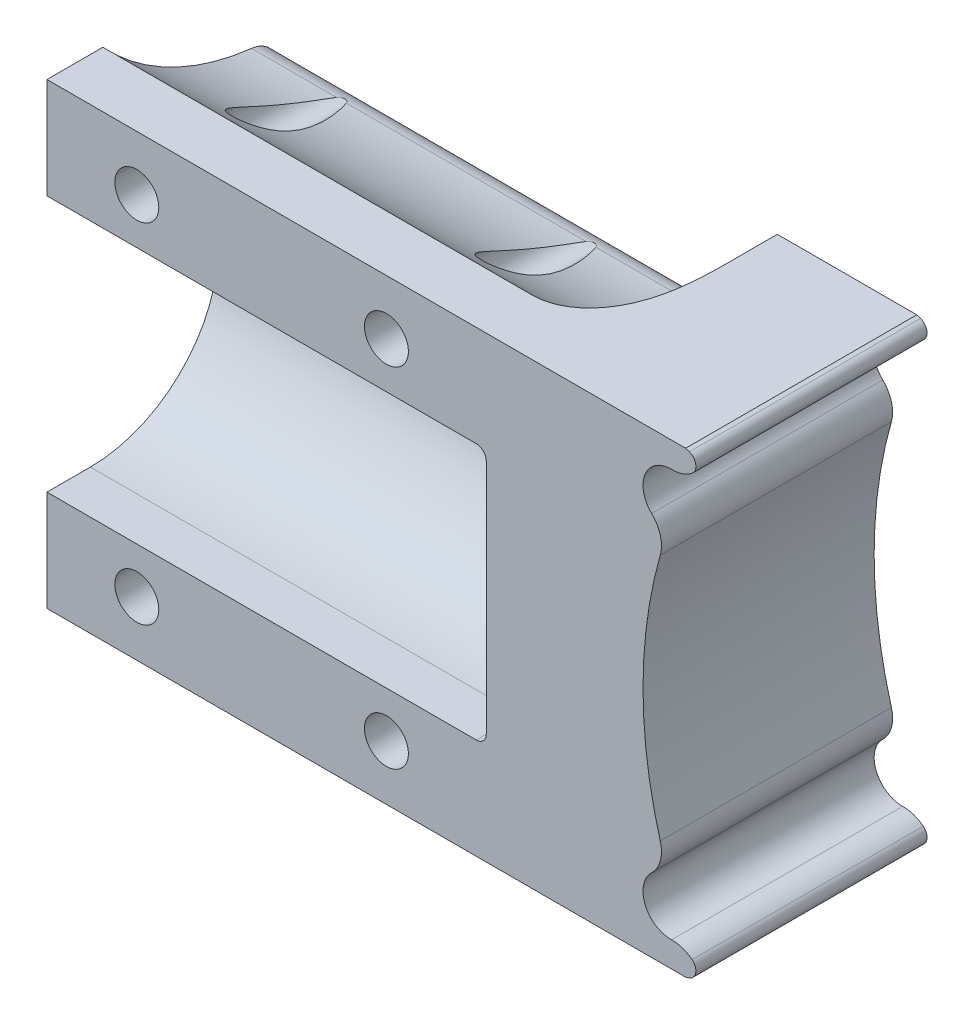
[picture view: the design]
ISO-10303-21;
HEADER;
FILE_DESCRIPTION(('STEP AP214'),'2;1');
FILE_NAME('part.step','',(''),(''),'','','');
FILE_SCHEMA(('AUTOMOTIVE_DESIGN { 1 0 10303 214 1 1 1 1 }'));
ENDSEC;
DATA;
#1=APPLICATION_CONTEXT('core data for automotive mechanical design processes');
#2=APPLICATION_PROTOCOL_DEFINITION('international standard','automotive_design',2000,#1);
#3=PRODUCT_CONTEXT('',#1,'mechanical');
#4=PRODUCT('Part','Part','',(#3));
#5=PRODUCT_RELATED_PRODUCT_CATEGORY('part','',(#4));
#6=PRODUCT_DEFINITION_FORMATION('','',#4);
#7=PRODUCT_DEFINITION_CONTEXT('part definition',#1,'design');
#8=PRODUCT_DEFINITION('design','',#6,#7);
#9=PRODUCT_DEFINITION_SHAPE('','',#8);
#10=(LENGTH_UNIT() NAMED_UNIT(*) SI_UNIT(.MILLI.,.METRE.));
#11=(NAMED_UNIT(*) PLANE_ANGLE_UNIT() SI_UNIT($,.RADIAN.));
#12=(NAMED_UNIT(*) SI_UNIT($,.STERADIAN.) SOLID_ANGLE_UNIT());
#13=UNCERTAINTY_MEASURE_WITH_UNIT(LENGTH_MEASURE(1.E-05),#10,'distance_accuracy_value','');
#14=(GEOMETRIC_REPRESENTATION_CONTEXT(3) GLOBAL_UNCERTAINTY_ASSIGNED_CONTEXT((#13)) GLOBAL_UNIT_ASSIGNED_CONTEXT((#10,
#11,#12)) REPRESENTATION_CONTEXT('',''));
#15=CARTESIAN_POINT('',(0.,0.,0.));
#16=DIRECTION('',(0.,0.,1.));
#17=DIRECTION('',(1.,0.,0.));
#18=AXIS2_PLACEMENT_3D('',#15,#16,#17);
#19=CARTESIAN_POINT('',(50.,-22.9398492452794,0.));
#20=DIRECTION('',(0.,1.,0.));
#21=DIRECTION('',(0.,0.,1.));
#22=AXIS2_PLACEMENT_3D('',#19,#20,#21);
#23=PLANE('',#22);
#24=DIRECTION('',(1.,0.,0.));
#25=VECTOR('',#24,1.);
#26=CARTESIAN_POINT('',(0.,-22.9398492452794,-0.4));
#27=LINE('',#26,#25);
#28=CARTESIAN_POINT('',(0.,-22.9398492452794,-0.4));
#29=VERTEX_POINT('',#28);
#30=CARTESIAN_POINT('',(63.9692143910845,-22.9398492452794,-0.399999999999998));
#31=VERTEX_POINT('',#30);
#32=EDGE_CURVE('E268',#29,#31,#27,.T.);
#33=ORIENTED_EDGE('',*,*,#32,.F.);
#34=DIRECTION('',(0.,0.,-1.));
#35=VECTOR('',#34,1.);
#36=CARTESIAN_POINT('',(0.,-22.9398492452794,0.));
#37=LINE('',#36,#35);
#38=CARTESIAN_POINT('',(0.,-22.9398492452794,-6.));
#39=VERTEX_POINT('',#38);
#40=EDGE_CURVE('E285',#29,#39,#37,.T.);
#41=ORIENTED_EDGE('',*,*,#40,.T.);
#42=DIRECTION('',(-1.,0.,0.));
#43=VECTOR('',#42,1.);
#44=CARTESIAN_POINT('',(50.,-22.9398492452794,-6.));
#45=LINE('',#44,#43);
#46=CARTESIAN_POINT('',(43.,-22.9398492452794,-6.));
#47=VERTEX_POINT('',#46);
#48=EDGE_CURVE('E321',#47,#39,#45,.T.);
#49=ORIENTED_EDGE('',*,*,#48,.F.);
#50=CARTESIAN_POINT('',(43.,-22.9398492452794,-6.));
#51=CARTESIAN_POINT('',(43.1567440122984,-22.9398492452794,-5.99995899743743));
#52=CARTESIAN_POINT('',(43.3134721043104,-22.9398492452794,-6.00715912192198));
#53=CARTESIAN_POINT('',(43.6255568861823,-22.9398492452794,-6.03573656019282));
#54=CARTESIAN_POINT('',(43.7809142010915,-22.9398492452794,-6.05710703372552));
#55=CARTESIAN_POINT('',(44.0881112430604,-22.9398492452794,-6.11354422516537));
#56=CARTESIAN_POINT('',(44.2399668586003,-22.9398492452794,-6.14852475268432));
#57=CARTESIAN_POINT('',(44.5400379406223,-22.9398492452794,-6.23163812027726));
#58=CARTESIAN_POINT('',(44.6882531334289,-22.9398492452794,-6.27977194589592));
#59=CARTESIAN_POINT('',(44.9797530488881,-22.9398492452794,-6.38838771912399));
#60=CARTESIAN_POINT('',(45.1230466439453,-22.9398492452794,-6.44884591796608));
#61=CARTESIAN_POINT('',(45.4042220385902,-22.9398492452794,-6.58137314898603));
#62=CARTESIAN_POINT('',(45.5421014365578,-22.9398492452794,-6.65344726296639));
#63=CARTESIAN_POINT('',(45.8118729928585,-22.9398492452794,-6.80838239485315));
#64=CARTESIAN_POINT('',(45.9437575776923,-22.9398492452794,-6.89125657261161));
#65=CARTESIAN_POINT('',(46.2008606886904,-22.9398492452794,-7.06678420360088));
#66=CARTESIAN_POINT('',(46.3260778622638,-22.9398492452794,-7.15943962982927));
#67=CARTESIAN_POINT('',(46.6059669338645,-22.9398492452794,-7.38269201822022));
#68=CARTESIAN_POINT('',(46.7582169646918,-22.9398492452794,-7.5163368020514));
#69=CARTESIAN_POINT('',(47.050351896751,-22.9398492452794,-7.79647915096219));
#70=CARTESIAN_POINT('',(47.1902337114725,-22.9398492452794,-7.94297990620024));
#71=CARTESIAN_POINT('',(47.5910417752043,-22.9398492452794,-8.39881021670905));
#72=CARTESIAN_POINT('',(47.8333450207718,-22.9398492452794,-8.72464357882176));
#73=CARTESIAN_POINT('',(48.3591599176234,-22.9398492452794,-9.54645515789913));
#74=CARTESIAN_POINT('',(48.6189291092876,-22.9398492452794,-10.0574775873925));
#75=CARTESIAN_POINT('',(48.9470840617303,-22.9398492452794,-10.8502483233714));
#76=CARTESIAN_POINT('',(49.0465025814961,-22.9398492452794,-11.1200553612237));
#77=CARTESIAN_POINT('',(49.2264271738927,-22.9398492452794,-11.6658589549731));
#78=CARTESIAN_POINT('',(49.306939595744,-22.9398492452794,-11.9418533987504));
#79=CARTESIAN_POINT('',(49.5191215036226,-22.9398492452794,-12.7605130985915));
#80=CARTESIAN_POINT('',(49.6274334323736,-22.9398492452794,-13.309213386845));
#81=CARTESIAN_POINT('',(49.795746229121,-22.9398492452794,-14.4147405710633));
#82=CARTESIAN_POINT('',(49.8556282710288,-22.9398492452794,-14.9715840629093));
#83=CARTESIAN_POINT('',(49.9190284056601,-22.9398492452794,-15.8002040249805));
#84=CARTESIAN_POINT('',(49.9356916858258,-22.9398492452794,-16.0710994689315));
#85=CARTESIAN_POINT('',(49.962449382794,-22.9398492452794,-16.6132407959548));
#86=CARTESIAN_POINT('',(49.9725432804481,-22.9398492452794,-16.884486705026));
#87=CARTESIAN_POINT('',(49.987579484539,-22.9398492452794,-17.4256106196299));
#88=CARTESIAN_POINT('',(49.9925498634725,-22.9398492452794,-17.6954879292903));
#89=CARTESIAN_POINT('',(49.9987501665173,-22.9398492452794,-18.2352124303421));
#90=CARTESIAN_POINT('',(49.9999811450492,-22.9398492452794,-18.505059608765));
#91=CARTESIAN_POINT('',(50.,-22.9398492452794,-18.7748901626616));
#92=B_SPLINE_CURVE_WITH_KNOTS('',3,(#50,#51,#52,#53,#54,#55,#56,#57,#58,#59,#60,#61,#62,#63,#64,
#65,#66,#67,#68,#69,#70,#71,#72,#73,#74,#75,#76,#77,#78,#79,#80,#81,#82,#83,#84,#85,#86,#87,#88,
#89,#90,#91),.UNSPECIFIED.,.F.,.F.,(4,2,2,2,2,2,2,2,2,2,2,2,2,2,2,2,2,2,2,2,4),(0.,
0.470041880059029,0.939857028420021,1.40674410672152,1.87366617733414,2.33969686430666,
2.80593198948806,3.27274062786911,3.73964360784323,4.34650229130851,4.9535119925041,
6.16671054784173,7.87660132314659,8.73874642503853,9.60060157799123,11.2752124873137,
12.9539198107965,13.7680828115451,14.5823101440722,15.3920521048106,16.2015657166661),.UNSPECIFIED.);
#93=CARTESIAN_POINT('',(50.,-22.9398492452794,-18.7748901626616));
#94=VERTEX_POINT('',#93);
#95=EDGE_CURVE('E414',#47,#94,#92,.T.);
#96=ORIENTED_EDGE('',*,*,#95,.T.);
#97=DIRECTION('',(0.,0.,1.));
#98=VECTOR('',#97,1.);
#99=CARTESIAN_POINT('',(50.,-22.9398492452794,-72.0435791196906));
#100=LINE('',#99,#98);
#101=CARTESIAN_POINT('',(50.,-22.9398492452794,-23.55));
#102=VERTEX_POINT('',#101);
#103=EDGE_CURVE('E720',#102,#94,#100,.T.);
#104=ORIENTED_EDGE('',*,*,#103,.F.);
#105=DIRECTION('',(-1.,0.,0.));
#106=VECTOR('',#105,1.);
#107=CARTESIAN_POINT('',(0.,-22.9398492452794,-23.55));
#108=LINE('',#107,#106);
#109=CARTESIAN_POINT('',(63.9692143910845,-22.9398492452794,-23.55));
#110=VERTEX_POINT('',#109);
#111=EDGE_CURVE('E735',#110,#102,#108,.T.);
#112=ORIENTED_EDGE('',*,*,#111,.F.);
#113=DIRECTION('',(0.,0.,1.));
#114=VECTOR('',#113,1.);
#115=CARTESIAN_POINT('',(63.9692143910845,-22.9398492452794,-69.8217694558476));
#116=LINE('',#115,#114);
#117=EDGE_CURVE('E287',#110,#31,#116,.T.);
#118=ORIENTED_EDGE('',*,*,#117,.T.);
#119=EDGE_LOOP('',(#33,#41,#49,#96,#104,#112,#118));
#120=FACE_BOUND('',#119,.T.);
#121=ADVANCED_FACE('F49',(#120),#23,.F.);
#122=CARTESIAN_POINT('',(50.,22.9398492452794,0.));
#123=DIRECTION('',(0.,-1.,0.));
#124=DIRECTION('',(0.,0.,-1.));
#125=AXIS2_PLACEMENT_3D('',#122,#123,#124);
#126=PLANE('',#125);
#127=DIRECTION('',(-1.,0.,0.));
#128=VECTOR('',#127,1.);
#129=CARTESIAN_POINT('',(0.,22.9398492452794,-0.4));
#130=LINE('',#129,#128);
#131=CARTESIAN_POINT('',(63.9692143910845,22.9398492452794,-0.399999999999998));
#132=VERTEX_POINT('',#131);
#133=CARTESIAN_POINT('',(0.,22.9398492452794,-0.4));
#134=VERTEX_POINT('',#133);
#135=EDGE_CURVE('E289',#132,#134,#130,.T.);
#136=ORIENTED_EDGE('',*,*,#135,.F.);
#137=DIRECTION('',(0.,0.,1.));
#138=VECTOR('',#137,1.);
#139=CARTESIAN_POINT('',(63.9692143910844,22.9398492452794,-69.8217694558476));
#140=LINE('',#139,#138);
#141=CARTESIAN_POINT('',(63.9692143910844,22.9398492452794,-23.55));
#142=VERTEX_POINT('',#141);
#143=EDGE_CURVE('E677',#142,#132,#140,.T.);
#144=ORIENTED_EDGE('',*,*,#143,.F.);
#145=DIRECTION('',(1.,0.,0.));
#146=VECTOR('',#145,1.);
#147=CARTESIAN_POINT('',(0.,22.9398492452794,-23.55));
#148=LINE('',#147,#146);
#149=CARTESIAN_POINT('',(50.,22.9398492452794,-23.55));
#150=VERTEX_POINT('',#149);
#151=EDGE_CURVE('E728',#150,#142,#148,.T.);
#152=ORIENTED_EDGE('',*,*,#151,.F.);
#153=DIRECTION('',(0.,0.,1.));
#154=VECTOR('',#153,1.);
#155=CARTESIAN_POINT('',(50.,22.9398492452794,-72.0435791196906));
#156=LINE('',#155,#154);
#157=CARTESIAN_POINT('',(50.,22.9398492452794,-18.7748901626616));
#158=VERTEX_POINT('',#157);
#159=EDGE_CURVE('E709',#150,#158,#156,.T.);
#160=ORIENTED_EDGE('',*,*,#159,.T.);
#161=CARTESIAN_POINT('',(50.,22.9398492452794,-18.7748901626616));
#162=CARTESIAN_POINT('',(49.9999747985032,22.9398492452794,-18.4850096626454));
#163=CARTESIAN_POINT('',(49.9985573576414,22.9398492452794,-18.1951043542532));
#164=CARTESIAN_POINT('',(49.9912954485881,22.9398492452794,-17.6152426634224));
#165=CARTESIAN_POINT('',(49.9854492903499,22.9398492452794,-17.325286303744));
#166=CARTESIAN_POINT('',(49.9676179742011,22.9398492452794,-16.7433581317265));
#167=CARTESIAN_POINT('',(49.9555868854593,22.9398492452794,-16.4513875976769));
#168=CARTESIAN_POINT('',(49.9235253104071,22.9398492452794,-15.8679096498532));
#169=CARTESIAN_POINT('',(49.9034957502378,22.9398492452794,-15.5764021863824));
#170=CARTESIAN_POINT('',(49.8529973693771,22.9398492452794,-14.9883362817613));
#171=CARTESIAN_POINT('',(49.8223265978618,22.9398492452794,-14.6917942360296));
#172=CARTESIAN_POINT('',(49.7485056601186,22.9398492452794,-14.1002784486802));
#173=CARTESIAN_POINT('',(49.7053537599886,22.9398492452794,-13.8053049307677));
#174=CARTESIAN_POINT('',(49.5541030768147,22.9398492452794,-12.925843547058));
#175=CARTESIAN_POINT('',(49.4240528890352,22.9398492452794,-12.3445971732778));
#176=CARTESIAN_POINT('',(49.1955901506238,22.9398492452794,-11.5712953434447));
#177=CARTESIAN_POINT('',(49.1305538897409,22.9398492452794,-11.3691742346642));
#178=CARTESIAN_POINT('',(48.9898273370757,22.9398492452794,-10.9685768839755));
#179=CARTESIAN_POINT('',(48.9141343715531,22.9398492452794,-10.7701015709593));
#180=CARTESIAN_POINT('',(48.7515440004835,22.9398492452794,-10.3784272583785));
#181=CARTESIAN_POINT('',(48.6646785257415,22.9398492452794,-10.1852150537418));
#182=CARTESIAN_POINT('',(48.4788432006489,22.9398492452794,-9.80468884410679));
#183=CARTESIAN_POINT('',(48.3798741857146,22.9398492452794,-9.61737443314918));
#184=CARTESIAN_POINT('',(48.168089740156,22.9398492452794,-9.24813870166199));
#185=CARTESIAN_POINT('',(48.0551422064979,22.9398492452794,-9.06629279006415));
#186=CARTESIAN_POINT('',(47.8157094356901,22.9398492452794,-8.71174871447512));
#187=CARTESIAN_POINT('',(47.6892267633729,22.9398492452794,-8.53904882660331));
#188=CARTESIAN_POINT('',(47.4223990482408,22.9398492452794,-8.20470801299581));
#189=CARTESIAN_POINT('',(47.2820560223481,22.9398492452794,-8.04306548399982));
#190=CARTESIAN_POINT('',(46.9874613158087,22.9398492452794,-7.73299360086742));
#191=CARTESIAN_POINT('',(46.833213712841,22.9398492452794,-7.58456039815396));
#192=CARTESIAN_POINT('',(46.5479809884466,22.9398492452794,-7.33541276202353));
#193=CARTESIAN_POINT('',(46.4197408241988,22.9398492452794,-7.23154752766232));
#194=CARTESIAN_POINT('',(46.1555248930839,22.9398492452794,-7.0341903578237));
#195=CARTESIAN_POINT('',(46.0195508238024,22.9398492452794,-6.94069615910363));
#196=CARTESIAN_POINT('',(45.7405636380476,22.9398492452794,-6.76532669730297));
#197=CARTESIAN_POINT('',(45.597561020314,22.9398492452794,-6.68343477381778));
#198=CARTESIAN_POINT('',(45.3051147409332,22.9398492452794,-6.53224455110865));
#199=CARTESIAN_POINT('',(45.155674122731,22.9398492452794,-6.46294038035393));
#200=CARTESIAN_POINT('',(44.8456264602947,22.9398492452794,-6.3356125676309));
#201=CARTESIAN_POINT('',(44.6848109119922,22.9398492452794,-6.27809445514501));
#202=CARTESIAN_POINT('',(44.3584355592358,22.9398492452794,-6.17862733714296));
#203=CARTESIAN_POINT('',(44.1928761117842,22.9398492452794,-6.1366771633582));
#204=CARTESIAN_POINT('',(43.8570375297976,22.9398492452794,-6.06884020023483));
#205=CARTESIAN_POINT('',(43.6867304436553,22.9398492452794,-6.0430912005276));
#206=CARTESIAN_POINT('',(43.3442913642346,22.9398492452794,-6.00863578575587));
#207=CARTESIAN_POINT('',(43.1721582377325,22.9398492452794,-5.99994066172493));
#208=CARTESIAN_POINT('',(43.,22.9398492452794,-5.99999999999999));
#209=B_SPLINE_CURVE_WITH_KNOTS('',3,(#161,#162,#163,#164,#165,#166,#167,#168,#169,#170,#171,
#172,#173,#174,#175,#176,#177,#178,#179,#180,#181,#182,#183,#184,#185,#186,#187,#188,#189,#190,
#191,#192,#193,#194,#195,#196,#197,#198,#199,#200,#201,#202,#203,#204,#205,#206,#207,#208),
.UNSPECIFIED.,.F.,.F.,(4,2,2,2,2,2,2,2,2,2,2,2,2,2,2,2,2,2,2,2,2,2,2,4),(0.,0.869676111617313,
1.73968426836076,2.61624871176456,3.49271168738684,4.38681102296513,5.28103462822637,
7.0628324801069,7.69958927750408,8.33650612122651,8.97164151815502,9.60673310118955,
10.2483652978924,10.8898761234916,11.5312937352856,12.1725238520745,12.6671403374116,
13.1616486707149,13.6554395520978,14.1489995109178,14.6606184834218,15.172199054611,
15.6880737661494,16.2042899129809),.UNSPECIFIED.);
#210=CARTESIAN_POINT('',(43.,22.9398492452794,-6.));
#211=VERTEX_POINT('',#210);
#212=EDGE_CURVE('E423',#158,#211,#209,.T.);
#213=ORIENTED_EDGE('',*,*,#212,.T.);
#214=DIRECTION('',(-1.,0.,0.));
#215=VECTOR('',#214,1.);
#216=CARTESIAN_POINT('',(50.,22.9398492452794,-6.));
#217=LINE('',#216,#215);
#218=CARTESIAN_POINT('',(0.,22.9398492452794,-6.));
#219=VERTEX_POINT('',#218);
#220=EDGE_CURVE('E319',#211,#219,#217,.T.);
#221=ORIENTED_EDGE('',*,*,#220,.T.);
#222=DIRECTION('',(0.,0.,1.));
#223=VECTOR('',#222,1.);
#224=CARTESIAN_POINT('',(0.,22.9398492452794,0.));
#225=LINE('',#224,#223);
#226=EDGE_CURVE('E311',#219,#134,#225,.T.);
#227=ORIENTED_EDGE('',*,*,#226,.T.);
#228=EDGE_LOOP('',(#136,#144,#152,#160,#213,#221,#227));
#229=FACE_BOUND('',#228,.T.);
#230=ADVANCED_FACE('F409',(#229),#126,.F.);
#231=CARTESIAN_POINT('',(0.,0.,-4.75));
#232=DIRECTION('',(1.,0.,0.));
#233=DIRECTION('',(0.,0.,-1.));
#234=AXIS2_PLACEMENT_3D('',#231,#232,#233);
#235=PLANE('',#234);
#236=DIRECTION('',(0.,-1.,0.));
#237=VECTOR('',#236,1.);
#238=CARTESIAN_POINT('',(0.,22.9398492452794,-0.4));
#239=LINE('',#238,#237);
#240=CARTESIAN_POINT('',(0.,12.85,-0.4));
#241=VERTEX_POINT('',#240);
#242=EDGE_CURVE('E280',#134,#241,#239,.T.);
#243=ORIENTED_EDGE('',*,*,#242,.F.);
#244=ORIENTED_EDGE('',*,*,#226,.F.);
#245=CARTESIAN_POINT('',(0.,39.1214875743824,-23.55));
#246=DIRECTION('',(-1.,0.,0.));
#247=DIRECTION('',(0.,0.,-1.));
#248=AXIS2_PLACEMENT_3D('',#245,#246,#247);
#249=CIRCLE('',#248,23.8714875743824);
#250=CARTESIAN_POINT('',(0.,15.3992341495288,-20.8849274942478));
#251=VERTEX_POINT('',#250);
#252=EDGE_CURVE('E308',#251,#219,#249,.T.);
#253=ORIENTED_EDGE('',*,*,#252,.F.);
#254=CARTESIAN_POINT('',(0.,12.4179888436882,-20.55));
#255=DIRECTION('',(1.,0.,0.));
#256=DIRECTION('',(0.,0.,-1.));
#257=AXIS2_PLACEMENT_3D('',#254,#255,#256);
#258=CIRCLE('',#257,3.);
#259=CARTESIAN_POINT('',(0.,12.4179888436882,-23.55));
#260=VERTEX_POINT('',#259);
#261=EDGE_CURVE('E333',#251,#260,#258,.F.);
#262=ORIENTED_EDGE('',*,*,#261,.T.);
#263=DIRECTION('',(0.,1.,0.));
#264=VECTOR('',#263,1.);
#265=CARTESIAN_POINT('',(0.,-15.25,-23.55));
#266=LINE('',#265,#264);
#267=CARTESIAN_POINT('',(0.,-12.4179888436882,-23.55));
#268=VERTEX_POINT('',#267);
#269=EDGE_CURVE('E299',#268,#260,#266,.T.);
#270=ORIENTED_EDGE('',*,*,#269,.F.);
#271=CARTESIAN_POINT('',(0.,-12.4179888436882,-20.55));
#272=DIRECTION('',(1.,0.,0.));
#273=DIRECTION('',(0.,0.,-1.));
#274=AXIS2_PLACEMENT_3D('',#271,#272,#273);
#275=CIRCLE('',#274,3.);
#276=CARTESIAN_POINT('',(0.,-15.3992341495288,-20.8849274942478));
#277=VERTEX_POINT('',#276);
#278=EDGE_CURVE('E335',#268,#277,#275,.F.);
#279=ORIENTED_EDGE('',*,*,#278,.T.);
#280=CARTESIAN_POINT('',(0.,-39.1214875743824,-23.55));
#281=DIRECTION('',(-1.,0.,0.));
#282=DIRECTION('',(0.,0.,1.));
#283=AXIS2_PLACEMENT_3D('',#280,#281,#282);
#284=CIRCLE('',#283,23.8714875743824);
#285=EDGE_CURVE('E291',#39,#277,#284,.T.);
#286=ORIENTED_EDGE('',*,*,#285,.F.);
#287=ORIENTED_EDGE('',*,*,#40,.F.);
#288=CARTESIAN_POINT('',(0.,-12.85,-0.4));
#289=VERTEX_POINT('',#288);
#290=EDGE_CURVE('E264',#289,#29,#239,.T.);
#291=ORIENTED_EDGE('',*,*,#290,.F.);
#292=DIRECTION('',(0.,0.,1.));
#293=VECTOR('',#292,1.);
#294=CARTESIAN_POINT('',(0.,-12.85,-4.75));
#295=LINE('',#294,#293);
#296=CARTESIAN_POINT('',(0.,-12.85,-4.75));
#297=VERTEX_POINT('',#296);
#298=EDGE_CURVE('E501',#297,#289,#295,.T.);
#299=ORIENTED_EDGE('',*,*,#298,.F.);
#300=CARTESIAN_POINT('',(0.,0.,-4.75));
#301=DIRECTION('',(-1.,0.,0.));
#302=DIRECTION('',(0.,0.,-1.));
#303=AXIS2_PLACEMENT_3D('',#300,#301,#302);
#304=CIRCLE('',#303,12.85);
#305=CARTESIAN_POINT('',(0.,12.85,-4.75));
#306=VERTEX_POINT('',#305);
#307=EDGE_CURVE('E296',#306,#297,#304,.T.);
#308=ORIENTED_EDGE('',*,*,#307,.F.);
#309=DIRECTION('',(0.,0.,-1.));
#310=VECTOR('',#309,1.);
#311=CARTESIAN_POINT('',(0.,12.85,-4.75));
#312=LINE('',#311,#310);
#313=EDGE_CURVE('E764',#241,#306,#312,.T.);
#314=ORIENTED_EDGE('',*,*,#313,.F.);
#315=EDGE_LOOP('',(#243,#244,#253,#262,#270,#279,#286,#287,#291,#299,#308,#314));
#316=FACE_BOUND('',#315,.T.);
#317=ADVANCED_FACE('F295',(#316),#235,.F.);
#318=CARTESIAN_POINT('',(44.,0.,-4.75));
#319=DIRECTION('',(1.,0.,0.));
#320=DIRECTION('',(0.,0.,-1.));
#321=AXIS2_PLACEMENT_3D('',#318,#319,#320);
#322=PLANE('',#321);
#323=DIRECTION('',(0.,-1.,0.));
#324=VECTOR('',#323,1.);
#325=CARTESIAN_POINT('',(44.,0.,-0.4));
#326=LINE('',#325,#324);
#327=CARTESIAN_POINT('',(44.,11.85,-0.4));
#328=VERTEX_POINT('',#327);
#329=CARTESIAN_POINT('',(44.,-11.85,-0.4));
#330=VERTEX_POINT('',#329);
#331=EDGE_CURVE('E63',#328,#330,#326,.T.);
#332=ORIENTED_EDGE('',*,*,#331,.F.);
#333=DIRECTION('',(0.,0.,-1.));
#334=VECTOR('',#333,1.);
#335=CARTESIAN_POINT('',(44.,11.85,-4.75));
#336=LINE('',#335,#334);
#337=CARTESIAN_POINT('',(44.,11.85,-4.75));
#338=VERTEX_POINT('',#337);
#339=EDGE_CURVE('E516',#328,#338,#336,.T.);
#340=ORIENTED_EDGE('',*,*,#339,.T.);
#341=CARTESIAN_POINT('',(44.,0.,-4.75));
#342=DIRECTION('',(1.,0.,0.));
#343=DIRECTION('',(0.,0.,-1.));
#344=AXIS2_PLACEMENT_3D('',#341,#342,#343);
#345=CIRCLE('',#344,11.85);
#346=CARTESIAN_POINT('',(44.,-11.85,-4.75));
#347=VERTEX_POINT('',#346);
#348=EDGE_CURVE('E495',#338,#347,#345,.F.);
#349=ORIENTED_EDGE('',*,*,#348,.T.);
#350=DIRECTION('',(0.,0.,1.));
#351=VECTOR('',#350,1.);
#352=CARTESIAN_POINT('',(44.,-11.85,0.));
#353=LINE('',#352,#351);
#354=EDGE_CURVE('E513',#347,#330,#353,.T.);
#355=ORIENTED_EDGE('',*,*,#354,.T.);
#356=EDGE_LOOP('',(#332,#340,#349,#355));
#357=FACE_BOUND('',#356,.T.);
#358=ADVANCED_FACE('F650',(#357),#322,.F.);
#359=CARTESIAN_POINT('',(62.6302829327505,23.6020565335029,-69.8217694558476));
#360=DIRECTION('',(0.,0.,1.));
#361=DIRECTION('',(1.,0.,0.));
#362=AXIS2_PLACEMENT_3D('',#359,#360,#361);
#363=CYLINDRICAL_SURFACE('',#362,3.20000000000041);
#364=DIRECTION('',(0.,0.,1.));
#365=VECTOR('',#364,1.);
#366=CARTESIAN_POINT('',(64.6198496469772,21.095739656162,-69.8217694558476));
#367=LINE('',#366,#365);
#368=CARTESIAN_POINT('',(64.6198496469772,21.095739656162,-23.55));
#369=VERTEX_POINT('',#368);
#370=CARTESIAN_POINT('',(64.6198496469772,21.095739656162,-0.399999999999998));
#371=VERTEX_POINT('',#370);
#372=EDGE_CURVE('E699',#369,#371,#367,.T.);
#373=ORIENTED_EDGE('',*,*,#372,.T.);
#374=CARTESIAN_POINT('',(62.6302829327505,23.6020565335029,-0.399999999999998));
#375=DIRECTION('',(0.,0.,1.));
#376=DIRECTION('',(1.,0.,0.));
#377=AXIS2_PLACEMENT_3D('',#374,#375,#376);
#378=CIRCLE('',#377,3.20000000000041);
#379=CARTESIAN_POINT('',(62.5616208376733,20.4027932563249,-0.399999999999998));
#380=VERTEX_POINT('',#379);
#381=EDGE_CURVE('E948',#371,#380,#378,.F.);
#382=ORIENTED_EDGE('',*,*,#381,.T.);
#383=DIRECTION('',(0.,0.,1.));
#384=VECTOR('',#383,1.);
#385=CARTESIAN_POINT('',(62.5616208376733,20.4027932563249,-69.8217694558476));
#386=LINE('',#385,#384);
#387=CARTESIAN_POINT('',(62.5616208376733,20.4027932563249,-23.55));
#388=VERTEX_POINT('',#387);
#389=EDGE_CURVE('E810',#388,#380,#386,.T.);
#390=ORIENTED_EDGE('',*,*,#389,.F.);
#391=CARTESIAN_POINT('',(62.6302829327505,23.6020565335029,-23.55));
#392=DIRECTION('',(0.,0.,1.));
#393=DIRECTION('',(1.,0.,0.));
#394=AXIS2_PLACEMENT_3D('',#391,#392,#393);
#395=CIRCLE('',#394,3.20000000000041);
#396=EDGE_CURVE('E826',#369,#388,#395,.F.);
#397=ORIENTED_EDGE('',*,*,#396,.F.);
#398=EDGE_LOOP('',(#373,#382,#390,#397));
#399=FACE_BOUND('',#398,.T.);
#400=ADVANCED_FACE('F620',(#399),#363,.T.);
#401=CARTESIAN_POINT('',(62.5015415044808,17.6034378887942,-69.8217694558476));
#402=DIRECTION('',(0.,0.,1.));
#403=DIRECTION('',(1.,0.,0.));
#404=AXIS2_PLACEMENT_3D('',#401,#402,#403);
#405=CYLINDRICAL_SURFACE('',#404,2.8);
#406=CARTESIAN_POINT('',(62.5015415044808,17.6034378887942,-0.399999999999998));
#407=DIRECTION('',(0.,0.,1.));
#408=DIRECTION('',(1.,0.,0.));
#409=AXIS2_PLACEMENT_3D('',#406,#407,#408);
#410=CIRCLE('',#409,2.8);
#411=CARTESIAN_POINT('',(60.5645808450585,15.5815122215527,-0.399999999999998));
#412=VERTEX_POINT('',#411);
#413=EDGE_CURVE('E955',#412,#380,#410,.F.);
#414=ORIENTED_EDGE('',*,*,#413,.F.);
#415=DIRECTION('',(0.,0.,1.));
#416=VECTOR('',#415,1.);
#417=CARTESIAN_POINT('',(60.5645808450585,15.5815122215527,-69.8217694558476));
#418=LINE('',#417,#416);
#419=CARTESIAN_POINT('',(60.5645808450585,15.5815122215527,-23.55));
#420=VERTEX_POINT('',#419);
#421=EDGE_CURVE('E833',#420,#412,#418,.T.);
#422=ORIENTED_EDGE('',*,*,#421,.F.);
#423=CARTESIAN_POINT('',(62.5015415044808,17.6034378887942,-23.55));
#424=DIRECTION('',(0.,0.,1.));
#425=DIRECTION('',(1.,0.,0.));
#426=AXIS2_PLACEMENT_3D('',#423,#424,#425);
#427=CIRCLE('',#426,2.8);
#428=EDGE_CURVE('E824',#420,#388,#427,.F.);
#429=ORIENTED_EDGE('',*,*,#428,.T.);
#430=ORIENTED_EDGE('',*,*,#389,.T.);
#431=EDGE_LOOP('',(#414,#422,#429,#430));
#432=FACE_BOUND('',#431,.T.);
#433=ADVANCED_FACE('F614',(#432),#405,.F.);
#434=CARTESIAN_POINT('',(58.3509115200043,13.2707400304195,-69.8217694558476));
#435=DIRECTION('',(0.,0.,1.));
#436=DIRECTION('',(1.,0.,0.));
#437=AXIS2_PLACEMENT_3D('',#434,#435,#436);
#438=CYLINDRICAL_SURFACE('',#437,3.2);
#439=ORIENTED_EDGE('',*,*,#421,.T.);
#440=CARTESIAN_POINT('',(58.3509115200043,13.2707400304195,-0.399999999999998));
#441=DIRECTION('',(0.,0.,1.));
#442=DIRECTION('',(1.,0.,0.));
#443=AXIS2_PLACEMENT_3D('',#440,#441,#442);
#444=CIRCLE('',#443,3.2);
#445=CARTESIAN_POINT('',(61.428911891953,12.3955750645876,-0.399999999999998));
#446=VERTEX_POINT('',#445);
#447=EDGE_CURVE('E954',#412,#446,#444,.F.);
#448=ORIENTED_EDGE('',*,*,#447,.T.);
#449=DIRECTION('',(0.,0.,1.));
#450=VECTOR('',#449,1.);
#451=CARTESIAN_POINT('',(61.428911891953,12.3955750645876,-69.8217694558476));
#452=LINE('',#451,#450);
#453=CARTESIAN_POINT('',(61.428911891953,12.3955750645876,-23.55));
#454=VERTEX_POINT('',#453);
#455=EDGE_CURVE('E836',#454,#446,#452,.T.);
#456=ORIENTED_EDGE('',*,*,#455,.F.);
#457=CARTESIAN_POINT('',(58.3509115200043,13.2707400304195,-23.55));
#458=DIRECTION('',(0.,0.,1.));
#459=DIRECTION('',(1.,0.,0.));
#460=AXIS2_PLACEMENT_3D('',#457,#458,#459);
#461=CIRCLE('',#460,3.2);
#462=EDGE_CURVE('E825',#420,#454,#461,.F.);
#463=ORIENTED_EDGE('',*,*,#462,.F.);
#464=EDGE_LOOP('',(#439,#448,#456,#463));
#465=FACE_BOUND('',#464,.T.);
#466=ADVANCED_FACE('F617',(#465),#438,.T.);
#467=CARTESIAN_POINT('',(105.,0.,-69.8217694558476));
#468=DIRECTION('',(0.,0.,1.));
#469=DIRECTION('',(1.,0.,0.));
#470=AXIS2_PLACEMENT_3D('',#467,#468,#469);
#471=CYLINDRICAL_SURFACE('',#470,45.300000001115);
#472=CARTESIAN_POINT('',(105.,0.,-0.399999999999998));
#473=DIRECTION('',(0.,0.,1.));
#474=DIRECTION('',(1.,0.,0.));
#475=AXIS2_PLACEMENT_3D('',#472,#473,#474);
#476=CIRCLE('',#475,45.300000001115);
#477=CARTESIAN_POINT('',(61.4289037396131,-12.3955464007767,-0.399999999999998));
#478=VERTEX_POINT('',#477);
#479=EDGE_CURVE('E956',#478,#446,#476,.F.);
#480=ORIENTED_EDGE('',*,*,#479,.F.);
#481=DIRECTION('',(0.,0.,1.));
#482=VECTOR('',#481,1.);
#483=CARTESIAN_POINT('',(61.4289037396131,-12.3955464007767,-69.8217694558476));
#484=LINE('',#483,#482);
#485=CARTESIAN_POINT('',(61.4289037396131,-12.3955464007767,-23.55));
#486=VERTEX_POINT('',#485);
#487=EDGE_CURVE('E844',#486,#478,#484,.T.);
#488=ORIENTED_EDGE('',*,*,#487,.F.);
#489=CARTESIAN_POINT('',(105.,0.,-23.55));
#490=DIRECTION('',(0.,0.,1.));
#491=DIRECTION('',(1.,0.,0.));
#492=AXIS2_PLACEMENT_3D('',#489,#490,#491);
#493=CIRCLE('',#492,45.300000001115);
#494=EDGE_CURVE('E819',#486,#454,#493,.F.);
#495=ORIENTED_EDGE('',*,*,#494,.T.);
#496=ORIENTED_EDGE('',*,*,#455,.T.);
#497=EDGE_LOOP('',(#480,#488,#495,#496));
#498=FACE_BOUND('',#497,.T.);
#499=ADVANCED_FACE('F621',(#498),#471,.F.);
#500=CARTESIAN_POINT('',(58.3509115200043,-13.2707400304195,-69.8217694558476));
#501=DIRECTION('',(0.,0.,1.));
#502=DIRECTION('',(1.,0.,0.));
#503=AXIS2_PLACEMENT_3D('',#500,#501,#502);
#504=CYLINDRICAL_SURFACE('',#503,3.19999999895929);
#505=ORIENTED_EDGE('',*,*,#487,.T.);
#506=CARTESIAN_POINT('',(58.3509115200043,-13.2707400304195,-0.399999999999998));
#507=DIRECTION('',(0.,0.,1.));
#508=DIRECTION('',(1.,0.,0.));
#509=AXIS2_PLACEMENT_3D('',#506,#507,#508);
#510=CIRCLE('',#509,3.19999999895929);
#511=CARTESIAN_POINT('',(60.5645808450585,-15.5815122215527,-0.399999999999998));
#512=VERTEX_POINT('',#511);
#513=EDGE_CURVE('E965',#478,#512,#510,.F.);
#514=ORIENTED_EDGE('',*,*,#513,.T.);
#515=DIRECTION('',(0.,0.,1.));
#516=VECTOR('',#515,1.);
#517=CARTESIAN_POINT('',(60.5645808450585,-15.5815122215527,-69.8217694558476));
#518=LINE('',#517,#516);
#519=CARTESIAN_POINT('',(60.5645808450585,-15.5815122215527,-23.55));
#520=VERTEX_POINT('',#519);
#521=EDGE_CURVE('E850',#520,#512,#518,.T.);
#522=ORIENTED_EDGE('',*,*,#521,.F.);
#523=CARTESIAN_POINT('',(58.3509115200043,-13.2707400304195,-23.55));
#524=DIRECTION('',(0.,0.,1.));
#525=DIRECTION('',(1.,0.,0.));
#526=AXIS2_PLACEMENT_3D('',#523,#524,#525);
#527=CIRCLE('',#526,3.19999999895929);
#528=EDGE_CURVE('E813',#486,#520,#527,.F.);
#529=ORIENTED_EDGE('',*,*,#528,.F.);
#530=EDGE_LOOP('',(#505,#514,#522,#529));
#531=FACE_BOUND('',#530,.T.);
#532=ADVANCED_FACE('F624',(#531),#504,.T.);
#533=CARTESIAN_POINT('',(62.5015415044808,-17.6034378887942,-69.8217694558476));
#534=DIRECTION('',(0.,0.,1.));
#535=DIRECTION('',(1.,0.,0.));
#536=AXIS2_PLACEMENT_3D('',#533,#534,#535);
#537=CYLINDRICAL_SURFACE('',#536,2.8);
#538=CARTESIAN_POINT('',(62.5015415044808,-17.6034378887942,-0.399999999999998));
#539=DIRECTION('',(0.,0.,1.));
#540=DIRECTION('',(1.,0.,0.));
#541=AXIS2_PLACEMENT_3D('',#538,#539,#540);
#542=CIRCLE('',#541,2.8);
#543=CARTESIAN_POINT('',(62.5616208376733,-20.4027932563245,-0.399999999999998));
#544=VERTEX_POINT('',#543);
#545=EDGE_CURVE('E967',#544,#512,#542,.F.);
#546=ORIENTED_EDGE('',*,*,#545,.F.);
#547=DIRECTION('',(0.,0.,1.));
#548=VECTOR('',#547,1.);
#549=CARTESIAN_POINT('',(62.5616208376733,-20.4027932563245,-69.8217694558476));
#550=LINE('',#549,#548);
#551=CARTESIAN_POINT('',(62.5616208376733,-20.4027932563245,-23.55));
#552=VERTEX_POINT('',#551);
#553=EDGE_CURVE('E852',#552,#544,#550,.T.);
#554=ORIENTED_EDGE('',*,*,#553,.F.);
#555=CARTESIAN_POINT('',(62.5015415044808,-17.6034378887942,-23.55));
#556=DIRECTION('',(0.,0.,1.));
#557=DIRECTION('',(1.,0.,0.));
#558=AXIS2_PLACEMENT_3D('',#555,#556,#557);
#559=CIRCLE('',#558,2.8);
#560=EDGE_CURVE('E812',#552,#520,#559,.F.);
#561=ORIENTED_EDGE('',*,*,#560,.T.);
#562=ORIENTED_EDGE('',*,*,#521,.T.);
#563=EDGE_LOOP('',(#546,#554,#561,#562));
#564=FACE_BOUND('',#563,.T.);
#565=ADVANCED_FACE('F626',(#564),#537,.F.);
#566=CARTESIAN_POINT('',(62.6302829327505,-23.6020565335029,-69.8217694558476));
#567=DIRECTION('',(0.,0.,1.));
#568=DIRECTION('',(1.,0.,0.));
#569=AXIS2_PLACEMENT_3D('',#566,#567,#568);
#570=CYLINDRICAL_SURFACE('',#569,3.20000000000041);
#571=ORIENTED_EDGE('',*,*,#553,.T.);
#572=CARTESIAN_POINT('',(62.6302829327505,-23.6020565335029,-0.399999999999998));
#573=DIRECTION('',(0.,0.,1.));
#574=DIRECTION('',(1.,0.,0.));
#575=AXIS2_PLACEMENT_3D('',#572,#573,#574);
#576=CIRCLE('',#575,3.20000000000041);
#577=CARTESIAN_POINT('',(64.6198496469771,-21.095739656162,-0.399999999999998));
#578=VERTEX_POINT('',#577);
#579=EDGE_CURVE('E969',#544,#578,#576,.F.);
#580=ORIENTED_EDGE('',*,*,#579,.T.);
#581=DIRECTION('',(0.,0.,1.));
#582=VECTOR('',#581,1.);
#583=CARTESIAN_POINT('',(64.6198496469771,-21.095739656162,-69.8217694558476));
#584=LINE('',#583,#582);
#585=CARTESIAN_POINT('',(64.6198496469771,-21.095739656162,-23.55));
#586=VERTEX_POINT('',#585);
#587=EDGE_CURVE('E538',#578,#586,#584,.F.);
#588=ORIENTED_EDGE('',*,*,#587,.T.);
#589=CARTESIAN_POINT('',(62.6302829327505,-23.6020565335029,-23.55));
#590=DIRECTION('',(0.,0.,1.));
#591=DIRECTION('',(1.,0.,0.));
#592=AXIS2_PLACEMENT_3D('',#589,#590,#591);
#593=CIRCLE('',#592,3.20000000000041);
#594=EDGE_CURVE('E807',#552,#586,#593,.F.);
#595=ORIENTED_EDGE('',*,*,#594,.F.);
#596=EDGE_LOOP('',(#571,#580,#588,#595));
#597=FACE_BOUND('',#596,.T.);
#598=ADVANCED_FACE('F631',(#597),#570,.T.);
#599=CARTESIAN_POINT('',(62.5409287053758,-17.9398492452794,-69.8217694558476));
#600=DIRECTION('',(0.,0.,1.));
#601=DIRECTION('',(1.,0.,0.));
#602=AXIS2_PLACEMENT_3D('',#599,#600,#601);
#603=CYLINDRICAL_SURFACE('',#602,5.20000000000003);
#604=DIRECTION('',(0.,0.,1.));
#605=VECTOR('',#604,1.);
#606=CARTESIAN_POINT('',(64.3450579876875,-22.8168480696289,-69.8217694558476));
#607=LINE('',#606,#605);
#608=CARTESIAN_POINT('',(64.3450579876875,-22.8168480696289,-23.55));
#609=VERTEX_POINT('',#608);
#610=CARTESIAN_POINT('',(64.3450579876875,-22.8168480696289,-0.399999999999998));
#611=VERTEX_POINT('',#610);
#612=EDGE_CURVE('E690',#609,#611,#607,.T.);
#613=ORIENTED_EDGE('',*,*,#612,.T.);
#614=CARTESIAN_POINT('',(62.5409287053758,-17.9398492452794,-0.399999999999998));
#615=DIRECTION('',(0.,0.,1.));
#616=DIRECTION('',(1.,0.,0.));
#617=AXIS2_PLACEMENT_3D('',#614,#615,#616);
#618=CIRCLE('',#617,5.20000000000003);
#619=EDGE_CURVE('E973',#611,#31,#618,.F.);
#620=ORIENTED_EDGE('',*,*,#619,.T.);
#621=ORIENTED_EDGE('',*,*,#117,.F.);
#622=CARTESIAN_POINT('',(62.5409287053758,-17.9398492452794,-23.55));
#623=DIRECTION('',(0.,0.,1.));
#624=DIRECTION('',(1.,0.,0.));
#625=AXIS2_PLACEMENT_3D('',#622,#623,#624);
#626=CIRCLE('',#625,5.20000000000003);
#627=EDGE_CURVE('E802',#609,#110,#626,.F.);
#628=ORIENTED_EDGE('',*,*,#627,.F.);
#629=EDGE_LOOP('',(#613,#620,#621,#628));
#630=FACE_BOUND('',#629,.T.);
#631=ADVANCED_FACE('F640',(#630),#603,.T.);
#632=CARTESIAN_POINT('',(62.5409287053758,17.9398492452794,-69.8217694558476));
#633=DIRECTION('',(0.,0.,1.));
#634=DIRECTION('',(1.,0.,0.));
#635=AXIS2_PLACEMENT_3D('',#632,#633,#634);
#636=CYLINDRICAL_SURFACE('',#635,5.20000000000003);
#637=ORIENTED_EDGE('',*,*,#143,.T.);
#638=CARTESIAN_POINT('',(62.5409287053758,17.9398492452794,-0.399999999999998));
#639=DIRECTION('',(0.,0.,1.));
#640=DIRECTION('',(1.,0.,0.));
#641=AXIS2_PLACEMENT_3D('',#638,#639,#640);
#642=CIRCLE('',#641,5.20000000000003);
#643=CARTESIAN_POINT('',(64.3450579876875,22.8168480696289,-0.399999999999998));
#644=VERTEX_POINT('',#643);
#645=EDGE_CURVE('E502',#132,#644,#642,.F.);
#646=ORIENTED_EDGE('',*,*,#645,.T.);
#647=DIRECTION('',(0.,0.,1.));
#648=VECTOR('',#647,1.);
#649=CARTESIAN_POINT('',(64.3450579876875,22.8168480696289,-69.8217694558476));
#650=LINE('',#649,#648);
#651=CARTESIAN_POINT('',(64.3450579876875,22.8168480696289,-23.55));
#652=VERTEX_POINT('',#651);
#653=EDGE_CURVE('E700',#644,#652,#650,.F.);
#654=ORIENTED_EDGE('',*,*,#653,.T.);
#655=CARTESIAN_POINT('',(62.5409287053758,17.9398492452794,-23.55));
#656=DIRECTION('',(0.,0.,1.));
#657=DIRECTION('',(1.,0.,0.));
#658=AXIS2_PLACEMENT_3D('',#655,#656,#657);
#659=CIRCLE('',#658,5.20000000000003);
#660=EDGE_CURVE('E707',#142,#652,#659,.F.);
#661=ORIENTED_EDGE('',*,*,#660,.F.);
#662=EDGE_LOOP('',(#637,#646,#654,#661));
#663=FACE_BOUND('',#662,.T.);
#664=ADVANCED_FACE('F458',(#663),#636,.T.);
#665=CARTESIAN_POINT('',(63.9981100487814,21.8789636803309,-69.8217694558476));
#666=DIRECTION('',(0.,0.,1.));
#667=DIRECTION('',(1.,0.,0.));
#668=AXIS2_PLACEMENT_3D('',#665,#666,#667);
#669=CYLINDRICAL_SURFACE('',#668,1.);
#670=ORIENTED_EDGE('',*,*,#653,.F.);
#671=CARTESIAN_POINT('',(63.9981100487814,21.8789636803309,-0.399999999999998));
#672=DIRECTION('',(0.,0.,1.));
#673=DIRECTION('',(1.,0.,0.));
#674=AXIS2_PLACEMENT_3D('',#671,#672,#673);
#675=CIRCLE('',#674,1.);
#676=EDGE_CURVE('E944',#644,#371,#675,.F.);
#677=ORIENTED_EDGE('',*,*,#676,.T.);
#678=ORIENTED_EDGE('',*,*,#372,.F.);
#679=CARTESIAN_POINT('',(63.9981100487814,21.8789636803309,-23.55));
#680=DIRECTION('',(0.,0.,1.));
#681=DIRECTION('',(1.,0.,0.));
#682=AXIS2_PLACEMENT_3D('',#679,#680,#681);
#683=CIRCLE('',#682,1.);
#684=EDGE_CURVE('E692',#652,#369,#683,.F.);
#685=ORIENTED_EDGE('',*,*,#684,.F.);
#686=EDGE_LOOP('',(#670,#677,#678,#685));
#687=FACE_BOUND('',#686,.T.);
#688=ADVANCED_FACE('F457',(#687),#669,.T.);
#689=CARTESIAN_POINT('',(63.9981100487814,-21.8789636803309,-69.8217694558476));
#690=DIRECTION('',(0.,0.,1.));
#691=DIRECTION('',(1.,0.,0.));
#692=AXIS2_PLACEMENT_3D('',#689,#690,#691);
#693=CYLINDRICAL_SURFACE('',#692,1.);
#694=ORIENTED_EDGE('',*,*,#587,.F.);
#695=CARTESIAN_POINT('',(63.9981100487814,-21.8789636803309,-0.399999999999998));
#696=DIRECTION('',(0.,0.,1.));
#697=DIRECTION('',(1.,0.,0.));
#698=AXIS2_PLACEMENT_3D('',#695,#696,#697);
#699=CIRCLE('',#698,1.);
#700=EDGE_CURVE('E972',#578,#611,#699,.F.);
#701=ORIENTED_EDGE('',*,*,#700,.T.);
#702=ORIENTED_EDGE('',*,*,#612,.F.);
#703=CARTESIAN_POINT('',(63.9981100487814,-21.8789636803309,-23.55));
#704=DIRECTION('',(0.,0.,1.));
#705=DIRECTION('',(1.,0.,0.));
#706=AXIS2_PLACEMENT_3D('',#703,#704,#705);
#707=CIRCLE('',#706,1.);
#708=EDGE_CURVE('E691',#586,#609,#707,.F.);
#709=ORIENTED_EDGE('',*,*,#708,.F.);
#710=EDGE_LOOP('',(#694,#701,#702,#709));
#711=FACE_BOUND('',#710,.T.);
#712=ADVANCED_FACE('F459',(#711),#693,.T.);
#713=CARTESIAN_POINT('',(34.,17.4398492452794,-5.));
#714=DIRECTION('',(0.,0.,1.));
#715=DIRECTION('',(1.,0.,0.));
#716=AXIS2_PLACEMENT_3D('',#713,#714,#715);
#717=CYLINDRICAL_SURFACE('',#716,2.2);
#718=CARTESIAN_POINT('',(34.,17.4398492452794,-5.));
#719=DIRECTION('',(0.,0.,1.));
#720=DIRECTION('',(1.,0.,0.));
#721=AXIS2_PLACEMENT_3D('',#718,#719,#720);
#722=CIRCLE('',#721,2.2);
#723=CARTESIAN_POINT('',(36.2,17.4398492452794,-5.));
#724=VERTEX_POINT('',#723);
#725=EDGE_CURVE('E793',#724,#724,#722,.T.);
#726=ORIENTED_EDGE('',*,*,#725,.F.);
#727=EDGE_LOOP('',(#726));
#728=FACE_BOUND('',#727,.T.);
#729=CARTESIAN_POINT('',(34.,17.4398492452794,-0.4));
#730=DIRECTION('',(0.,0.,1.));
#731=DIRECTION('',(1.,0.,0.));
#732=AXIS2_PLACEMENT_3D('',#729,#730,#731);
#733=CIRCLE('',#732,2.2);
#734=CARTESIAN_POINT('',(36.2,17.4398492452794,-0.4));
#735=VERTEX_POINT('',#734);
#736=EDGE_CURVE('E978',#735,#735,#733,.F.);
#737=ORIENTED_EDGE('',*,*,#736,.F.);
#738=EDGE_LOOP('',(#737));
#739=FACE_BOUND('',#738,.T.);
#740=ADVANCED_FACE('F461',(#728,#739),#717,.F.);
#741=CARTESIAN_POINT('',(9.,-17.4398492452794,-5.));
#742=DIRECTION('',(0.,0.,1.));
#743=DIRECTION('',(1.,0.,0.));
#744=AXIS2_PLACEMENT_3D('',#741,#742,#743);
#745=CYLINDRICAL_SURFACE('',#744,2.2);
#746=CARTESIAN_POINT('',(9.,-17.4398492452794,-5.));
#747=DIRECTION('',(0.,0.,1.));
#748=DIRECTION('',(1.,0.,0.));
#749=AXIS2_PLACEMENT_3D('',#746,#747,#748);
#750=CIRCLE('',#749,2.2);
#751=CARTESIAN_POINT('',(11.2,-17.4398492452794,-5.));
#752=VERTEX_POINT('',#751);
#753=EDGE_CURVE('E795',#752,#752,#750,.T.);
#754=ORIENTED_EDGE('',*,*,#753,.F.);
#755=EDGE_LOOP('',(#754));
#756=FACE_BOUND('',#755,.T.);
#757=CARTESIAN_POINT('',(9.,-17.4398492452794,-0.4));
#758=DIRECTION('',(0.,0.,1.));
#759=DIRECTION('',(1.,0.,0.));
#760=AXIS2_PLACEMENT_3D('',#757,#758,#759);
#761=CIRCLE('',#760,2.2);
#762=CARTESIAN_POINT('',(11.2,-17.4398492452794,-0.4));
#763=VERTEX_POINT('',#762);
#764=EDGE_CURVE('E1002',#763,#763,#761,.F.);
#765=ORIENTED_EDGE('',*,*,#764,.F.);
#766=EDGE_LOOP('',(#765));
#767=FACE_BOUND('',#766,.T.);
#768=ADVANCED_FACE('F589',(#756,#767),#745,.F.);
#769=CARTESIAN_POINT('',(34.,-17.4398492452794,-5.));
#770=DIRECTION('',(0.,0.,1.));
#771=DIRECTION('',(1.,0.,0.));
#772=AXIS2_PLACEMENT_3D('',#769,#770,#771);
#773=CYLINDRICAL_SURFACE('',#772,2.2);
#774=CARTESIAN_POINT('',(34.,-17.4398492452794,-5.));
#775=DIRECTION('',(0.,0.,1.));
#776=DIRECTION('',(1.,0.,0.));
#777=AXIS2_PLACEMENT_3D('',#774,#775,#776);
#778=CIRCLE('',#777,2.2);
#779=CARTESIAN_POINT('',(36.2,-17.4398492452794,-5.));
#780=VERTEX_POINT('',#779);
#781=EDGE_CURVE('E784',#780,#780,#778,.T.);
#782=ORIENTED_EDGE('',*,*,#781,.F.);
#783=EDGE_LOOP('',(#782));
#784=FACE_BOUND('',#783,.T.);
#785=CARTESIAN_POINT('',(34.,-17.4398492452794,-0.4));
#786=DIRECTION('',(0.,0.,1.));
#787=DIRECTION('',(1.,0.,0.));
#788=AXIS2_PLACEMENT_3D('',#785,#786,#787);
#789=CIRCLE('',#788,2.2);
#790=CARTESIAN_POINT('',(36.2,-17.4398492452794,-0.4));
#791=VERTEX_POINT('',#790);
#792=EDGE_CURVE('E1003',#791,#791,#789,.F.);
#793=ORIENTED_EDGE('',*,*,#792,.F.);
#794=EDGE_LOOP('',(#793));
#795=FACE_BOUND('',#794,.T.);
#796=ADVANCED_FACE('F581',(#784,#795),#773,.F.);
#797=CARTESIAN_POINT('',(9.,17.4398492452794,-5.));
#798=DIRECTION('',(0.,0.,1.));
#799=DIRECTION('',(1.,0.,0.));
#800=AXIS2_PLACEMENT_3D('',#797,#798,#799);
#801=CYLINDRICAL_SURFACE('',#800,2.2);
#802=CARTESIAN_POINT('',(9.,17.4398492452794,-5.));
#803=DIRECTION('',(0.,0.,1.));
#804=DIRECTION('',(1.,0.,0.));
#805=AXIS2_PLACEMENT_3D('',#802,#803,#804);
#806=CIRCLE('',#805,2.2);
#807=CARTESIAN_POINT('',(11.2,17.4398492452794,-5.));
#808=VERTEX_POINT('',#807);
#809=EDGE_CURVE('E684',#808,#808,#806,.T.);
#810=ORIENTED_EDGE('',*,*,#809,.F.);
#811=EDGE_LOOP('',(#810));
#812=FACE_BOUND('',#811,.T.);
#813=CARTESIAN_POINT('',(9.,17.4398492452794,-0.4));
#814=DIRECTION('',(0.,0.,1.));
#815=DIRECTION('',(1.,0.,0.));
#816=AXIS2_PLACEMENT_3D('',#813,#814,#815);
#817=CIRCLE('',#816,2.2);
#818=CARTESIAN_POINT('',(11.2,17.4398492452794,-0.4));
#819=VERTEX_POINT('',#818);
#820=EDGE_CURVE('E1010',#819,#819,#817,.F.);
#821=ORIENTED_EDGE('',*,*,#820,.F.);
#822=EDGE_LOOP('',(#821));
#823=FACE_BOUND('',#822,.T.);
#824=ADVANCED_FACE('F590',(#812,#823),#801,.F.);
#825=CARTESIAN_POINT('',(48.8364113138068,-12.85,-4.75));
#826=DIRECTION('',(0.,-1.,0.));
#827=DIRECTION('',(0.,0.,-1.));
#828=AXIS2_PLACEMENT_3D('',#825,#826,#827);
#829=PLANE('',#828);
#830=DIRECTION('',(-1.,0.,0.));
#831=VECTOR('',#830,1.);
#832=CARTESIAN_POINT('',(48.8364113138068,-12.85,-0.4));
#833=LINE('',#832,#831);
#834=CARTESIAN_POINT('',(43.,-12.85,-0.4));
#835=VERTEX_POINT('',#834);
#836=EDGE_CURVE('E271',#835,#289,#833,.T.);
#837=ORIENTED_EDGE('',*,*,#836,.F.);
#838=DIRECTION('',(0.,0.,1.));
#839=VECTOR('',#838,1.);
#840=CARTESIAN_POINT('',(43.,-12.85,-4.75));
#841=LINE('',#840,#839);
#842=CARTESIAN_POINT('',(43.,-12.85,-4.75));
#843=VERTEX_POINT('',#842);
#844=EDGE_CURVE('E515',#835,#843,#841,.F.);
#845=ORIENTED_EDGE('',*,*,#844,.T.);
#846=DIRECTION('',(-1.,0.,0.));
#847=VECTOR('',#846,1.);
#848=CARTESIAN_POINT('',(48.8364113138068,-12.85,-4.75));
#849=LINE('',#848,#847);
#850=EDGE_CURVE('E500',#843,#297,#849,.T.);
#851=ORIENTED_EDGE('',*,*,#850,.T.);
#852=ORIENTED_EDGE('',*,*,#298,.T.);
#853=EDGE_LOOP('',(#837,#845,#851,#852));
#854=FACE_BOUND('',#853,.T.);
#855=ADVANCED_FACE('F563',(#854),#829,.F.);
#856=CARTESIAN_POINT('',(48.8364113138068,12.85,-4.75));
#857=DIRECTION('',(0.,1.,0.));
#858=DIRECTION('',(0.,0.,1.));
#859=AXIS2_PLACEMENT_3D('',#856,#857,#858);
#860=PLANE('',#859);
#861=DIRECTION('',(1.,0.,0.));
#862=VECTOR('',#861,1.);
#863=CARTESIAN_POINT('',(48.8364113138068,12.85,-0.4));
#864=LINE('',#863,#862);
#865=CARTESIAN_POINT('',(43.,12.85,-0.4));
#866=VERTEX_POINT('',#865);
#867=EDGE_CURVE('E757',#241,#866,#864,.T.);
#868=ORIENTED_EDGE('',*,*,#867,.F.);
#869=ORIENTED_EDGE('',*,*,#313,.T.);
#870=DIRECTION('',(-1.,0.,0.));
#871=VECTOR('',#870,1.);
#872=CARTESIAN_POINT('',(48.8364113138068,12.85,-4.75));
#873=LINE('',#872,#871);
#874=CARTESIAN_POINT('',(43.,12.85,-4.75));
#875=VERTEX_POINT('',#874);
#876=EDGE_CURVE('E765',#875,#306,#873,.T.);
#877=ORIENTED_EDGE('',*,*,#876,.F.);
#878=DIRECTION('',(0.,0.,-1.));
#879=VECTOR('',#878,1.);
#880=CARTESIAN_POINT('',(43.,12.85,0.));
#881=LINE('',#880,#879);
#882=EDGE_CURVE('E509',#875,#866,#881,.F.);
#883=ORIENTED_EDGE('',*,*,#882,.T.);
#884=EDGE_LOOP('',(#868,#869,#877,#883));
#885=FACE_BOUND('',#884,.T.);
#886=ADVANCED_FACE('F758',(#885),#860,.F.);
#887=CARTESIAN_POINT('',(43.,11.85,-4.75));
#888=DIRECTION('',(0.,0.,1.));
#889=DIRECTION('',(1.,0.,0.));
#890=AXIS2_PLACEMENT_3D('',#887,#888,#889);
#891=CYLINDRICAL_SURFACE('',#890,1.);
#892=CARTESIAN_POINT('',(43.,11.85,-0.4));
#893=DIRECTION('',(0.,0.,1.));
#894=DIRECTION('',(1.,0.,0.));
#895=AXIS2_PLACEMENT_3D('',#892,#893,#894);
#896=CIRCLE('',#895,1.);
#897=EDGE_CURVE('E754',#866,#328,#896,.F.);
#898=ORIENTED_EDGE('',*,*,#897,.F.);
#899=ORIENTED_EDGE('',*,*,#882,.F.);
#900=CARTESIAN_POINT('',(43.,11.85,-4.75));
#901=DIRECTION('',(0.,0.,1.));
#902=DIRECTION('',(1.,0.,0.));
#903=AXIS2_PLACEMENT_3D('',#900,#901,#902);
#904=CIRCLE('',#903,1.);
#905=EDGE_CURVE('E489',#338,#875,#904,.T.);
#906=ORIENTED_EDGE('',*,*,#905,.F.);
#907=ORIENTED_EDGE('',*,*,#339,.F.);
#908=EDGE_LOOP('',(#898,#899,#906,#907));
#909=FACE_BOUND('',#908,.T.);
#910=ADVANCED_FACE('F55',(#909),#891,.F.);
#911=CARTESIAN_POINT('',(43.,-11.85,-4.75));
#912=DIRECTION('',(0.,0.,-1.));
#913=DIRECTION('',(-1.,0.,0.));
#914=AXIS2_PLACEMENT_3D('',#911,#912,#913);
#915=CYLINDRICAL_SURFACE('',#914,1.);
#916=CARTESIAN_POINT('',(43.,-11.85,-0.4));
#917=DIRECTION('',(0.,0.,1.));
#918=DIRECTION('',(1.,0.,0.));
#919=AXIS2_PLACEMENT_3D('',#916,#917,#918);
#920=CIRCLE('',#919,1.);
#921=EDGE_CURVE('E12',#330,#835,#920,.F.);
#922=ORIENTED_EDGE('',*,*,#921,.F.);
#923=ORIENTED_EDGE('',*,*,#354,.F.);
#924=CARTESIAN_POINT('',(43.,-11.85,-4.75));
#925=DIRECTION('',(0.,0.,-1.));
#926=DIRECTION('',(-1.,0.,0.));
#927=AXIS2_PLACEMENT_3D('',#924,#925,#926);
#928=CIRCLE('',#927,1.);
#929=EDGE_CURVE('E498',#347,#843,#928,.T.);
#930=ORIENTED_EDGE('',*,*,#929,.T.);
#931=ORIENTED_EDGE('',*,*,#844,.F.);
#932=EDGE_LOOP('',(#922,#923,#930,#931));
#933=FACE_BOUND('',#932,.T.);
#934=ADVANCED_FACE('F477',(#933),#915,.F.);
#935=CARTESIAN_POINT('',(50.,0.,-4.75));
#936=DIRECTION('',(-1.,0.,0.));
#937=DIRECTION('',(0.,0.,1.));
#938=AXIS2_PLACEMENT_3D('',#935,#936,#937);
#939=CYLINDRICAL_SURFACE('',#938,12.85);
#940=CARTESIAN_POINT('',(6.9,0.,-17.6));
#941=CARTESIAN_POINT('',(6.90000472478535,0.117121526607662,-17.5999980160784));
#942=CARTESIAN_POINT('',(6.90983127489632,0.234307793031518,-17.5983820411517));
#943=CARTESIAN_POINT('',(6.94886279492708,0.465395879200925,-17.592091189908));
#944=CARTESIAN_POINT('',(6.97808579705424,0.579294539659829,-17.5874134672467));
#945=CARTESIAN_POINT('',(7.05500620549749,0.800430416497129,-17.5755239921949));
#946=CARTESIAN_POINT('',(7.10268873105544,0.907672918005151,-17.5683142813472));
#947=CARTESIAN_POINT('',(7.21513620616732,1.11262082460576,-17.5521543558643));
#948=CARTESIAN_POINT('',(7.27989911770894,1.21032736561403,-17.5432043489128));
#949=CARTESIAN_POINT('',(7.42530347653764,1.3943436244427,-17.5244644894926));
#950=CARTESIAN_POINT('',(7.50607135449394,1.48055280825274,-17.5146683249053));
#951=CARTESIAN_POINT('',(7.68092081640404,1.63825897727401,-17.4953887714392));
#952=CARTESIAN_POINT('',(7.77500322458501,1.70975505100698,-17.4859054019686));
#953=CARTESIAN_POINT('',(7.97449866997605,1.83640607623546,-17.468264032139));
#954=CARTESIAN_POINT('',(8.07997533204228,1.89146204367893,-17.4601141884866));
#955=CARTESIAN_POINT('',(8.29883490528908,1.98303711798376,-17.4461499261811));
#956=CARTESIAN_POINT('',(8.41221730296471,2.01955742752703,-17.4403353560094));
#957=CARTESIAN_POINT('',(8.64260579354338,2.07270865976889,-17.4317626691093));
#958=CARTESIAN_POINT('',(8.75957090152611,2.08951286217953,-17.4289779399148));
#959=CARTESIAN_POINT('',(8.99469123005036,2.10329203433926,-17.4266996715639));
#960=CARTESIAN_POINT('',(9.11284636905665,2.10026835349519,-17.4272059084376));
#961=CARTESIAN_POINT('',(9.34575842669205,2.07461882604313,-17.4314280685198));
#962=CARTESIAN_POINT('',(9.46053740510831,2.05218729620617,-17.4351121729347));
#963=CARTESIAN_POINT('',(9.68468044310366,1.98866361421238,-17.44522517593));
#964=CARTESIAN_POINT('',(9.79404432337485,1.94757084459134,-17.451654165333));
#965=CARTESIAN_POINT('',(10.0048363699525,1.84769311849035,-17.4665670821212));
#966=CARTESIAN_POINT('',(10.1062254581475,1.78882714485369,-17.4750603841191));
#967=CARTESIAN_POINT('',(10.2977604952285,1.6551315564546,-17.4931383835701));
#968=CARTESIAN_POINT('',(10.387905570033,1.58030070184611,-17.5027231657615));
#969=CARTESIAN_POINT('',(10.5555187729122,1.41573919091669,-17.5220441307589));
#970=CARTESIAN_POINT('',(10.6328231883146,1.32584174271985,-17.5317807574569));
#971=CARTESIAN_POINT('',(10.7712743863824,1.13426388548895,-17.5502027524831));
#972=CARTESIAN_POINT('',(10.8324210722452,1.03258340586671,-17.5588881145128));
#973=CARTESIAN_POINT('',(10.9368346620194,0.820174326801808,-17.5742406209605));
#974=CARTESIAN_POINT('',(10.9800874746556,0.709438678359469,-17.5809061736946));
#975=CARTESIAN_POINT('',(11.0473355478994,0.482141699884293,-17.5914551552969));
#976=CARTESIAN_POINT('',(11.071332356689,0.365580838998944,-17.595338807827));
#977=CARTESIAN_POINT('',(11.0991661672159,0.131353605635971,-17.5998564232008));
#978=CARTESIAN_POINT('',(11.1032279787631,0.0137146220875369,-17.6005266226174));
#979=CARTESIAN_POINT('',(11.0916753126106,-0.220563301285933,-17.5986409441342));
#980=CARTESIAN_POINT('',(11.0760615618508,-0.337202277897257,-17.5960851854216));
#981=CARTESIAN_POINT('',(11.0257879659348,-0.565477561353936,-17.5880571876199));
#982=CARTESIAN_POINT('',(10.9912390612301,-0.677138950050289,-17.5826019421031));
#983=CARTESIAN_POINT('',(10.904193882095,-0.893084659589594,-17.5693842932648));
#984=CARTESIAN_POINT('',(10.8516966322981,-0.997368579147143,-17.5616217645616));
#985=CARTESIAN_POINT('',(10.7297275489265,-1.19657805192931,-17.5445610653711));
#986=CARTESIAN_POINT('',(10.6601148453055,-1.29141626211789,-17.5352503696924));
#987=CARTESIAN_POINT('',(10.506085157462,-1.46814485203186,-17.516164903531));
#988=CARTESIAN_POINT('',(10.4216671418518,-1.55003432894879,-17.5063901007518));
#989=CARTESIAN_POINT('',(10.2394163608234,-1.69937114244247,-17.4873613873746));
#990=CARTESIAN_POINT('',(10.1414585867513,-1.76666682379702,-17.4781136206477));
#991=CARTESIAN_POINT('',(9.93549693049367,-1.88384763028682,-17.4612995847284));
#992=CARTESIAN_POINT('',(9.82749335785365,-1.93373329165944,-17.4537332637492));
#993=CARTESIAN_POINT('',(9.60493566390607,-2.01444949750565,-17.4411845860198));
#994=CARTESIAN_POINT('',(9.49040984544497,-2.04535640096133,-17.4361918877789));
#995=CARTESIAN_POINT('',(9.25770419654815,-2.08747862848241,-17.4293294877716));
#996=CARTESIAN_POINT('',(9.1395246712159,-2.09869559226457,-17.4274595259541));
#997=CARTESIAN_POINT('',(8.90438008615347,-2.10107515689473,-17.4270652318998));
#998=CARTESIAN_POINT('',(8.78741743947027,-2.09247641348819,-17.4285010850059));
#999=CARTESIAN_POINT('',(8.55662666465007,-2.05598376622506,-17.4344695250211));
#1000=CARTESIAN_POINT('',(8.44279852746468,-2.02808991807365,-17.4390021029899));
#1001=CARTESIAN_POINT('',(8.22159494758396,-1.95388888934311,-17.4506383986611));
#1002=CARTESIAN_POINT('',(8.11421271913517,-1.9076014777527,-17.4577393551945));
#1003=CARTESIAN_POINT('',(7.90869941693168,-1.79795159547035,-17.4737151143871));
#1004=CARTESIAN_POINT('',(7.81056877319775,-1.73458833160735,-17.4825899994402));
#1005=CARTESIAN_POINT('',(7.62513705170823,-1.59173052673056,-17.5012402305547));
#1006=CARTESIAN_POINT('',(7.53797232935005,-1.51206016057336,-17.5110246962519));
#1007=CARTESIAN_POINT('',(7.37816689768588,-1.33922073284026,-17.530318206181));
#1008=CARTESIAN_POINT('',(7.30552954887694,-1.24604855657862,-17.539827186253));
#1009=CARTESIAN_POINT('',(7.17640344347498,-1.0481190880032,-17.557571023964));
#1010=CARTESIAN_POINT('',(7.12002468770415,-0.943289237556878,-17.5657970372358));
#1011=CARTESIAN_POINT('',(7.02576289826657,-0.725556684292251,-17.5799619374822));
#1012=CARTESIAN_POINT('',(6.98786129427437,-0.612662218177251,-17.5859031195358));
#1013=CARTESIAN_POINT('',(6.93993192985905,-0.416095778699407,-17.5935203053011));
#1014=CARTESIAN_POINT('',(6.92498121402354,-0.333618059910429,-17.5959373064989));
#1015=CARTESIAN_POINT('',(6.90501364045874,-0.167437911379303,-17.599177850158));
#1016=CARTESIAN_POINT('',(6.89999662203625,-0.0837355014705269,-17.6000014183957));
#1017=CARTESIAN_POINT('',(6.9,0.,-17.6));
#1018=B_SPLINE_CURVE_WITH_KNOTS('',3,(#940,#941,#942,#943,#944,#945,#946,#947,#948,#949,#950,
#951,#952,#953,#954,#955,#956,#957,#958,#959,#960,#961,#962,#963,#964,#965,#966,#967,#968,#969,
#970,#971,#972,#973,#974,#975,#976,#977,#978,#979,#980,#981,#982,#983,#984,#985,#986,#987,#988,
#989,#990,#991,#992,#993,#994,#995,#996,#997,#998,#999,#1000,#1001,#1002,#1003,#1004,#1005,
#1006,#1007,#1008,#1009,#1010,#1011,#1012,#1013,#1014,#1015,#1016,#1017),.UNSPECIFIED.,.T.,.F.,
(4,2,2,2,2,2,2,2,2,2,2,2,2,2,2,2,2,2,2,2,2,2,2,2,2,2,2,2,2,2,2,2,2,2,2,2,2,2,4),(0.,
0.351058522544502,0.702443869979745,1.05354654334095,1.40460734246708,1.75856061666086,
2.11253581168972,2.46860116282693,2.82464340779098,3.17753247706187,3.53039753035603,
3.87976995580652,4.22915394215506,4.58015523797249,4.93118380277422,5.28639177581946,
5.64160187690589,5.99709117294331,6.35255188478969,6.70399465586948,7.05542444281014,
7.40481689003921,7.75422832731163,8.10661799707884,8.45903222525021,8.81494965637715,
9.17085612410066,9.52532109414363,9.87975654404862,10.2299456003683,10.5801336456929,
10.9299463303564,11.2797752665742,11.6335961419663,11.9874987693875,12.343742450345,
12.6996273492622,12.9506190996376,13.2016067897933),.UNSPECIFIED.);
#1019=CARTESIAN_POINT('',(6.9,0.,-17.6));
#1020=VERTEX_POINT('',#1019);
#1021=EDGE_CURVE('E549',#1020,#1020,#1018,.T.);
#1022=ORIENTED_EDGE('',*,*,#1021,.T.);
#1023=EDGE_LOOP('',(#1022));
#1024=FACE_BOUND('',#1023,.T.);
#1025=CARTESIAN_POINT('',(31.9,0.,-17.6));
#1026=CARTESIAN_POINT('',(31.9000047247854,0.117121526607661,-17.5999980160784));
#1027=CARTESIAN_POINT('',(31.9098312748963,0.234307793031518,-17.5983820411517));
#1028=CARTESIAN_POINT('',(31.9488627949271,0.465395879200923,-17.592091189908));
#1029=CARTESIAN_POINT('',(31.9780857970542,0.579294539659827,-17.5874134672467));
#1030=CARTESIAN_POINT('',(32.0550062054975,0.800430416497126,-17.5755239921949));
#1031=CARTESIAN_POINT('',(32.1026887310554,0.907672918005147,-17.5683142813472));
#1032=CARTESIAN_POINT('',(32.2151362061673,1.11262082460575,-17.5521543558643));
#1033=CARTESIAN_POINT('',(32.2798991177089,1.21032736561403,-17.5432043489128));
#1034=CARTESIAN_POINT('',(32.4253034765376,1.3943436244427,-17.5244644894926));
#1035=CARTESIAN_POINT('',(32.506071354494,1.48055280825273,-17.5146683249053));
#1036=CARTESIAN_POINT('',(32.6809208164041,1.63825897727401,-17.4953887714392));
#1037=CARTESIAN_POINT('',(32.775003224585,1.70975505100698,-17.4859054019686));
#1038=CARTESIAN_POINT('',(32.9744986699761,1.83640607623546,-17.468264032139));
#1039=CARTESIAN_POINT('',(33.0799753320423,1.89146204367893,-17.4601141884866));
#1040=CARTESIAN_POINT('',(33.2988349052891,1.98303711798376,-17.4461499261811));
#1041=CARTESIAN_POINT('',(33.4122173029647,2.01955742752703,-17.4403353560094));
#1042=CARTESIAN_POINT('',(33.6426057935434,2.07270865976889,-17.4317626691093));
#1043=CARTESIAN_POINT('',(33.7595709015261,2.08951286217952,-17.4289779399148));
#1044=CARTESIAN_POINT('',(33.9946912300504,2.10329203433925,-17.4266996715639));
#1045=CARTESIAN_POINT('',(34.1128463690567,2.10026835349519,-17.4272059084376));
#1046=CARTESIAN_POINT('',(34.3457584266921,2.07461882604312,-17.4314280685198));
#1047=CARTESIAN_POINT('',(34.4605374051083,2.05218729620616,-17.4351121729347));
#1048=CARTESIAN_POINT('',(34.6846804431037,1.98866361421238,-17.44522517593));
#1049=CARTESIAN_POINT('',(34.7940443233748,1.94757084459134,-17.451654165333));
#1050=CARTESIAN_POINT('',(35.0048363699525,1.84769311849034,-17.4665670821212));
#1051=CARTESIAN_POINT('',(35.1062254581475,1.78882714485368,-17.4750603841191));
#1052=CARTESIAN_POINT('',(35.2977604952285,1.65513155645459,-17.4931383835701));
#1053=CARTESIAN_POINT('',(35.387905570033,1.5803007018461,-17.5027231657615));
#1054=CARTESIAN_POINT('',(35.5555187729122,1.41573919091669,-17.5220441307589));
#1055=CARTESIAN_POINT('',(35.6328231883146,1.32584174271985,-17.5317807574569));
#1056=CARTESIAN_POINT('',(35.7712743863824,1.13426388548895,-17.5502027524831));
#1057=CARTESIAN_POINT('',(35.8324210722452,1.03258340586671,-17.5588881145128));
#1058=CARTESIAN_POINT('',(35.9368346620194,0.820174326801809,-17.5742406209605));
#1059=CARTESIAN_POINT('',(35.9800874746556,0.709438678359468,-17.5809061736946));
#1060=CARTESIAN_POINT('',(36.0473355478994,0.482141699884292,-17.5914551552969));
#1061=CARTESIAN_POINT('',(36.071332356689,0.365580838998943,-17.595338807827));
#1062=CARTESIAN_POINT('',(36.0991661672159,0.131353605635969,-17.5998564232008));
#1063=CARTESIAN_POINT('',(36.1032279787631,0.0137146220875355,-17.6005266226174));
#1064=CARTESIAN_POINT('',(36.0916753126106,-0.220563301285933,-17.5986409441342));
#1065=CARTESIAN_POINT('',(36.0760615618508,-0.337202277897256,-17.5960851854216));
#1066=CARTESIAN_POINT('',(36.0257879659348,-0.565477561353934,-17.5880571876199));
#1067=CARTESIAN_POINT('',(35.9912390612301,-0.677138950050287,-17.5826019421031));
#1068=CARTESIAN_POINT('',(35.904193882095,-0.893084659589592,-17.5693842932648));
#1069=CARTESIAN_POINT('',(35.8516966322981,-0.997368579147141,-17.5616217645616));
#1070=CARTESIAN_POINT('',(35.7297275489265,-1.1965780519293,-17.5445610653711));
#1071=CARTESIAN_POINT('',(35.6601148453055,-1.29141626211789,-17.5352503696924));
#1072=CARTESIAN_POINT('',(35.506085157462,-1.46814485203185,-17.516164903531));
#1073=CARTESIAN_POINT('',(35.4216671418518,-1.55003432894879,-17.5063901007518));
#1074=CARTESIAN_POINT('',(35.2394163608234,-1.69937114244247,-17.4873613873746));
#1075=CARTESIAN_POINT('',(35.1414585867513,-1.76666682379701,-17.4781136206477));
#1076=CARTESIAN_POINT('',(34.9354969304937,-1.88384763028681,-17.4612995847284));
#1077=CARTESIAN_POINT('',(34.8274933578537,-1.93373329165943,-17.4537332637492));
#1078=CARTESIAN_POINT('',(34.6049356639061,-2.01444949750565,-17.4411845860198));
#1079=CARTESIAN_POINT('',(34.490409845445,-2.04535640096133,-17.4361918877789));
#1080=CARTESIAN_POINT('',(34.2577041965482,-2.0874786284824,-17.4293294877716));
#1081=CARTESIAN_POINT('',(34.1395246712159,-2.09869559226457,-17.4274595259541));
#1082=CARTESIAN_POINT('',(33.9043800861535,-2.10107515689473,-17.4270652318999));
#1083=CARTESIAN_POINT('',(33.7874174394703,-2.09247641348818,-17.4285010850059));
#1084=CARTESIAN_POINT('',(33.5566266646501,-2.05598376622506,-17.4344695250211));
#1085=CARTESIAN_POINT('',(33.4427985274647,-2.02808991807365,-17.4390021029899));
#1086=CARTESIAN_POINT('',(33.221594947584,-1.9538888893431,-17.4506383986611));
#1087=CARTESIAN_POINT('',(33.1142127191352,-1.90760147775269,-17.4577393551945));
#1088=CARTESIAN_POINT('',(32.9086994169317,-1.79795159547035,-17.4737151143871));
#1089=CARTESIAN_POINT('',(32.8105687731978,-1.73458833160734,-17.4825899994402));
#1090=CARTESIAN_POINT('',(32.6251370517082,-1.59173052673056,-17.5012402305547));
#1091=CARTESIAN_POINT('',(32.5379723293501,-1.51206016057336,-17.5110246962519));
#1092=CARTESIAN_POINT('',(32.3781668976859,-1.33922073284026,-17.530318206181));
#1093=CARTESIAN_POINT('',(32.3055295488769,-1.24604855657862,-17.539827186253));
#1094=CARTESIAN_POINT('',(32.176403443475,-1.0481190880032,-17.557571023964));
#1095=CARTESIAN_POINT('',(32.1200246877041,-0.943289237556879,-17.5657970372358));
#1096=CARTESIAN_POINT('',(32.0257628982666,-0.725556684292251,-17.5799619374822));
#1097=CARTESIAN_POINT('',(31.9878612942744,-0.61266221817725,-17.5859031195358));
#1098=CARTESIAN_POINT('',(31.9399319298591,-0.416095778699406,-17.5935203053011));
#1099=CARTESIAN_POINT('',(31.9249812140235,-0.333618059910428,-17.5959373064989));
#1100=CARTESIAN_POINT('',(31.9050136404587,-0.167437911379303,-17.599177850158));
#1101=CARTESIAN_POINT('',(31.8999966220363,-0.0837355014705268,-17.6000014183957));
#1102=CARTESIAN_POINT('',(31.9,0.,-17.6));
#1103=B_SPLINE_CURVE_WITH_KNOTS('',3,(#1025,#1026,#1027,#1028,#1029,#1030,#1031,#1032,#1033,
#1034,#1035,#1036,#1037,#1038,#1039,#1040,#1041,#1042,#1043,#1044,#1045,#1046,#1047,#1048,#1049,
#1050,#1051,#1052,#1053,#1054,#1055,#1056,#1057,#1058,#1059,#1060,#1061,#1062,#1063,#1064,#1065,
#1066,#1067,#1068,#1069,#1070,#1071,#1072,#1073,#1074,#1075,#1076,#1077,#1078,#1079,#1080,#1081,
#1082,#1083,#1084,#1085,#1086,#1087,#1088,#1089,#1090,#1091,#1092,#1093,#1094,#1095,#1096,#1097,
#1098,#1099,#1100,#1101,#1102),.UNSPECIFIED.,.T.,.F.,(4,2,2,2,2,2,2,2,2,2,2,2,2,2,2,2,2,2,2,2,2,
2,2,2,2,2,2,2,2,2,2,2,2,2,2,2,2,2,4),(0.,0.3510585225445,0.702443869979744,1.05354654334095,
1.40460734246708,1.75856061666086,2.11253581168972,2.46860116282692,2.82464340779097,
3.17753247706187,3.53039753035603,3.87976995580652,4.22915394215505,4.58015523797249,
4.93118380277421,5.28639177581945,5.64160187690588,5.9970911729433,6.35255188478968,
6.70399465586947,7.05542444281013,7.4048168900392,7.75422832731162,8.10661799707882,
8.45903222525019,8.81494965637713,9.17085612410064,9.52532109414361,9.8797565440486,
10.2299456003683,10.5801336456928,10.9299463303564,11.2797752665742,11.6335961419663,
11.9874987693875,12.343742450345,12.6996273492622,12.9506190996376,13.2016067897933),.UNSPECIFIED.);
#1104=CARTESIAN_POINT('',(31.9,0.,-17.6));
#1105=VERTEX_POINT('',#1104);
#1106=EDGE_CURVE('E542',#1105,#1105,#1103,.T.);
#1107=ORIENTED_EDGE('',*,*,#1106,.T.);
#1108=EDGE_LOOP('',(#1107));
#1109=FACE_BOUND('',#1108,.T.);
#1110=ORIENTED_EDGE('',*,*,#850,.F.);
#1111=CARTESIAN_POINT('',(43.,0.,-4.75));
#1112=DIRECTION('',(1.,0.,0.));
#1113=DIRECTION('',(0.,0.,-1.));
#1114=AXIS2_PLACEMENT_3D('',#1111,#1112,#1113);
#1115=CIRCLE('',#1114,12.85);
#1116=EDGE_CURVE('E56',#843,#875,#1115,.T.);
#1117=ORIENTED_EDGE('',*,*,#1116,.T.);
#1118=ORIENTED_EDGE('',*,*,#876,.T.);
#1119=ORIENTED_EDGE('',*,*,#307,.T.);
#1120=EDGE_LOOP('',(#1110,#1117,#1118,#1119));
#1121=FACE_BOUND('',#1120,.T.);
#1122=ADVANCED_FACE('F413',(#1024,#1109,#1121),#939,.F.);
#1123=CARTESIAN_POINT('',(9.,17.4398492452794,-23.55));
#1124=DIRECTION('',(0.,0.,1.));
#1125=DIRECTION('',(1.,0.,0.));
#1126=AXIS2_PLACEMENT_3D('',#1123,#1124,#1125);
#1127=CYLINDRICAL_SURFACE('',#1126,2.1);
#1128=CARTESIAN_POINT('',(11.1,17.4398492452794,-13.5622836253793));
#1129=CARTESIAN_POINT('',(11.1000020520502,17.5339753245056,-13.3579521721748));
#1130=CARTESIAN_POINT('',(11.0936991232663,17.6310007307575,-13.1549340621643));
#1131=CARTESIAN_POINT('',(11.0658151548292,17.8304545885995,-12.7523021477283));
#1132=CARTESIAN_POINT('',(11.0442217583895,17.932887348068,-12.5526912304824));
#1133=CARTESIAN_POINT('',(10.9976778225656,18.0896427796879,-12.2574431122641));
#1134=CARTESIAN_POINT('',(10.9798284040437,18.1423595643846,-12.1598146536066));
#1135=CARTESIAN_POINT('',(10.9388327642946,18.2486610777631,-11.966165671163));
#1136=CARTESIAN_POINT('',(10.915687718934,18.3022456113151,-11.8701447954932));
#1137=CARTESIAN_POINT('',(10.8634725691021,18.4099232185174,-11.6802521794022));
#1138=CARTESIAN_POINT('',(10.8344135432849,18.4640151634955,-11.5863767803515));
#1139=CARTESIAN_POINT('',(10.7695289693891,18.5724397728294,-11.4010877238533));
#1140=CARTESIAN_POINT('',(10.7337025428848,18.6267724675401,-11.3096743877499));
#1141=CARTESIAN_POINT('',(10.6581776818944,18.7298578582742,-11.1387823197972));
#1142=CARTESIAN_POINT('',(10.6191943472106,18.7786394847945,-11.0590073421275));
#1143=CARTESIAN_POINT('',(10.5341062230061,18.8753508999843,-10.9028544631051));
#1144=CARTESIAN_POINT('',(10.4880063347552,18.9232812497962,-10.8264742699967));
#1145=CARTESIAN_POINT('',(10.3880094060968,19.0172232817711,-10.6785547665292));
#1146=CARTESIAN_POINT('',(10.3341620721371,19.0632449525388,-10.606988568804));
#1147=CARTESIAN_POINT('',(10.2174963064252,19.1524750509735,-10.469742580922));
#1148=CARTESIAN_POINT('',(10.154691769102,19.1956876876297,-10.4040539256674));
#1149=CARTESIAN_POINT('',(10.0299363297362,19.2711491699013,-10.2904422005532));
#1150=CARTESIAN_POINT('',(9.9694495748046,19.3040470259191,-10.2413570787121));
#1151=CARTESIAN_POINT('',(9.84103161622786,19.365395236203,-10.1504574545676));
#1152=CARTESIAN_POINT('',(9.77309691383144,19.3938434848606,-10.1086463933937));
#1153=CARTESIAN_POINT('',(9.62924378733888,19.4448246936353,-10.0341232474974));
#1154=CARTESIAN_POINT('',(9.55324987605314,19.4672932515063,-10.0015100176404));
#1155=CARTESIAN_POINT('',(9.39521250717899,19.5039109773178,-9.94854182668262));
#1156=CARTESIAN_POINT('',(9.3131786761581,19.5180730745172,-9.92816781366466));
#1157=CARTESIAN_POINT('',(9.15256545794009,19.5357276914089,-9.90279685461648));
#1158=CARTESIAN_POINT('',(9.07425181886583,19.5399977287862,-9.8966791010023));
#1159=CARTESIAN_POINT('',(8.91768240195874,19.5396930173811,-9.89711591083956));
#1160=CARTESIAN_POINT('',(8.83942661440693,19.5351205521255,-9.90366720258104));
#1161=CARTESIAN_POINT('',(8.6958786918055,19.5188028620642,-9.92712105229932));
#1162=CARTESIAN_POINT('',(8.63022162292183,19.5080648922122,-9.94257080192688));
#1163=CARTESIAN_POINT('',(8.50254203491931,19.4811227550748,-9.98148684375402));
#1164=CARTESIAN_POINT('',(8.44052050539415,19.4649171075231,-10.0049553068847));
#1165=CARTESIAN_POINT('',(8.29527231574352,19.4200903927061,-10.0701998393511));
#1166=CARTESIAN_POINT('',(8.21436029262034,19.3891254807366,-10.1155108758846));
#1167=CARTESIAN_POINT('',(8.06233437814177,19.3207451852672,-10.2164984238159));
#1168=CARTESIAN_POINT('',(7.99124369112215,19.2833149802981,-10.2721987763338));
#1169=CARTESIAN_POINT('',(7.8227322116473,19.1828926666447,-10.4232212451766));
#1170=CARTESIAN_POINT('',(7.73174099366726,19.1169876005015,-10.523730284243));
#1171=CARTESIAN_POINT('',(7.56879365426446,18.9803011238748,-10.7360774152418));
#1172=CARTESIAN_POINT('',(7.49688126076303,18.9095089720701,-10.8479407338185));
#1173=CARTESIAN_POINT('',(7.37606395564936,18.7740528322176,-11.0662321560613));
#1174=CARTESIAN_POINT('',(7.32548827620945,18.7095849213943,-11.171877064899));
#1175=CARTESIAN_POINT('',(7.2349370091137,18.5803678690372,-11.387510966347));
#1176=CARTESIAN_POINT('',(7.19496979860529,18.5156185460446,-11.497503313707));
#1177=CARTESIAN_POINT('',(7.12408799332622,18.3866190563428,-11.7208071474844));
#1178=CARTESIAN_POINT('',(7.09318496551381,18.3223696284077,-11.8341226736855));
#1179=CARTESIAN_POINT('',(7.03923721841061,18.1949618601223,-12.0632408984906));
#1180=CARTESIAN_POINT('',(7.01619544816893,18.1318039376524,-12.1790445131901));
#1181=CARTESIAN_POINT('',(6.97745178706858,18.0085055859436,-12.4096864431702));
#1182=CARTESIAN_POINT('',(6.96158253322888,17.9483291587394,-12.5244778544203));
#1183=CARTESIAN_POINT('',(6.93559054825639,17.8295960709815,-12.7555493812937));
#1184=CARTESIAN_POINT('',(6.92546890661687,17.7710397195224,-12.8718297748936));
#1185=CARTESIAN_POINT('',(6.90272202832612,17.5979770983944,-13.2226392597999));
#1186=CARTESIAN_POINT('',(6.89773518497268,17.4861474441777,-13.4590054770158));
#1187=CARTESIAN_POINT('',(6.90407815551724,17.270146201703,-13.9356599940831));
#1188=CARTESIAN_POINT('',(6.91545343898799,17.1659968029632,-14.175957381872));
#1189=CARTESIAN_POINT('',(6.95163046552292,16.9660356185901,-14.6588733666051));
#1190=CARTESIAN_POINT('',(6.97642764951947,16.8702210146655,-14.9014911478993));
#1191=CARTESIAN_POINT('',(7.03160179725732,16.7039160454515,-15.3435727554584));
#1192=CARTESIAN_POINT('',(7.06010766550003,16.6320132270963,-15.5427475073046));
#1193=CARTESIAN_POINT('',(7.1236166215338,16.4938210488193,-15.9420267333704));
#1194=CARTESIAN_POINT('',(7.15862039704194,16.427532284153,-16.1421313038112));
#1195=CARTESIAN_POINT('',(7.23438557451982,16.3005170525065,-16.5431815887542));
#1196=CARTESIAN_POINT('',(7.27515139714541,16.2397949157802,-16.7441278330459));
#1197=CARTESIAN_POINT('',(7.36182253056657,16.1239433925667,-17.1465079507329));
#1198=CARTESIAN_POINT('',(7.40772758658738,16.0688137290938,-17.3479417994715));
#1199=CARTESIAN_POINT('',(7.50414651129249,15.9642238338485,-17.7506689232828));
#1200=CARTESIAN_POINT('',(7.5546498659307,15.9147512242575,-17.9519615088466));
#1201=CARTESIAN_POINT('',(7.6601340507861,15.821291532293,-18.3546648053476));
#1202=CARTESIAN_POINT('',(7.71511523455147,15.7773048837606,-18.5560755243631));
#1203=CARTESIAN_POINT('',(7.82959490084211,15.6948209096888,-18.9585540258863));
#1204=CARTESIAN_POINT('',(7.88908972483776,15.6563192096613,-19.1596219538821));
#1205=CARTESIAN_POINT('',(8.01321259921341,15.5847443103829,-19.5611191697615));
#1206=CARTESIAN_POINT('',(8.07783970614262,15.5516701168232,-19.7615485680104));
#1207=CARTESIAN_POINT('',(8.18309707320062,15.5048299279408,-20.0695635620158));
#1208=CARTESIAN_POINT('',(8.22119836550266,15.4891470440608,-20.1777238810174));
#1209=CARTESIAN_POINT('',(8.30027235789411,15.4594000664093,-20.393206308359));
#1210=CARTESIAN_POINT('',(8.34124451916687,15.4453356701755,-20.500528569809));
#1211=CARTESIAN_POINT('',(8.40831626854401,15.4247728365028,-20.6660509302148));
#1212=CARTESIAN_POINT('',(8.43288970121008,15.4176997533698,-20.7247913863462));
#1213=CARTESIAN_POINT('',(8.48390500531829,15.4040847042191,-20.8414621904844));
#1214=CARTESIAN_POINT('',(8.51034570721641,15.3975424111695,-20.8993930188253));
#1215=CARTESIAN_POINT('',(8.57428310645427,15.3831087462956,-21.0314912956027));
#1216=CARTESIAN_POINT('',(8.61270375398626,15.3754084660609,-21.1052654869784));
#1217=CARTESIAN_POINT('',(8.67629918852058,15.3648439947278,-21.2109773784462));
#1218=CARTESIAN_POINT('',(8.69809885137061,15.3615323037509,-21.2448855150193));
#1219=CARTESIAN_POINT('',(8.74489194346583,15.3552656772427,-21.3104296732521));
#1220=CARTESIAN_POINT('',(8.76987334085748,15.3523094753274,-21.342073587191));
#1221=CARTESIAN_POINT('',(8.80833471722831,15.348586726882,-21.382688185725));
#1222=CARTESIAN_POINT('',(8.8195648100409,15.3475822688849,-21.3937398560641));
#1223=CARTESIAN_POINT('',(8.84307974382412,15.3456867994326,-21.4147420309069));
#1224=CARTESIAN_POINT('',(8.85536659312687,15.3447960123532,-21.4246903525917));
#1225=CARTESIAN_POINT('',(8.88135806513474,15.3431622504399,-21.4430472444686));
#1226=CARTESIAN_POINT('',(8.895081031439,15.3424216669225,-21.4514307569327));
#1227=CARTESIAN_POINT('',(8.92384085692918,15.3411821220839,-21.4655234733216));
#1228=CARTESIAN_POINT('',(8.93887100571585,15.3406820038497,-21.4712454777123));
#1229=CARTESIAN_POINT('',(8.96461545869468,15.3401222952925,-21.4776604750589));
#1230=CARTESIAN_POINT('',(8.97506482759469,15.3399708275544,-21.4794008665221));
#1231=CARTESIAN_POINT('',(8.99610992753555,15.339826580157,-21.4810581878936));
#1232=CARTESIAN_POINT('',(9.00670558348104,15.3398337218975,-21.4809760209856));
#1233=CARTESIAN_POINT('',(9.02769837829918,15.3400056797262,-21.4790005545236));
#1234=CARTESIAN_POINT('',(9.03809586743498,15.3401701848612,-21.4771108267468));
#1235=CARTESIAN_POINT('',(9.0584674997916,15.3406385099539,-21.4717449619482));
#1236=CARTESIAN_POINT('',(9.06844117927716,15.3409424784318,-21.4682671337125));
#1237=CARTESIAN_POINT('',(9.09333263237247,15.3418690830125,-21.4577036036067));
#1238=CARTESIAN_POINT('',(9.10784901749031,15.3425746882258,-21.4496902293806));
#1239=CARTESIAN_POINT('',(9.13551073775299,15.3441802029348,-21.4315906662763));
#1240=CARTESIAN_POINT('',(9.14865150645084,15.3450807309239,-21.4214978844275));
#1241=CARTESIAN_POINT('',(9.19445860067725,15.3486021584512,-21.3823680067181));
#1242=CARTESIAN_POINT('',(9.22370196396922,15.3516170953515,-21.3494687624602));
#1243=CARTESIAN_POINT('',(9.27775820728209,15.3581248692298,-21.2802493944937));
#1244=CARTESIAN_POINT('',(9.30253597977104,15.3616211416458,-21.2439053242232));
#1245=CARTESIAN_POINT('',(9.3515282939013,15.3693178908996,-21.1658802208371));
#1246=CARTESIAN_POINT('',(9.37545811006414,15.3735537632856,-21.1240225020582));
#1247=CARTESIAN_POINT('',(9.42112015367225,15.3823766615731,-21.0391506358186));
#1248=CARTESIAN_POINT('',(9.44285029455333,15.386964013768,-20.9961354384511));
#1249=CARTESIAN_POINT('',(9.50584968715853,15.4012248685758,-20.8658463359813));
#1250=CARTESIAN_POINT('',(9.54481995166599,15.4113786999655,-20.7775175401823));
#1251=CARTESIAN_POINT('',(9.61930069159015,15.4328739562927,-20.5994778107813));
#1252=CARTESIAN_POINT('',(9.65480691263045,15.4442168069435,-20.5097653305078));
#1253=CARTESIAN_POINT('',(9.72336316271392,15.468033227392,-20.3297126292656));
#1254=CARTESIAN_POINT('',(9.75641676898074,15.4805050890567,-20.2393735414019));
#1255=CARTESIAN_POINT('',(9.85288195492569,15.5195830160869,-19.9679048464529));
#1256=CARTESIAN_POINT('',(9.91368896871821,15.5478789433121,-19.7860948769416));
#1257=CARTESIAN_POINT('',(10.0306039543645,15.6089543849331,-19.4216985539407));
#1258=CARTESIAN_POINT('',(10.0867109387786,15.6417348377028,-19.2391120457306));
#1259=CARTESIAN_POINT('',(10.1950426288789,15.7118325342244,-18.873390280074));
#1260=CARTESIAN_POINT('',(10.2472621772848,15.7491556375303,-18.6902546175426));
#1261=CARTESIAN_POINT('',(10.3479911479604,15.8283223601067,-18.3239607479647));
#1262=CARTESIAN_POINT('',(10.396500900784,15.8701655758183,-18.1408025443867));
#1263=CARTESIAN_POINT('',(10.4896375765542,15.9582701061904,-17.7751819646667));
#1264=CARTESIAN_POINT('',(10.5342758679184,16.0045175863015,-17.5927191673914));
#1265=CARTESIAN_POINT('',(10.6196170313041,16.1015624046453,-17.2280878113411));
#1266=CARTESIAN_POINT('',(10.6603197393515,16.1523599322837,-17.0459192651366));
#1267=CARTESIAN_POINT('',(10.7759939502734,16.3115418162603,-16.5003419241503));
#1268=CARTESIAN_POINT('',(10.844623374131,16.4268011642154,-16.1375047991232));
#1269=CARTESIAN_POINT('',(10.9327152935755,16.6154620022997,-15.5897451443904));
#1270=CARTESIAN_POINT('',(10.9598990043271,16.682127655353,-15.4036959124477));
#1271=CARTESIAN_POINT('',(11.0078818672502,16.8203580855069,-15.0325625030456));
#1272=CARTESIAN_POINT('',(11.0286806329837,16.8919231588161,-14.8474783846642));
#1273=CARTESIAN_POINT('',(11.0630086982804,17.0401053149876,-14.4780545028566));
#1274=CARTESIAN_POINT('',(11.0765177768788,17.1167357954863,-14.2937182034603));
#1275=CARTESIAN_POINT('',(11.0950121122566,17.2747635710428,-13.9266698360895));
#1276=CARTESIAN_POINT('',(11.0999981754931,17.3561604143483,-13.7439576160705));
#1277=CARTESIAN_POINT('',(11.1,17.4398492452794,-13.5622836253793));
#1278=B_SPLINE_CURVE_WITH_KNOTS('',3,(#1128,#1129,#1130,#1131,#1132,#1133,#1134,#1135,#1136,
#1137,#1138,#1139,#1140,#1141,#1142,#1143,#1144,#1145,#1146,#1147,#1148,#1149,#1150,#1151,#1152,
#1153,#1154,#1155,#1156,#1157,#1158,#1159,#1160,#1161,#1162,#1163,#1164,#1165,#1166,#1167,#1168,
#1169,#1170,#1171,#1172,#1173,#1174,#1175,#1176,#1177,#1178,#1179,#1180,#1181,#1182,#1183,#1184,
#1185,#1186,#1187,#1188,#1189,#1190,#1191,#1192,#1193,#1194,#1195,#1196,#1197,#1198,#1199,#1200,
#1201,#1202,#1203,#1204,#1205,#1206,#1207,#1208,#1209,#1210,#1211,#1212,#1213,#1214,#1215,#1216,
#1217,#1218,#1219,#1220,#1221,#1222,#1223,#1224,#1225,#1226,#1227,#1228,#1229,#1230,#1231,#1232,
#1233,#1234,#1235,#1236,#1237,#1238,#1239,#1240,#1241,#1242,#1243,#1244,#1245,#1246,#1247,#1248,
#1249,#1250,#1251,#1252,#1253,#1254,#1255,#1256,#1257,#1258,#1259,#1260,#1261,#1262,#1263,#1264,
#1265,#1266,#1267,#1268,#1269,#1270,#1271,#1272,#1273,#1274,#1275,#1276,#1277),.UNSPECIFIED.,
.T.,.F.,(4,2,2,2,2,2,2,2,2,2,2,2,2,2,2,2,2,2,2,2,2,2,2,2,2,2,2,2,2,2,2,2,2,2,2,2,2,2,2,2,2,2,2,
2,2,2,2,2,2,2,2,2,2,2,2,2,2,2,2,2,2,2,2,2,2,2,2,2,2,2,2,2,2,2,4),(0.,0.674811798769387,
1.35016956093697,1.68719394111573,2.02414355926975,2.36046768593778,2.69683549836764,
3.00050034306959,3.30395697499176,3.60554697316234,3.90667413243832,4.15973166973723,
4.41290859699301,4.66871102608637,4.92411422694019,5.15864048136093,5.39310617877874,
5.59716084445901,5.80127079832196,6.09292564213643,6.38525819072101,6.8349728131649,
7.28570942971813,7.68622338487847,8.08705267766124,8.48839127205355,8.88988025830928,
9.28144434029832,9.67308262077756,10.4568080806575,11.2427156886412,12.0283565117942,
12.6691787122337,13.3100687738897,13.95145322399,14.5928058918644,15.2327272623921,
15.8726992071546,16.5121578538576,17.1514992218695,17.4986940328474,17.8458238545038,
18.0379848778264,18.2300265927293,18.4801997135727,18.6014707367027,18.7222960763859,
18.7696082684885,18.8170124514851,18.8651205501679,18.9129948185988,18.9446337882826,
18.9762570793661,19.0078180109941,19.0394126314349,19.0889127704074,19.1385723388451,
19.2698868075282,19.402192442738,19.5472565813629,19.6924570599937,19.9835106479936,
20.2749173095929,20.565890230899,21.1470931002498,21.7284177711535,22.3105004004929,
22.8925311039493,23.4727903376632,24.0530737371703,25.2125080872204,25.8108619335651,
26.4092519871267,27.0092935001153,27.6092782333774),.UNSPECIFIED.);
#1279=CARTESIAN_POINT('',(9.49587299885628,15.3992341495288,-20.8849274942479));
#1280=VERTEX_POINT('',#1279);
#1281=CARTESIAN_POINT('',(8.5041270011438,15.3992341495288,-20.884927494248));
#1282=VERTEX_POINT('',#1281);
#1283=EDGE_CURVE('E732',#1280,#1282,#1278,.T.);
#1284=ORIENTED_EDGE('',*,*,#1283,.F.);
#1285=CARTESIAN_POINT('',(9.49587299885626,15.3992341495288,-20.8849274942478));
#1286=CARTESIAN_POINT('',(9.48245781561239,15.39598395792,-20.9139661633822));
#1287=CARTESIAN_POINT('',(9.46708666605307,15.3923794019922,-20.9421179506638));
#1288=CARTESIAN_POINT('',(9.43240526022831,15.3847693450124,-20.9960265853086));
#1289=CARTESIAN_POINT('',(9.41307447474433,15.3807618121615,-21.0217698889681));
#1290=CARTESIAN_POINT('',(9.37052316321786,15.3726823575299,-21.0699914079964));
#1291=CARTESIAN_POINT('',(9.34729046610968,15.3686102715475,-21.0924589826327));
#1292=CARTESIAN_POINT('',(9.29731380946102,15.3608490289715,-21.1330962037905));
#1293=CARTESIAN_POINT('',(9.2705761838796,15.3571592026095,-21.1512734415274));
#1294=CARTESIAN_POINT('',(9.21426063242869,15.3506172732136,-21.1824116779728));
#1295=CARTESIAN_POINT('',(9.18469622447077,15.3477614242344,-21.1953961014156));
#1296=CARTESIAN_POINT('',(9.12353398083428,15.3432625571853,-21.2154940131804));
#1297=CARTESIAN_POINT('',(9.09193696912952,15.3416190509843,-21.2226098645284));
#1298=CARTESIAN_POINT('',(9.03205675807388,15.3399081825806,-21.2299991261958));
#1299=CARTESIAN_POINT('',(9.00387079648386,15.339665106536,-21.2310356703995));
#1300=CARTESIAN_POINT('',(8.94775834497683,15.3403119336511,-21.2282551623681));
#1301=CARTESIAN_POINT('',(8.91983177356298,15.341201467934,-21.224439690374));
#1302=CARTESIAN_POINT('',(8.8662741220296,15.3439469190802,-21.2124231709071));
#1303=CARTESIAN_POINT('',(8.84059600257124,15.3457593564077,-21.2044190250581));
#1304=CARTESIAN_POINT('',(8.79088550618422,15.3501377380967,-21.1845125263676));
#1305=CARTESIAN_POINT('',(8.76685275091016,15.3527035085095,-21.1726110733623));
#1306=CARTESIAN_POINT('',(8.71962801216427,15.3585060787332,-21.1446196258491));
#1307=CARTESIAN_POINT('',(8.69655581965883,15.3617721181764,-21.1283345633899));
#1308=CARTESIAN_POINT('',(8.65309068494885,15.3685842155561,-21.0925134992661));
#1309=CARTESIAN_POINT('',(8.632702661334,15.372130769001,-21.072971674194));
#1310=CARTESIAN_POINT('',(8.59128033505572,15.3798792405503,-21.02731586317));
#1311=CARTESIAN_POINT('',(8.5708484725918,15.3840786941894,-21.0006573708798));
#1312=CARTESIAN_POINT('',(8.53428160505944,15.3920594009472,-20.9446201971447));
#1313=CARTESIAN_POINT('',(8.51813054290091,15.3958421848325,-20.915252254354));
#1314=CARTESIAN_POINT('',(8.50412700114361,15.3992341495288,-20.884927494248));
#1315=B_SPLINE_CURVE_WITH_KNOTS('',3,(#1285,#1286,#1287,#1288,#1289,#1290,#1291,#1292,#1293,
#1294,#1295,#1296,#1297,#1298,#1299,#1300,#1301,#1302,#1303,#1304,#1305,#1306,#1307,#1308,#1309,
#1310,#1311,#1312,#1313,#1314),.UNSPECIFIED.,.F.,.F.,(4,2,2,2,2,2,2,2,2,2,2,2,2,2,4),(0.,
0.0964633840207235,0.193440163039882,0.290725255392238,0.387836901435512,0.48450539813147,
0.581134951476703,0.665321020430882,0.749479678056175,0.82999689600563,0.910495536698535,
0.995441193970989,1.08054040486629,1.18167877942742,1.28243224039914),.UNSPECIFIED.);
#1316=EDGE_CURVE('E878',#1280,#1282,#1315,.T.);
#1317=ORIENTED_EDGE('',*,*,#1316,.T.);
#1318=EDGE_LOOP('',(#1284,#1317));
#1319=FACE_BOUND('',#1318,.T.);
#1320=CARTESIAN_POINT('',(9.,17.4398492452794,-5.));
#1321=DIRECTION('',(0.,0.,1.));
#1322=DIRECTION('',(1.,0.,0.));
#1323=AXIS2_PLACEMENT_3D('',#1320,#1321,#1322);
#1324=CIRCLE('',#1323,2.1);
#1325=CARTESIAN_POINT('',(11.1,17.4398492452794,-5.));
#1326=VERTEX_POINT('',#1325);
#1327=EDGE_CURVE('E668',#1326,#1326,#1324,.F.);
#1328=ORIENTED_EDGE('',*,*,#1327,.F.);
#1329=EDGE_LOOP('',(#1328));
#1330=FACE_BOUND('',#1329,.T.);
#1331=ADVANCED_FACE('F377',(#1319,#1330),#1127,.F.);
#1332=CARTESIAN_POINT('',(34.,-17.4398492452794,-23.55));
#1333=DIRECTION('',(0.,0.,1.));
#1334=DIRECTION('',(1.,0.,0.));
#1335=AXIS2_PLACEMENT_3D('',#1332,#1333,#1334);
#1336=CYLINDRICAL_SURFACE('',#1335,2.1);
#1337=CARTESIAN_POINT('',(36.1,-17.4398492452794,-13.5622836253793));
#1338=CARTESIAN_POINT('',(36.1000008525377,-17.3658483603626,-13.722927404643));
#1339=CARTESIAN_POINT('',(36.0960990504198,-17.2936338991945,-13.8843943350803));
#1340=CARTESIAN_POINT('',(36.0815068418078,-17.1529260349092,-14.2086150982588));
#1341=CARTESIAN_POINT('',(36.0708163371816,-17.0844326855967,-14.3713689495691));
#1342=CARTESIAN_POINT('',(36.029819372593,-16.8845150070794,-14.8615299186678));
#1343=CARTESIAN_POINT('',(35.9905906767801,-16.7587866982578,-15.1905461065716));
#1344=CARTESIAN_POINT('',(35.8930337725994,-16.5217050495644,-15.8543370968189));
#1345=CARTESIAN_POINT('',(35.8345289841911,-16.4104984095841,-16.1891369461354));
#1346=CARTESIAN_POINT('',(35.7021907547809,-16.2038935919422,-16.8600952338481));
#1347=CARTESIAN_POINT('',(35.6283767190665,-16.1084756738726,-17.1962514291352));
#1348=CARTESIAN_POINT('',(35.5119327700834,-15.9814599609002,-17.6838746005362));
#1349=CARTESIAN_POINT('',(35.4745357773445,-15.9436706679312,-17.8350281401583));
#1350=CARTESIAN_POINT('',(35.3971827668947,-15.8711897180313,-18.1374458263));
#1351=CARTESIAN_POINT('',(35.3572264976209,-15.836498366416,-18.2887099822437));
#1352=CARTESIAN_POINT('',(35.2746598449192,-15.7701015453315,-18.5916921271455));
#1353=CARTESIAN_POINT('',(35.2320416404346,-15.7384056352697,-18.7434100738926));
#1354=CARTESIAN_POINT('',(35.1441781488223,-15.6781180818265,-19.0466424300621));
#1355=CARTESIAN_POINT('',(35.0989338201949,-15.6495253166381,-19.1981568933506));
#1356=CARTESIAN_POINT('',(35.0061530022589,-15.5958080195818,-19.4986684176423));
#1357=CARTESIAN_POINT('',(34.9586583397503,-15.5706398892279,-19.6476705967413));
#1358=CARTESIAN_POINT('',(34.860074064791,-15.5232677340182,-19.9451922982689));
#1359=CARTESIAN_POINT('',(34.8089798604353,-15.5010676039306,-20.0937109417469));
#1360=CARTESIAN_POINT('',(34.7286194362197,-15.470096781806,-20.3150116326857));
#1361=CARTESIAN_POINT('',(34.7012906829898,-15.460184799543,-20.3883384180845));
#1362=CARTESIAN_POINT('',(34.6449603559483,-15.4411210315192,-20.5344435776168));
#1363=CARTESIAN_POINT('',(34.6159589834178,-15.4319691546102,-20.6072220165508));
#1364=CARTESIAN_POINT('',(34.5556902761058,-15.4144629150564,-20.7517519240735));
#1365=CARTESIAN_POINT('',(34.5244277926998,-15.4061069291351,-20.823505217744));
#1366=CARTESIAN_POINT('',(34.458446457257,-15.3902157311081,-20.9654832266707));
#1367=CARTESIAN_POINT('',(34.4237308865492,-15.3826797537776,-21.0357093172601));
#1368=CARTESIAN_POINT('',(34.3702244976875,-15.3726814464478,-21.1327796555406));
#1369=CARTESIAN_POINT('',(34.3539892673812,-15.369828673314,-21.1609832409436));
#1370=CARTESIAN_POINT('',(34.3199850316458,-15.3642988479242,-21.2166155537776));
#1371=CARTESIAN_POINT('',(34.3022111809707,-15.3616224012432,-21.2440414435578));
#1372=CARTESIAN_POINT('',(34.2637339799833,-15.3563808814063,-21.2986866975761));
#1373=CARTESIAN_POINT('',(34.2429337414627,-15.3538265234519,-21.3258390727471));
#1374=CARTESIAN_POINT('',(34.1979413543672,-15.3490754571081,-21.3772166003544));
#1375=CARTESIAN_POINT('',(34.1737692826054,-15.346876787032,-21.4014576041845));
#1376=CARTESIAN_POINT('',(34.1368609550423,-15.344289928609,-21.4303636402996));
#1377=CARTESIAN_POINT('',(34.1263718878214,-15.3436266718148,-21.4378216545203));
#1378=CARTESIAN_POINT('',(34.1045354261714,-15.3424240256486,-21.4514049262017));
#1379=CARTESIAN_POINT('',(34.0931879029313,-15.3418846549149,-21.4575299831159));
#1380=CARTESIAN_POINT('',(34.069469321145,-15.3409647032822,-21.4680106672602));
#1381=CARTESIAN_POINT('',(34.0570856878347,-15.3405865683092,-21.4723390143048));
#1382=CARTESIAN_POINT('',(34.031711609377,-15.3400507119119,-21.4784812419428));
#1383=CARTESIAN_POINT('',(34.0187229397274,-15.3398923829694,-21.4803020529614));
#1384=CARTESIAN_POINT('',(33.9942445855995,-15.3398258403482,-21.4810669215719));
#1385=CARTESIAN_POINT('',(33.9827645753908,-15.3398895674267,-21.4803337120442));
#1386=CARTESIAN_POINT('',(33.9601250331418,-15.340197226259,-21.4768016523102));
#1387=CARTESIAN_POINT('',(33.9489659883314,-15.3404414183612,-21.4739998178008));
#1388=CARTESIAN_POINT('',(33.924245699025,-15.3411701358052,-21.4656672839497));
#1389=CARTESIAN_POINT('',(33.9108718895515,-15.3417024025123,-21.4595967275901));
#1390=CARTESIAN_POINT('',(33.8852345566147,-15.3429481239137,-21.4454735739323));
#1391=CARTESIAN_POINT('',(33.8729736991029,-15.3436619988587,-21.4374163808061));
#1392=CARTESIAN_POINT('',(33.8387062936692,-15.3459300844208,-21.4119961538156));
#1393=CARTESIAN_POINT('',(33.8180482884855,-15.347655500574,-21.3928642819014));
#1394=CARTESIAN_POINT('',(33.7793503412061,-15.3513836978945,-21.352158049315));
#1395=CARTESIAN_POINT('',(33.7613207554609,-15.3533875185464,-21.3305745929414));
#1396=CARTESIAN_POINT('',(33.7104529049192,-15.3596250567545,-21.2644521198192));
#1397=CARTESIAN_POINT('',(33.6802220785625,-15.3641357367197,-21.2179614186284));
#1398=CARTESIAN_POINT('',(33.6235387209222,-15.3736729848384,-21.1227488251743));
#1399=CARTESIAN_POINT('',(33.5970976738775,-15.3787010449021,-21.07402071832));
#1400=CARTESIAN_POINT('',(33.5465595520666,-15.3892244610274,-20.9751043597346));
#1401=CARTESIAN_POINT('',(33.522474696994,-15.3947220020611,-20.9249100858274));
#1402=CARTESIAN_POINT('',(33.4760647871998,-15.4061191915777,-20.8238655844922));
#1403=CARTESIAN_POINT('',(33.4537371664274,-15.4120182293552,-20.7730164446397));
#1404=CARTESIAN_POINT('',(33.3891297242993,-15.4301636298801,-20.6209357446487));
#1405=CARTESIAN_POINT('',(33.3486623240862,-15.4429819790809,-20.5190038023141));
#1406=CARTESIAN_POINT('',(33.2707693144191,-15.4701019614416,-20.3141728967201));
#1407=CARTESIAN_POINT('',(33.2333445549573,-15.4844040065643,-20.2112736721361));
#1408=CARTESIAN_POINT('',(33.1242342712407,-15.5295413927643,-19.9015021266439));
#1409=CARTESIAN_POINT('',(33.0558096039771,-15.5625791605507,-19.6937989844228));
#1410=CARTESIAN_POINT('',(32.9248677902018,-15.6344115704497,-19.2780384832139));
#1411=CARTESIAN_POINT('',(32.8623389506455,-15.6731944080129,-19.0699826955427));
#1412=CARTESIAN_POINT('',(32.7422608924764,-15.7565681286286,-18.653728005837));
#1413=CARTESIAN_POINT('',(32.6847088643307,-15.8011556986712,-18.4455292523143));
#1414=CARTESIAN_POINT('',(32.5737410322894,-15.8967345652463,-18.0268296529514));
#1415=CARTESIAN_POINT('',(32.5203799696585,-15.9477931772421,-17.8163296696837));
#1416=CARTESIAN_POINT('',(32.4187533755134,-16.0559541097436,-17.395630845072));
#1417=CARTESIAN_POINT('',(32.3704882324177,-16.1130568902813,-17.1854320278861));
#1418=CARTESIAN_POINT('',(32.2794749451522,-16.2334117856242,-16.7653334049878));
#1419=CARTESIAN_POINT('',(32.2367329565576,-16.296670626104,-16.5554341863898));
#1420=CARTESIAN_POINT('',(32.1575044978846,-16.4293156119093,-16.1363946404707));
#1421=CARTESIAN_POINT('',(32.121017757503,-16.4987014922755,-15.9272542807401));
#1422=CARTESIAN_POINT('',(32.0551300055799,-16.6437134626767,-15.5096953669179));
#1423=CARTESIAN_POINT('',(32.0257384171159,-16.7193476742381,-15.3012781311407));
#1424=CARTESIAN_POINT('',(31.9752102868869,-16.8767664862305,-14.8857245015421));
#1425=CARTESIAN_POINT('',(31.9540747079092,-16.9585518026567,-14.6785882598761));
#1426=CARTESIAN_POINT('',(31.921487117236,-17.1280453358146,-14.266358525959));
#1427=CARTESIAN_POINT('',(31.9100193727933,-17.2157436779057,-14.0612622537));
#1428=CARTESIAN_POINT('',(31.8984749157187,-17.3969719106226,-13.6533791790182));
#1429=CARTESIAN_POINT('',(31.8983942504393,-17.4904997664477,-13.4505915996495));
#1430=CARTESIAN_POINT('',(31.9115360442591,-17.6778895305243,-13.0588311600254));
#1431=CARTESIAN_POINT('',(31.9240471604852,-17.7714659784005,-12.8696995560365));
#1432=CARTESIAN_POINT('',(31.9638682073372,-17.9630775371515,-12.4949624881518));
#1433=CARTESIAN_POINT('',(31.9911902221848,-18.0611162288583,-12.3093600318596));
#1434=CARTESIAN_POINT('',(32.0457208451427,-18.2102749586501,-12.0356682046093));
#1435=CARTESIAN_POINT('',(32.0660631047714,-18.2601702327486,-11.9455236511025));
#1436=CARTESIAN_POINT('',(32.1117883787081,-18.3605568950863,-11.7668696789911));
#1437=CARTESIAN_POINT('',(32.137170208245,-18.4110481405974,-11.6783598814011));
#1438=CARTESIAN_POINT('',(32.1935511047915,-18.5122730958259,-11.5034905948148));
#1439=CARTESIAN_POINT('',(32.2245406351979,-18.5630062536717,-11.4171277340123));
#1440=CARTESIAN_POINT('',(32.2928913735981,-18.6643975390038,-11.24694416));
#1441=CARTESIAN_POINT('',(32.3302494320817,-18.7150556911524,-11.1631222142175));
#1442=CARTESIAN_POINT('',(32.4020064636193,-18.8032241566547,-11.0191844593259));
#1443=CARTESIAN_POINT('',(32.4348256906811,-18.8408671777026,-10.9583632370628));
#1444=CARTESIAN_POINT('',(32.5049855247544,-18.9155038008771,-10.8389381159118));
#1445=CARTESIAN_POINT('',(32.5423266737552,-18.9524973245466,-10.7803344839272));
#1446=CARTESIAN_POINT('',(32.6219223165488,-19.0253483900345,-10.6659907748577));
#1447=CARTESIAN_POINT('',(32.6641677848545,-19.0612078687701,-10.6102457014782));
#1448=CARTESIAN_POINT('',(32.7540890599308,-19.1312843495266,-10.5022478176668));
#1449=CARTESIAN_POINT('',(32.8017617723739,-19.1655022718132,-10.4499930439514));
#1450=CARTESIAN_POINT('',(32.9142832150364,-19.2389275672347,-10.338751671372));
#1451=CARTESIAN_POINT('',(32.9805969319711,-19.2775598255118,-10.2808400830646));
#1452=CARTESIAN_POINT('',(33.1226964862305,-19.3494716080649,-10.1739224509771));
#1453=CARTESIAN_POINT('',(33.1984711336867,-19.38275735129,-10.1249060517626));
#1454=CARTESIAN_POINT('',(33.343838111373,-19.435901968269,-10.0471327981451));
#1455=CARTESIAN_POINT('',(33.4118057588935,-19.4571122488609,-10.0162919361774));
#1456=CARTESIAN_POINT('',(33.5529969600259,-19.4930120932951,-9.9642768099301));
#1457=CARTESIAN_POINT('',(33.6262160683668,-19.5077070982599,-9.94309447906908));
#1458=CARTESIAN_POINT('',(33.7767876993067,-19.5293458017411,-9.91195485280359));
#1459=CARTESIAN_POINT('',(33.8541680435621,-19.5362280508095,-9.9020865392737));
#1460=CARTESIAN_POINT('',(34.0097889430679,-19.541266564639,-9.89485849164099));
#1461=CARTESIAN_POINT('',(34.0880291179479,-19.5394265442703,-9.8974934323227));
#1462=CARTESIAN_POINT('',(34.2329267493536,-19.5280007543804,-9.91389845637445));
#1463=CARTESIAN_POINT('',(34.2998298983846,-19.519390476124,-9.92626634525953));
#1464=CARTESIAN_POINT('',(34.4304172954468,-19.4963373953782,-9.95949570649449));
#1465=CARTESIAN_POINT('',(34.4941003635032,-19.4818924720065,-9.98036026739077));
#1466=CARTESIAN_POINT('',(34.6389565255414,-19.4421464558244,-10.0380402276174));
#1467=CARTESIAN_POINT('',(34.7183604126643,-19.4148129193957,-10.0778867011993));
#1468=CARTESIAN_POINT('',(34.8683513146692,-19.3536316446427,-10.1678192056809));
#1469=CARTESIAN_POINT('',(34.9389197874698,-19.3197705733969,-10.2179262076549));
#1470=CARTESIAN_POINT('',(35.1046706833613,-19.2294225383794,-10.3529133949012));
#1471=CARTESIAN_POINT('',(35.1943665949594,-19.1701250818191,-10.4426026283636));
#1472=CARTESIAN_POINT('',(35.3564507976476,-19.0462380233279,-10.6331393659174));
#1473=CARTESIAN_POINT('',(35.4288004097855,-18.98163701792,-10.7340110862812));
#1474=CARTESIAN_POINT('',(35.5504819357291,-18.8584708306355,-10.9297896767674));
#1475=CARTESIAN_POINT('',(35.6015752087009,-18.8001925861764,-11.0238052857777));
#1476=CARTESIAN_POINT('',(35.6942086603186,-18.6829284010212,-11.2160667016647));
#1477=CARTESIAN_POINT('',(35.7357414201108,-18.6239419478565,-11.3143157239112));
#1478=CARTESIAN_POINT('',(35.8105985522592,-18.5059727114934,-11.5141385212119));
#1479=CARTESIAN_POINT('',(35.8439067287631,-18.4469901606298,-11.6157184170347));
#1480=CARTESIAN_POINT('',(35.9032897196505,-18.3296845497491,-11.8212808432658));
#1481=CARTESIAN_POINT('',(35.9293662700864,-18.2713613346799,-11.9252627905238));
#1482=CARTESIAN_POINT('',(35.9793229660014,-18.145306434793,-12.1540475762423));
#1483=CARTESIAN_POINT('',(36.0019620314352,-18.0777717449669,-12.2792279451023));
#1484=CARTESIAN_POINT('',(36.0396368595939,-17.9445020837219,-12.5316703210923));
#1485=CARTESIAN_POINT('',(36.0546714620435,-17.8787673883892,-12.6589326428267));
#1486=CARTESIAN_POINT('',(36.0780760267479,-17.7495286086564,-12.914785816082));
#1487=CARTESIAN_POINT('',(36.0864621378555,-17.6860194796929,-13.0433726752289));
#1488=CARTESIAN_POINT('',(36.0974243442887,-17.5612302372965,-13.3018864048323));
#1489=CARTESIAN_POINT('',(36.0999993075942,-17.4999505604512,-13.4318135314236));
#1490=CARTESIAN_POINT('',(36.1,-17.4398492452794,-13.5622836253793));
#1491=B_SPLINE_CURVE_WITH_KNOTS('',3,(#1337,#1338,#1339,#1340,#1341,#1342,#1343,#1344,#1345,
#1346,#1347,#1348,#1349,#1350,#1351,#1352,#1353,#1354,#1355,#1356,#1357,#1358,#1359,#1360,#1361,
#1362,#1363,#1364,#1365,#1366,#1367,#1368,#1369,#1370,#1371,#1372,#1373,#1374,#1375,#1376,#1377,
#1378,#1379,#1380,#1381,#1382,#1383,#1384,#1385,#1386,#1387,#1388,#1389,#1390,#1391,#1392,#1393,
#1394,#1395,#1396,#1397,#1398,#1399,#1400,#1401,#1402,#1403,#1404,#1405,#1406,#1407,#1408,#1409,
#1410,#1411,#1412,#1413,#1414,#1415,#1416,#1417,#1418,#1419,#1420,#1421,#1422,#1423,#1424,#1425,
#1426,#1427,#1428,#1429,#1430,#1431,#1432,#1433,#1434,#1435,#1436,#1437,#1438,#1439,#1440,#1441,
#1442,#1443,#1444,#1445,#1446,#1447,#1448,#1449,#1450,#1451,#1452,#1453,#1454,#1455,#1456,#1457,
#1458,#1459,#1460,#1461,#1462,#1463,#1464,#1465,#1466,#1467,#1468,#1469,#1470,#1471,#1472,#1473,
#1474,#1475,#1476,#1477,#1478,#1479,#1480,#1481,#1482,#1483,#1484,#1485,#1486,#1487,#1488,#1489,
#1490),.UNSPECIFIED.,.T.,.F.,(4,2,2,2,2,2,2,2,2,2,2,2,2,2,2,2,2,2,2,2,2,2,2,2,2,2,2,2,2,2,2,2,2,
2,2,2,2,2,2,2,2,2,2,2,2,2,2,2,2,2,2,2,2,2,2,2,2,2,2,2,2,2,2,2,2,2,2,2,2,2,2,2,2,2,2,2,4),(0.,
0.530562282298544,1.06113223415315,2.12322808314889,3.19533718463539,4.26609554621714,
4.74675171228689,5.22745519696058,5.70964432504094,6.19165855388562,6.6668072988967,
7.14257356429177,7.37919602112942,7.61579006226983,7.85189072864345,8.08776914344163,
8.18574439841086,8.28404026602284,8.38683810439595,8.48904809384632,8.52763699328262,
8.5662316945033,8.60539266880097,8.64444518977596,8.67875144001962,8.71310727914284,
8.75694890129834,8.80089291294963,8.88504830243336,8.96952679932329,9.13598218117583,
9.30293176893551,9.47070578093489,9.63823006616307,9.9693785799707,10.300619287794,
10.9638894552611,11.6258152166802,12.2873648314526,12.9564693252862,13.625624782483,
14.2955196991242,14.9653856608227,15.6361364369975,16.3069654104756,16.9767006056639,
17.6462033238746,18.2798948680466,18.9141042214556,19.2290589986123,19.5439398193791,
19.8582900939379,20.1724853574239,20.4084395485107,20.644422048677,20.8799769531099,
21.1153982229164,21.4029993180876,21.6902634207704,21.9221436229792,22.1538298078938,
22.3873259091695,22.620722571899,22.8255559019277,23.0304637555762,23.3077614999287,
23.5856317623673,24.0033478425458,24.4219868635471,24.7869962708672,25.1522879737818,
25.5182933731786,25.8842108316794,26.316020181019,26.7478953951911,27.1787183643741,
27.6096252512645),.UNSPECIFIED.);
#1492=CARTESIAN_POINT('',(33.5041270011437,-15.3992341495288,-20.8849274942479));
#1493=VERTEX_POINT('',#1492);
#1494=CARTESIAN_POINT('',(34.4958729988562,-15.3992341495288,-20.8849274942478));
#1495=VERTEX_POINT('',#1494);
#1496=EDGE_CURVE('E386',#1493,#1495,#1491,.T.);
#1497=ORIENTED_EDGE('',*,*,#1496,.F.);
#1498=CARTESIAN_POINT('',(33.5041270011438,-15.3992341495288,-20.8849274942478));
#1499=CARTESIAN_POINT('',(33.5175421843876,-15.39598395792,-20.9139661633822));
#1500=CARTESIAN_POINT('',(33.532913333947,-15.3923794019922,-20.9421179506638));
#1501=CARTESIAN_POINT('',(33.5675947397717,-15.3847693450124,-20.9960265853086));
#1502=CARTESIAN_POINT('',(33.5869255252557,-15.3807618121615,-21.0217698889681));
#1503=CARTESIAN_POINT('',(33.6294768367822,-15.3726823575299,-21.0699914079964));
#1504=CARTESIAN_POINT('',(33.6527095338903,-15.3686102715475,-21.0924589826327));
#1505=CARTESIAN_POINT('',(33.702686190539,-15.3608490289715,-21.1330962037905));
#1506=CARTESIAN_POINT('',(33.7294238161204,-15.3571592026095,-21.1512734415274));
#1507=CARTESIAN_POINT('',(33.7857393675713,-15.3506172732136,-21.1824116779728));
#1508=CARTESIAN_POINT('',(33.8153037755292,-15.3477614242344,-21.1953961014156));
#1509=CARTESIAN_POINT('',(33.8764660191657,-15.3432625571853,-21.2154940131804));
#1510=CARTESIAN_POINT('',(33.9080630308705,-15.3416190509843,-21.2226098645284));
#1511=CARTESIAN_POINT('',(33.9679432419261,-15.3399081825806,-21.2299991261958));
#1512=CARTESIAN_POINT('',(33.9961292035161,-15.339665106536,-21.2310356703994));
#1513=CARTESIAN_POINT('',(34.0522416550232,-15.3403119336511,-21.2282551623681));
#1514=CARTESIAN_POINT('',(34.080168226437,-15.341201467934,-21.224439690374));
#1515=CARTESIAN_POINT('',(34.1337258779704,-15.3439469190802,-21.2124231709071));
#1516=CARTESIAN_POINT('',(34.1594039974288,-15.3457593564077,-21.2044190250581));
#1517=CARTESIAN_POINT('',(34.2091144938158,-15.3501377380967,-21.1845125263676));
#1518=CARTESIAN_POINT('',(34.2331472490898,-15.3527035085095,-21.1726110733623));
#1519=CARTESIAN_POINT('',(34.2803719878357,-15.3585060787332,-21.144619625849));
#1520=CARTESIAN_POINT('',(34.3034441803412,-15.3617721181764,-21.1283345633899));
#1521=CARTESIAN_POINT('',(34.3469093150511,-15.3685842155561,-21.0925134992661));
#1522=CARTESIAN_POINT('',(34.367297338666,-15.372130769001,-21.0729716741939));
#1523=CARTESIAN_POINT('',(34.4087196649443,-15.3798792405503,-21.02731586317));
#1524=CARTESIAN_POINT('',(34.4291515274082,-15.3840786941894,-21.0006573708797));
#1525=CARTESIAN_POINT('',(34.4657183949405,-15.3920594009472,-20.9446201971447));
#1526=CARTESIAN_POINT('',(34.4818694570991,-15.3958421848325,-20.915252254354));
#1527=CARTESIAN_POINT('',(34.4958729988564,-15.3992341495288,-20.884927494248));
#1528=B_SPLINE_CURVE_WITH_KNOTS('',3,(#1498,#1499,#1500,#1501,#1502,#1503,#1504,#1505,#1506,
#1507,#1508,#1509,#1510,#1511,#1512,#1513,#1514,#1515,#1516,#1517,#1518,#1519,#1520,#1521,#1522,
#1523,#1524,#1525,#1526,#1527),.UNSPECIFIED.,.F.,.F.,(4,2,2,2,2,2,2,2,2,2,2,2,2,2,4),(0.,
0.0964633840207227,0.193440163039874,0.290725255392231,0.387836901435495,0.484505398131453,
0.58113495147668,0.665321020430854,0.749479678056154,0.829996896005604,0.910495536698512,
0.995441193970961,1.08054040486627,1.18167877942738,1.2824322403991),.UNSPECIFIED.);
#1529=EDGE_CURVE('E357',#1493,#1495,#1528,.T.);
#1530=ORIENTED_EDGE('',*,*,#1529,.T.);
#1531=EDGE_LOOP('',(#1497,#1530));
#1532=FACE_BOUND('',#1531,.T.);
#1533=CARTESIAN_POINT('',(34.,-17.4398492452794,-5.));
#1534=DIRECTION('',(0.,0.,1.));
#1535=DIRECTION('',(1.,0.,0.));
#1536=AXIS2_PLACEMENT_3D('',#1533,#1534,#1535);
#1537=CIRCLE('',#1536,2.1);
#1538=CARTESIAN_POINT('',(36.1,-17.4398492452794,-5.));
#1539=VERTEX_POINT('',#1538);
#1540=EDGE_CURVE('E670',#1539,#1539,#1537,.F.);
#1541=ORIENTED_EDGE('',*,*,#1540,.F.);
#1542=EDGE_LOOP('',(#1541));
#1543=FACE_BOUND('',#1542,.T.);
#1544=ADVANCED_FACE('F372',(#1532,#1543),#1336,.F.);
#1545=CARTESIAN_POINT('',(9.,-17.4398492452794,-23.55));
#1546=DIRECTION('',(0.,0.,1.));
#1547=DIRECTION('',(1.,0.,0.));
#1548=AXIS2_PLACEMENT_3D('',#1545,#1546,#1547);
#1549=CYLINDRICAL_SURFACE('',#1548,2.1);
#1550=CARTESIAN_POINT('',(11.1,-17.4398492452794,-13.5622836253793));
#1551=CARTESIAN_POINT('',(11.1000008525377,-17.3658483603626,-13.722927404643));
#1552=CARTESIAN_POINT('',(11.0960990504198,-17.2936338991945,-13.8843943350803));
#1553=CARTESIAN_POINT('',(11.0815068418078,-17.1529260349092,-14.2086150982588));
#1554=CARTESIAN_POINT('',(11.0708163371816,-17.0844326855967,-14.3713689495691));
#1555=CARTESIAN_POINT('',(11.029819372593,-16.8845150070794,-14.8615299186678));
#1556=CARTESIAN_POINT('',(10.9905906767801,-16.7587866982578,-15.1905461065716));
#1557=CARTESIAN_POINT('',(10.8930337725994,-16.5217050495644,-15.8543370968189));
#1558=CARTESIAN_POINT('',(10.8345289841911,-16.4104984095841,-16.1891369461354));
#1559=CARTESIAN_POINT('',(10.7021907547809,-16.2038935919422,-16.8600952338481));
#1560=CARTESIAN_POINT('',(10.6283767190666,-16.1084756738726,-17.1962514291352));
#1561=CARTESIAN_POINT('',(10.5119327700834,-15.9814599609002,-17.6838746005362));
#1562=CARTESIAN_POINT('',(10.4745357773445,-15.9436706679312,-17.8350281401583));
#1563=CARTESIAN_POINT('',(10.3971827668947,-15.8711897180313,-18.1374458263));
#1564=CARTESIAN_POINT('',(10.3572264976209,-15.836498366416,-18.2887099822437));
#1565=CARTESIAN_POINT('',(10.2746598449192,-15.7701015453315,-18.5916921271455));
#1566=CARTESIAN_POINT('',(10.2320416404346,-15.7384056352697,-18.7434100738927));
#1567=CARTESIAN_POINT('',(10.1441781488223,-15.6781180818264,-19.0466424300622));
#1568=CARTESIAN_POINT('',(10.0989338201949,-15.6495253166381,-19.1981568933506));
#1569=CARTESIAN_POINT('',(10.0061530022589,-15.5958080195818,-19.4986684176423));
#1570=CARTESIAN_POINT('',(9.95865833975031,-15.5706398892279,-19.6476705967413));
#1571=CARTESIAN_POINT('',(9.86007406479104,-15.5232677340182,-19.9451922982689));
#1572=CARTESIAN_POINT('',(9.80897986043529,-15.5010676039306,-20.0937109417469));
#1573=CARTESIAN_POINT('',(9.72861943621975,-15.470096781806,-20.3150116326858));
#1574=CARTESIAN_POINT('',(9.70129068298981,-15.460184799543,-20.3883384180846));
#1575=CARTESIAN_POINT('',(9.64496035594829,-15.4411210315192,-20.5344435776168));
#1576=CARTESIAN_POINT('',(9.61595898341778,-15.4319691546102,-20.6072220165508));
#1577=CARTESIAN_POINT('',(9.5556902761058,-15.4144629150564,-20.7517519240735));
#1578=CARTESIAN_POINT('',(9.52442779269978,-15.4061069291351,-20.8235052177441));
#1579=CARTESIAN_POINT('',(9.45844645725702,-15.3902157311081,-20.9654832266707));
#1580=CARTESIAN_POINT('',(9.42373088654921,-15.3826797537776,-21.0357093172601));
#1581=CARTESIAN_POINT('',(9.37022449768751,-15.3726814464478,-21.1327796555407));
#1582=CARTESIAN_POINT('',(9.35398926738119,-15.369828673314,-21.1609832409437));
#1583=CARTESIAN_POINT('',(9.31998503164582,-15.3642988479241,-21.2166155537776));
#1584=CARTESIAN_POINT('',(9.30221118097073,-15.3616224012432,-21.2440414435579));
#1585=CARTESIAN_POINT('',(9.26373397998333,-15.3563808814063,-21.2986866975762));
#1586=CARTESIAN_POINT('',(9.24293374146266,-15.3538265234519,-21.3258390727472));
#1587=CARTESIAN_POINT('',(9.19794135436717,-15.3490754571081,-21.3772166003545));
#1588=CARTESIAN_POINT('',(9.17376928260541,-15.346876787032,-21.4014576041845));
#1589=CARTESIAN_POINT('',(9.13686095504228,-15.344289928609,-21.4303636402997));
#1590=CARTESIAN_POINT('',(9.12637188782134,-15.3436266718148,-21.4378216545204));
#1591=CARTESIAN_POINT('',(9.10453542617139,-15.3424240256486,-21.4514049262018));
#1592=CARTESIAN_POINT('',(9.09318790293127,-15.3418846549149,-21.4575299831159));
#1593=CARTESIAN_POINT('',(9.0694693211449,-15.3409647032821,-21.4680106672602));
#1594=CARTESIAN_POINT('',(9.05708568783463,-15.3405865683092,-21.4723390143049));
#1595=CARTESIAN_POINT('',(9.03171160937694,-15.3400507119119,-21.4784812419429));
#1596=CARTESIAN_POINT('',(9.01872293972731,-15.3398923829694,-21.4803020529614));
#1597=CARTESIAN_POINT('',(8.9942445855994,-15.3398258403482,-21.4810669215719));
#1598=CARTESIAN_POINT('',(8.98276457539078,-15.3398895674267,-21.4803337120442));
#1599=CARTESIAN_POINT('',(8.96012503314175,-15.340197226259,-21.4768016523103));
#1600=CARTESIAN_POINT('',(8.94896598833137,-15.3404414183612,-21.4739998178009));
#1601=CARTESIAN_POINT('',(8.92424569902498,-15.3411701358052,-21.4656672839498));
#1602=CARTESIAN_POINT('',(8.91087188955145,-15.3417024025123,-21.4595967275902));
#1603=CARTESIAN_POINT('',(8.88523455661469,-15.3429481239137,-21.4454735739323));
#1604=CARTESIAN_POINT('',(8.8729736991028,-15.3436619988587,-21.4374163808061));
#1605=CARTESIAN_POINT('',(8.83870629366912,-15.3459300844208,-21.4119961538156));
#1606=CARTESIAN_POINT('',(8.81804828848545,-15.347655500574,-21.3928642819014));
#1607=CARTESIAN_POINT('',(8.77935034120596,-15.3513836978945,-21.352158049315));
#1608=CARTESIAN_POINT('',(8.76132075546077,-15.3533875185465,-21.3305745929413));
#1609=CARTESIAN_POINT('',(8.71045290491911,-15.3596250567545,-21.2644521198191));
#1610=CARTESIAN_POINT('',(8.68022207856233,-15.3641357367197,-21.2179614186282));
#1611=CARTESIAN_POINT('',(8.62353872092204,-15.3736729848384,-21.122748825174));
#1612=CARTESIAN_POINT('',(8.59709767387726,-15.3787010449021,-21.0740207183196));
#1613=CARTESIAN_POINT('',(8.54655955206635,-15.3892244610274,-20.9751043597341));
#1614=CARTESIAN_POINT('',(8.52247469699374,-15.3947220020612,-20.9249100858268));
#1615=CARTESIAN_POINT('',(8.47606478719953,-15.4061191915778,-20.8238655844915));
#1616=CARTESIAN_POINT('',(8.45373716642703,-15.4120182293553,-20.773016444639));
#1617=CARTESIAN_POINT('',(8.3891297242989,-15.4301636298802,-20.6209357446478));
#1618=CARTESIAN_POINT('',(8.34866232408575,-15.442981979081,-20.5190038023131));
#1619=CARTESIAN_POINT('',(8.27076931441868,-15.4701019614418,-20.3141728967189));
#1620=CARTESIAN_POINT('',(8.2333445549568,-15.4844040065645,-20.2112736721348));
#1621=CARTESIAN_POINT('',(8.12423427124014,-15.5295413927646,-19.9015021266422));
#1622=CARTESIAN_POINT('',(8.05580960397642,-15.562579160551,-19.6937989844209));
#1623=CARTESIAN_POINT('',(7.92486779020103,-15.6344115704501,-19.2780384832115));
#1624=CARTESIAN_POINT('',(7.86233895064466,-15.6731944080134,-19.0699826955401));
#1625=CARTESIAN_POINT('',(7.74226089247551,-15.7565681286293,-18.6537280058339));
#1626=CARTESIAN_POINT('',(7.68470886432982,-15.8011556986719,-18.445529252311));
#1627=CARTESIAN_POINT('',(7.57374103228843,-15.8967345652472,-18.0268296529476));
#1628=CARTESIAN_POINT('',(7.52037996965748,-15.9477931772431,-17.8163296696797));
#1629=CARTESIAN_POINT('',(7.41875337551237,-16.0559541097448,-17.3956308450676));
#1630=CARTESIAN_POINT('',(7.37048823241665,-16.1130568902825,-17.1854320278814));
#1631=CARTESIAN_POINT('',(7.27947494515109,-16.2334117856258,-16.7653334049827));
#1632=CARTESIAN_POINT('',(7.23673295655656,-16.2966706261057,-16.5554341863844));
#1633=CARTESIAN_POINT('',(7.15750449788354,-16.4293156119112,-16.1363946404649));
#1634=CARTESIAN_POINT('',(7.12101775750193,-16.4987014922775,-15.9272542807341));
#1635=CARTESIAN_POINT('',(7.05513000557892,-16.643713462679,-15.5096953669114));
#1636=CARTESIAN_POINT('',(7.02573841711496,-16.7193476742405,-15.301278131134));
#1637=CARTESIAN_POINT('',(6.97521028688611,-16.8767664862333,-14.8857245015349));
#1638=CARTESIAN_POINT('',(6.95407470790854,-16.9585518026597,-14.6785882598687));
#1639=CARTESIAN_POINT('',(6.92148711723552,-17.1280453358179,-14.2663585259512));
#1640=CARTESIAN_POINT('',(6.91001937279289,-17.2157436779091,-14.061262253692));
#1641=CARTESIAN_POINT('',(6.89847491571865,-17.3969719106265,-13.6533791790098));
#1642=CARTESIAN_POINT('',(6.8983942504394,-17.4904997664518,-13.4505915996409));
#1643=CARTESIAN_POINT('',(6.91153604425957,-17.6778895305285,-13.0588311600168));
#1644=CARTESIAN_POINT('',(6.92404716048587,-17.7714659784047,-12.8696995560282));
#1645=CARTESIAN_POINT('',(6.96386820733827,-17.9630775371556,-12.4949624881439));
#1646=CARTESIAN_POINT('',(6.99119022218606,-18.0611162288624,-12.3093600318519));
#1647=CARTESIAN_POINT('',(7.04572084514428,-18.2102749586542,-12.035668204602));
#1648=CARTESIAN_POINT('',(7.06606310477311,-18.2601702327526,-11.9455236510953));
#1649=CARTESIAN_POINT('',(7.11178837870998,-18.3605568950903,-11.7668696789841));
#1650=CARTESIAN_POINT('',(7.13717020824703,-18.4110481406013,-11.6783598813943));
#1651=CARTESIAN_POINT('',(7.1935511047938,-18.5122730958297,-11.5034905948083));
#1652=CARTESIAN_POINT('',(7.22454063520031,-18.5630062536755,-11.4171277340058));
#1653=CARTESIAN_POINT('',(7.29289137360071,-18.6643975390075,-11.2469441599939));
#1654=CARTESIAN_POINT('',(7.3302494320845,-18.715055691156,-11.1631222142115));
#1655=CARTESIAN_POINT('',(7.40200646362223,-18.8032241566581,-11.0191844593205));
#1656=CARTESIAN_POINT('',(7.434825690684,-18.8408671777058,-10.9583632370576));
#1657=CARTESIAN_POINT('',(7.50498552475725,-18.91550380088,-10.8389381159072));
#1658=CARTESIAN_POINT('',(7.54232667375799,-18.9524973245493,-10.780334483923));
#1659=CARTESIAN_POINT('',(7.6219223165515,-19.0253483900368,-10.665990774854));
#1660=CARTESIAN_POINT('',(7.66416778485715,-19.0612078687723,-10.6102457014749));
#1661=CARTESIAN_POINT('',(7.75408905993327,-19.1312843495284,-10.502247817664));
#1662=CARTESIAN_POINT('',(7.8017617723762,-19.1655022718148,-10.4499930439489));
#1663=CARTESIAN_POINT('',(7.91428321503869,-19.2389275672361,-10.3387516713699));
#1664=CARTESIAN_POINT('',(7.98059693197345,-19.2775598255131,-10.2808400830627));
#1665=CARTESIAN_POINT('',(8.12269648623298,-19.349471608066,-10.1739224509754));
#1666=CARTESIAN_POINT('',(8.19847113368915,-19.3827573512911,-10.124906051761));
#1667=CARTESIAN_POINT('',(8.34383811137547,-19.4359019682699,-10.0471327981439));
#1668=CARTESIAN_POINT('',(8.41180575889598,-19.4571122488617,-10.0162919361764));
#1669=CARTESIAN_POINT('',(8.55299696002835,-19.4930120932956,-9.96427680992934));
#1670=CARTESIAN_POINT('',(8.62621606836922,-19.5077070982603,-9.94309447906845));
#1671=CARTESIAN_POINT('',(8.7767876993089,-19.5293458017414,-9.91195485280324));
#1672=CARTESIAN_POINT('',(8.85416804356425,-19.5362280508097,-9.90208653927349));
#1673=CARTESIAN_POINT('',(9.00978894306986,-19.5412665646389,-9.89485849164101));
#1674=CARTESIAN_POINT('',(9.0880291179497,-19.5394265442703,-9.89749343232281));
#1675=CARTESIAN_POINT('',(9.23292674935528,-19.5280007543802,-9.91389845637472));
#1676=CARTESIAN_POINT('',(9.2998298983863,-19.5193904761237,-9.92626634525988));
#1677=CARTESIAN_POINT('',(9.43041729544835,-19.4963373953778,-9.95949570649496));
#1678=CARTESIAN_POINT('',(9.49410036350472,-19.4818924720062,-9.9803602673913));
#1679=CARTESIAN_POINT('',(9.63895652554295,-19.4421464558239,-10.0380402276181));
#1680=CARTESIAN_POINT('',(9.71836041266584,-19.4148129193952,-10.0778867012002));
#1681=CARTESIAN_POINT('',(9.86835131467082,-19.353631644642,-10.1678192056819));
#1682=CARTESIAN_POINT('',(9.93891978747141,-19.3197705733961,-10.2179262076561));
#1683=CARTESIAN_POINT('',(10.104670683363,-19.2294225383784,-10.3529133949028));
#1684=CARTESIAN_POINT('',(10.1943665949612,-19.1701250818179,-10.4426026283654));
#1685=CARTESIAN_POINT('',(10.3564507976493,-19.0462380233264,-10.6331393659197));
#1686=CARTESIAN_POINT('',(10.4288004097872,-18.9816370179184,-10.7340110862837));
#1687=CARTESIAN_POINT('',(10.5504819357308,-18.8584708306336,-10.9297896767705));
#1688=CARTESIAN_POINT('',(10.6015752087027,-18.8001925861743,-11.023805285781));
#1689=CARTESIAN_POINT('',(10.6942086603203,-18.6829284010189,-11.2160667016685));
#1690=CARTESIAN_POINT('',(10.7357414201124,-18.623941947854,-11.3143157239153));
#1691=CARTESIAN_POINT('',(10.8105985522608,-18.5059727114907,-11.5141385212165));
#1692=CARTESIAN_POINT('',(10.8439067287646,-18.446990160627,-11.6157184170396));
#1693=CARTESIAN_POINT('',(10.9032897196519,-18.329684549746,-11.8212808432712));
#1694=CARTESIAN_POINT('',(10.9293662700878,-18.2713613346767,-11.9252627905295));
#1695=CARTESIAN_POINT('',(10.9793229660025,-18.14530643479,-12.1540475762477));
#1696=CARTESIAN_POINT('',(11.001962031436,-18.0777717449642,-12.2792279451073));
#1697=CARTESIAN_POINT('',(11.0396368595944,-17.9445020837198,-12.5316703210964));
#1698=CARTESIAN_POINT('',(11.0546714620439,-17.8787673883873,-12.6589326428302));
#1699=CARTESIAN_POINT('',(11.078076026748,-17.7495286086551,-12.9147858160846));
#1700=CARTESIAN_POINT('',(11.0864621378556,-17.6860194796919,-13.043372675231));
#1701=CARTESIAN_POINT('',(11.0974243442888,-17.561230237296,-13.3018864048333));
#1702=CARTESIAN_POINT('',(11.0999993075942,-17.4999505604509,-13.4318135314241));
#1703=CARTESIAN_POINT('',(11.1,-17.4398492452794,-13.5622836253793));
#1704=B_SPLINE_CURVE_WITH_KNOTS('',3,(#1550,#1551,#1552,#1553,#1554,#1555,#1556,#1557,#1558,
#1559,#1560,#1561,#1562,#1563,#1564,#1565,#1566,#1567,#1568,#1569,#1570,#1571,#1572,#1573,#1574,
#1575,#1576,#1577,#1578,#1579,#1580,#1581,#1582,#1583,#1584,#1585,#1586,#1587,#1588,#1589,#1590,
#1591,#1592,#1593,#1594,#1595,#1596,#1597,#1598,#1599,#1600,#1601,#1602,#1603,#1604,#1605,#1606,
#1607,#1608,#1609,#1610,#1611,#1612,#1613,#1614,#1615,#1616,#1617,#1618,#1619,#1620,#1621,#1622,
#1623,#1624,#1625,#1626,#1627,#1628,#1629,#1630,#1631,#1632,#1633,#1634,#1635,#1636,#1637,#1638,
#1639,#1640,#1641,#1642,#1643,#1644,#1645,#1646,#1647,#1648,#1649,#1650,#1651,#1652,#1653,#1654,
#1655,#1656,#1657,#1658,#1659,#1660,#1661,#1662,#1663,#1664,#1665,#1666,#1667,#1668,#1669,#1670,
#1671,#1672,#1673,#1674,#1675,#1676,#1677,#1678,#1679,#1680,#1681,#1682,#1683,#1684,#1685,#1686,
#1687,#1688,#1689,#1690,#1691,#1692,#1693,#1694,#1695,#1696,#1697,#1698,#1699,#1700,#1701,#1702,
#1703),.UNSPECIFIED.,.T.,.F.,(4,2,2,2,2,2,2,2,2,2,2,2,2,2,2,2,2,2,2,2,2,2,2,2,2,2,2,2,2,2,2,2,2,
2,2,2,2,2,2,2,2,2,2,2,2,2,2,2,2,2,2,2,2,2,2,2,2,2,2,2,2,2,2,2,2,2,2,2,2,2,2,2,2,2,2,2,4),(0.,
0.530562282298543,1.06113223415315,2.12322808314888,3.19533718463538,4.26609554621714,
4.7467517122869,5.22745519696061,5.70964432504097,6.19165855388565,6.66680729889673,
7.14257356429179,7.37919602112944,7.61579006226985,7.85189072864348,8.08776914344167,
8.1857443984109,8.2840402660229,8.38683810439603,8.48904809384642,8.52763699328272,
8.5662316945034,8.60539266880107,8.64444518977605,8.67875144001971,8.71310727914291,
8.75694890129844,8.80089291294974,8.88504830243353,8.96952679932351,9.13598218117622,
9.30293176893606,9.47070578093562,9.638230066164,9.969378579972,10.3006192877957,
10.9638894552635,11.6258152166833,12.2873648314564,12.9564693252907,13.6256247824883,
14.2955196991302,14.9653856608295,15.636136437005,16.3069654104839,16.9767006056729,
17.6462033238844,18.2798948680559,18.9141042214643,19.2290589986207,19.5439398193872,
19.8582900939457,20.1724853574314,20.4084395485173,20.6444220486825,20.8799769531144,
21.11539822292,21.4029993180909,21.6902634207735,21.922143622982,22.1538298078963,
22.3873259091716,22.6207225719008,22.8255559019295,23.0304637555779,23.3077614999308,
23.5856317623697,24.003347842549,24.4219868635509,24.7869962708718,25.1522879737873,
25.5182933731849,25.8842108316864,26.3160201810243,26.7478953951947,27.1787183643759,
27.6096252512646),.UNSPECIFIED.);
#1705=CARTESIAN_POINT('',(8.50412700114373,-15.3992341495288,-20.8849274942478));
#1706=VERTEX_POINT('',#1705);
#1707=CARTESIAN_POINT('',(9.49587299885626,-15.3992341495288,-20.8849274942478));
#1708=VERTEX_POINT('',#1707);
#1709=EDGE_CURVE('E382',#1706,#1708,#1704,.T.);
#1710=ORIENTED_EDGE('',*,*,#1709,.F.);
#1711=CARTESIAN_POINT('',(8.50412700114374,-15.3992341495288,-20.8849274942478));
#1712=CARTESIAN_POINT('',(8.51754218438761,-15.39598395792,-20.9139661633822));
#1713=CARTESIAN_POINT('',(8.53291333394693,-15.3923794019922,-20.9421179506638));
#1714=CARTESIAN_POINT('',(8.56759473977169,-15.3847693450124,-20.9960265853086));
#1715=CARTESIAN_POINT('',(8.58692552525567,-15.3807618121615,-21.0217698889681));
#1716=CARTESIAN_POINT('',(8.62947683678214,-15.3726823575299,-21.0699914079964));
#1717=CARTESIAN_POINT('',(8.65270953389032,-15.3686102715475,-21.0924589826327));
#1718=CARTESIAN_POINT('',(8.70268619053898,-15.3608490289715,-21.1330962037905));
#1719=CARTESIAN_POINT('',(8.7294238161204,-15.3571592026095,-21.1512734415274));
#1720=CARTESIAN_POINT('',(8.7857393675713,-15.3506172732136,-21.1824116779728));
#1721=CARTESIAN_POINT('',(8.81530377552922,-15.3477614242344,-21.1953961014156));
#1722=CARTESIAN_POINT('',(8.87646601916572,-15.3432625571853,-21.2154940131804));
#1723=CARTESIAN_POINT('',(8.90806303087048,-15.3416190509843,-21.2226098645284));
#1724=CARTESIAN_POINT('',(8.96794324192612,-15.3399081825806,-21.2299991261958));
#1725=CARTESIAN_POINT('',(8.99612920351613,-15.339665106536,-21.2310356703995));
#1726=CARTESIAN_POINT('',(9.05224165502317,-15.3403119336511,-21.2282551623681));
#1727=CARTESIAN_POINT('',(9.08016822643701,-15.341201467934,-21.224439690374));
#1728=CARTESIAN_POINT('',(9.1337258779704,-15.3439469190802,-21.2124231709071));
#1729=CARTESIAN_POINT('',(9.15940399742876,-15.3457593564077,-21.2044190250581));
#1730=CARTESIAN_POINT('',(9.20911449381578,-15.3501377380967,-21.1845125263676));
#1731=CARTESIAN_POINT('',(9.23314724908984,-15.3527035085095,-21.1726110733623));
#1732=CARTESIAN_POINT('',(9.28037198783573,-15.3585060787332,-21.1446196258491));
#1733=CARTESIAN_POINT('',(9.30344418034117,-15.3617721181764,-21.1283345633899));
#1734=CARTESIAN_POINT('',(9.34690931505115,-15.3685842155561,-21.0925134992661));
#1735=CARTESIAN_POINT('',(9.367297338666,-15.372130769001,-21.072971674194));
#1736=CARTESIAN_POINT('',(9.40871966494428,-15.3798792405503,-21.02731586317));
#1737=CARTESIAN_POINT('',(9.4291515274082,-15.3840786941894,-21.0006573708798));
#1738=CARTESIAN_POINT('',(9.46571839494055,-15.3920594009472,-20.9446201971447));
#1739=CARTESIAN_POINT('',(9.48186945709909,-15.3958421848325,-20.915252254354));
#1740=CARTESIAN_POINT('',(9.49587299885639,-15.3992341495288,-20.884927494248));
#1741=B_SPLINE_CURVE_WITH_KNOTS('',3,(#1711,#1712,#1713,#1714,#1715,#1716,#1717,#1718,#1719,
#1720,#1721,#1722,#1723,#1724,#1725,#1726,#1727,#1728,#1729,#1730,#1731,#1732,#1733,#1734,#1735,
#1736,#1737,#1738,#1739,#1740),.UNSPECIFIED.,.F.,.F.,(4,2,2,2,2,2,2,2,2,2,2,2,2,2,4),(0.,
0.0964633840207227,0.19344016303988,0.290725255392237,0.387836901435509,0.484505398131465,
0.5811349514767,0.665321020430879,0.749479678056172,0.829996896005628,0.910495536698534,
0.995441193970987,1.08054040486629,1.18167877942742,1.28243224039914),.UNSPECIFIED.);
#1742=EDGE_CURVE('E350',#1706,#1708,#1741,.T.);
#1743=ORIENTED_EDGE('',*,*,#1742,.T.);
#1744=EDGE_LOOP('',(#1710,#1743));
#1745=FACE_BOUND('',#1744,.T.);
#1746=CARTESIAN_POINT('',(9.,-17.4398492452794,-5.));
#1747=DIRECTION('',(0.,0.,1.));
#1748=DIRECTION('',(1.,0.,0.));
#1749=AXIS2_PLACEMENT_3D('',#1746,#1747,#1748);
#1750=CIRCLE('',#1749,2.1);
#1751=CARTESIAN_POINT('',(11.1,-17.4398492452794,-5.));
#1752=VERTEX_POINT('',#1751);
#1753=EDGE_CURVE('E671',#1752,#1752,#1750,.F.);
#1754=ORIENTED_EDGE('',*,*,#1753,.F.);
#1755=EDGE_LOOP('',(#1754));
#1756=FACE_BOUND('',#1755,.T.);
#1757=ADVANCED_FACE('F370',(#1745,#1756),#1549,.F.);
#1758=CARTESIAN_POINT('',(34.,17.4398492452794,-23.55));
#1759=DIRECTION('',(0.,0.,1.));
#1760=DIRECTION('',(1.,0.,0.));
#1761=AXIS2_PLACEMENT_3D('',#1758,#1759,#1760);
#1762=CYLINDRICAL_SURFACE('',#1761,2.1);
#1763=CARTESIAN_POINT('',(36.1,17.4398492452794,-13.5622836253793));
#1764=CARTESIAN_POINT('',(36.1000020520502,17.5339753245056,-13.3579521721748));
#1765=CARTESIAN_POINT('',(36.0936991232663,17.6310007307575,-13.1549340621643));
#1766=CARTESIAN_POINT('',(36.0658151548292,17.8304545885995,-12.7523021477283));
#1767=CARTESIAN_POINT('',(36.0442217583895,17.932887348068,-12.5526912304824));
#1768=CARTESIAN_POINT('',(35.9976778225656,18.0896427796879,-12.2574431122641));
#1769=CARTESIAN_POINT('',(35.9798284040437,18.1423595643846,-12.1598146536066));
#1770=CARTESIAN_POINT('',(35.9388327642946,18.2486610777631,-11.966165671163));
#1771=CARTESIAN_POINT('',(35.915687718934,18.3022456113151,-11.8701447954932));
#1772=CARTESIAN_POINT('',(35.8634725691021,18.4099232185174,-11.6802521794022));
#1773=CARTESIAN_POINT('',(35.8344135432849,18.4640151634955,-11.5863767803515));
#1774=CARTESIAN_POINT('',(35.7695289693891,18.5724397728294,-11.4010877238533));
#1775=CARTESIAN_POINT('',(35.7337025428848,18.6267724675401,-11.3096743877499));
#1776=CARTESIAN_POINT('',(35.6581776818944,18.7298578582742,-11.1387823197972));
#1777=CARTESIAN_POINT('',(35.6191943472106,18.7786394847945,-11.0590073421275));
#1778=CARTESIAN_POINT('',(35.5341062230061,18.8753508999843,-10.9028544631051));
#1779=CARTESIAN_POINT('',(35.4880063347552,18.9232812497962,-10.8264742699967));
#1780=CARTESIAN_POINT('',(35.3880094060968,19.0172232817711,-10.6785547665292));
#1781=CARTESIAN_POINT('',(35.3341620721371,19.0632449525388,-10.6069885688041));
#1782=CARTESIAN_POINT('',(35.2174963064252,19.1524750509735,-10.469742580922));
#1783=CARTESIAN_POINT('',(35.154691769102,19.1956876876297,-10.4040539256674));
#1784=CARTESIAN_POINT('',(35.0299363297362,19.2711491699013,-10.2904422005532));
#1785=CARTESIAN_POINT('',(34.9694495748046,19.3040470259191,-10.2413570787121));
#1786=CARTESIAN_POINT('',(34.8410316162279,19.365395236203,-10.1504574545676));
#1787=CARTESIAN_POINT('',(34.7730969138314,19.3938434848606,-10.1086463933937));
#1788=CARTESIAN_POINT('',(34.6292437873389,19.4448246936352,-10.0341232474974));
#1789=CARTESIAN_POINT('',(34.5532498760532,19.4672932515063,-10.0015100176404));
#1790=CARTESIAN_POINT('',(34.395212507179,19.5039109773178,-9.94854182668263));
#1791=CARTESIAN_POINT('',(34.3131786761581,19.5180730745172,-9.92816781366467));
#1792=CARTESIAN_POINT('',(34.1525654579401,19.5357276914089,-9.90279685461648));
#1793=CARTESIAN_POINT('',(34.0742518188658,19.5399977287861,-9.89667910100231));
#1794=CARTESIAN_POINT('',(33.9176824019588,19.5396930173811,-9.89711591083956));
#1795=CARTESIAN_POINT('',(33.8394266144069,19.5351205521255,-9.90366720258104));
#1796=CARTESIAN_POINT('',(33.6958786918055,19.5188028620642,-9.92712105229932));
#1797=CARTESIAN_POINT('',(33.6302216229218,19.5080648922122,-9.94257080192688));
#1798=CARTESIAN_POINT('',(33.5025420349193,19.4811227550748,-9.98148684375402));
#1799=CARTESIAN_POINT('',(33.4405205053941,19.464917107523,-10.0049553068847));
#1800=CARTESIAN_POINT('',(33.2952723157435,19.4200903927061,-10.0701998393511));
#1801=CARTESIAN_POINT('',(33.2143602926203,19.3891254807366,-10.1155108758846));
#1802=CARTESIAN_POINT('',(33.0623343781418,19.3207451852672,-10.2164984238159));
#1803=CARTESIAN_POINT('',(32.9912436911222,19.2833149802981,-10.2721987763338));
#1804=CARTESIAN_POINT('',(32.8227322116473,19.1828926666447,-10.4232212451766));
#1805=CARTESIAN_POINT('',(32.7317409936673,19.1169876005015,-10.523730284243));
#1806=CARTESIAN_POINT('',(32.5687936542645,18.9803011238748,-10.7360774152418));
#1807=CARTESIAN_POINT('',(32.496881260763,18.9095089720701,-10.8479407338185));
#1808=CARTESIAN_POINT('',(32.3760639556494,18.7740528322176,-11.0662321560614));
#1809=CARTESIAN_POINT('',(32.3254882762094,18.7095849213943,-11.171877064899));
#1810=CARTESIAN_POINT('',(32.2349370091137,18.5803678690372,-11.387510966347));
#1811=CARTESIAN_POINT('',(32.1949697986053,18.5156185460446,-11.497503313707));
#1812=CARTESIAN_POINT('',(32.1240879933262,18.3866190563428,-11.7208071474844));
#1813=CARTESIAN_POINT('',(32.0931849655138,18.3223696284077,-11.8341226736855));
#1814=CARTESIAN_POINT('',(32.0392372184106,18.1949618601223,-12.0632408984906));
#1815=CARTESIAN_POINT('',(32.0161954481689,18.1318039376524,-12.1790445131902));
#1816=CARTESIAN_POINT('',(31.9774517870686,18.0085055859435,-12.4096864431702));
#1817=CARTESIAN_POINT('',(31.9615825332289,17.9483291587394,-12.5244778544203));
#1818=CARTESIAN_POINT('',(31.9355905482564,17.8295960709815,-12.7555493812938));
#1819=CARTESIAN_POINT('',(31.9254689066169,17.7710397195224,-12.8718297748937));
#1820=CARTESIAN_POINT('',(31.9027220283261,17.5979770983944,-13.2226392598));
#1821=CARTESIAN_POINT('',(31.8977351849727,17.4861474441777,-13.4590054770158));
#1822=CARTESIAN_POINT('',(31.9040781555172,17.270146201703,-13.9356599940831));
#1823=CARTESIAN_POINT('',(31.915453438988,17.1659968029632,-14.175957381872));
#1824=CARTESIAN_POINT('',(31.9516304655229,16.96603561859,-14.6588733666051));
#1825=CARTESIAN_POINT('',(31.9764276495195,16.8702210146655,-14.9014911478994));
#1826=CARTESIAN_POINT('',(32.0316017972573,16.7039160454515,-15.3435727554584));
#1827=CARTESIAN_POINT('',(32.0601076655,16.6320132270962,-15.5427475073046));
#1828=CARTESIAN_POINT('',(32.1236166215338,16.4938210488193,-15.9420267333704));
#1829=CARTESIAN_POINT('',(32.1586203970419,16.427532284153,-16.1421313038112));
#1830=CARTESIAN_POINT('',(32.2343855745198,16.3005170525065,-16.5431815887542));
#1831=CARTESIAN_POINT('',(32.2751513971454,16.2397949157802,-16.7441278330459));
#1832=CARTESIAN_POINT('',(32.3618225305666,16.1239433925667,-17.1465079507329));
#1833=CARTESIAN_POINT('',(32.4077275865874,16.0688137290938,-17.3479417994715));
#1834=CARTESIAN_POINT('',(32.5041465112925,15.9642238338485,-17.7506689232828));
#1835=CARTESIAN_POINT('',(32.5546498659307,15.9147512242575,-17.9519615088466));
#1836=CARTESIAN_POINT('',(32.6601340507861,15.821291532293,-18.3546648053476));
#1837=CARTESIAN_POINT('',(32.7151152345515,15.7773048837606,-18.5560755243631));
#1838=CARTESIAN_POINT('',(32.8295949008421,15.6948209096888,-18.9585540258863));
#1839=CARTESIAN_POINT('',(32.8890897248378,15.6563192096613,-19.1596219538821));
#1840=CARTESIAN_POINT('',(33.0132125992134,15.5847443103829,-19.5611191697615));
#1841=CARTESIAN_POINT('',(33.0778397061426,15.5516701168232,-19.7615485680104));
#1842=CARTESIAN_POINT('',(33.1830970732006,15.5048299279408,-20.0695635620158));
#1843=CARTESIAN_POINT('',(33.2211983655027,15.4891470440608,-20.1777238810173));
#1844=CARTESIAN_POINT('',(33.3002723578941,15.4594000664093,-20.3932063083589));
#1845=CARTESIAN_POINT('',(33.3412445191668,15.4453356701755,-20.5005285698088));
#1846=CARTESIAN_POINT('',(33.408316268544,15.4247728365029,-20.6660509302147));
#1847=CARTESIAN_POINT('',(33.43288970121,15.4176997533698,-20.724791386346));
#1848=CARTESIAN_POINT('',(33.4839050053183,15.4040847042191,-20.8414621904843));
#1849=CARTESIAN_POINT('',(33.5103457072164,15.3975424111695,-20.8993930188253));
#1850=CARTESIAN_POINT('',(33.5742831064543,15.3831087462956,-21.0314912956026));
#1851=CARTESIAN_POINT('',(33.6127037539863,15.3754084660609,-21.1052654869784));
#1852=CARTESIAN_POINT('',(33.6762991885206,15.3648439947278,-21.2109773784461));
#1853=CARTESIAN_POINT('',(33.6980988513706,15.3615323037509,-21.2448855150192));
#1854=CARTESIAN_POINT('',(33.7448919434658,15.3552656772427,-21.3104296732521));
#1855=CARTESIAN_POINT('',(33.7698733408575,15.3523094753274,-21.342073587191));
#1856=CARTESIAN_POINT('',(33.8083347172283,15.348586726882,-21.382688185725));
#1857=CARTESIAN_POINT('',(33.8195648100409,15.3475822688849,-21.3937398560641));
#1858=CARTESIAN_POINT('',(33.8430797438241,15.3456867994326,-21.4147420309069));
#1859=CARTESIAN_POINT('',(33.8553665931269,15.3447960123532,-21.4246903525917));
#1860=CARTESIAN_POINT('',(33.8813580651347,15.3431622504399,-21.4430472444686));
#1861=CARTESIAN_POINT('',(33.895081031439,15.3424216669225,-21.4514307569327));
#1862=CARTESIAN_POINT('',(33.9238408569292,15.3411821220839,-21.4655234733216));
#1863=CARTESIAN_POINT('',(33.9388710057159,15.3406820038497,-21.4712454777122));
#1864=CARTESIAN_POINT('',(33.9646154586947,15.3401222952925,-21.4776604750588));
#1865=CARTESIAN_POINT('',(33.9750648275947,15.3399708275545,-21.4794008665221));
#1866=CARTESIAN_POINT('',(33.9961099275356,15.339826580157,-21.4810581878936));
#1867=CARTESIAN_POINT('',(34.0067055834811,15.3398337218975,-21.4809760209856));
#1868=CARTESIAN_POINT('',(34.0276983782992,15.3400056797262,-21.4790005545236));
#1869=CARTESIAN_POINT('',(34.038095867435,15.3401701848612,-21.4771108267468));
#1870=CARTESIAN_POINT('',(34.0584674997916,15.3406385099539,-21.4717449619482));
#1871=CARTESIAN_POINT('',(34.0684411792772,15.3409424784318,-21.4682671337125));
#1872=CARTESIAN_POINT('',(34.0933326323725,15.3418690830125,-21.4577036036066));
#1873=CARTESIAN_POINT('',(34.1078490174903,15.3425746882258,-21.4496902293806));
#1874=CARTESIAN_POINT('',(34.135510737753,15.3441802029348,-21.4315906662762));
#1875=CARTESIAN_POINT('',(34.1486515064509,15.3450807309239,-21.4214978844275));
#1876=CARTESIAN_POINT('',(34.1944586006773,15.3486021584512,-21.382368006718));
#1877=CARTESIAN_POINT('',(34.2237019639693,15.3516170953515,-21.3494687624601));
#1878=CARTESIAN_POINT('',(34.2777582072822,15.3581248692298,-21.2802493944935));
#1879=CARTESIAN_POINT('',(34.3025359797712,15.3616211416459,-21.243905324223));
#1880=CARTESIAN_POINT('',(34.3515282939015,15.3693178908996,-21.1658802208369));
#1881=CARTESIAN_POINT('',(34.3754581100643,15.3735537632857,-21.1240225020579));
#1882=CARTESIAN_POINT('',(34.4211201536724,15.3823766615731,-21.0391506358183));
#1883=CARTESIAN_POINT('',(34.4428502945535,15.3869640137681,-20.9961354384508));
#1884=CARTESIAN_POINT('',(34.5058496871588,15.4012248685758,-20.8658463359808));
#1885=CARTESIAN_POINT('',(34.5448199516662,15.4113786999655,-20.7775175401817));
#1886=CARTESIAN_POINT('',(34.6193006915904,15.4328739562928,-20.5994778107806));
#1887=CARTESIAN_POINT('',(34.6548069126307,15.4442168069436,-20.5097653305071));
#1888=CARTESIAN_POINT('',(34.7233631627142,15.4680332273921,-20.3297126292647));
#1889=CARTESIAN_POINT('',(34.7564167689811,15.4805050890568,-20.239373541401));
#1890=CARTESIAN_POINT('',(34.8528819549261,15.5195830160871,-19.9679048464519));
#1891=CARTESIAN_POINT('',(34.9136889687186,15.5478789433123,-19.7860948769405));
#1892=CARTESIAN_POINT('',(35.0306039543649,15.6089543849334,-19.4216985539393));
#1893=CARTESIAN_POINT('',(35.086710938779,15.6417348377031,-19.2391120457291));
#1894=CARTESIAN_POINT('',(35.1950426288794,15.7118325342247,-18.8733902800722));
#1895=CARTESIAN_POINT('',(35.2472621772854,15.7491556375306,-18.6902546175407));
#1896=CARTESIAN_POINT('',(35.347991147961,15.8283223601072,-18.3239607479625));
#1897=CARTESIAN_POINT('',(35.3965009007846,15.8701655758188,-18.1408025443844));
#1898=CARTESIAN_POINT('',(35.4896375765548,15.958270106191,-17.7751819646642));
#1899=CARTESIAN_POINT('',(35.534275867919,16.0045175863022,-17.5927191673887));
#1900=CARTESIAN_POINT('',(35.6196170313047,16.1015624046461,-17.2280878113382));
#1901=CARTESIAN_POINT('',(35.6603197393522,16.1523599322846,-17.0459192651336));
#1902=CARTESIAN_POINT('',(35.775993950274,16.3115418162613,-16.5003419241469));
#1903=CARTESIAN_POINT('',(35.8446233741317,16.4268011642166,-16.1375047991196));
#1904=CARTESIAN_POINT('',(35.932715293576,16.6154620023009,-15.5897451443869));
#1905=CARTESIAN_POINT('',(35.9598990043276,16.6821276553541,-15.4036959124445));
#1906=CARTESIAN_POINT('',(36.0078818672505,16.8203580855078,-15.032562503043));
#1907=CARTESIAN_POINT('',(36.0286806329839,16.891923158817,-14.8474783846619));
#1908=CARTESIAN_POINT('',(36.0630086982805,17.0401053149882,-14.478054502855));
#1909=CARTESIAN_POINT('',(36.0765177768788,17.1167357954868,-14.2937182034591));
#1910=CARTESIAN_POINT('',(36.0950121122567,17.2747635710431,-13.9266698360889));
#1911=CARTESIAN_POINT('',(36.0999981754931,17.3561604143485,-13.7439576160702));
#1912=CARTESIAN_POINT('',(36.1,17.4398492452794,-13.5622836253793));
#1913=B_SPLINE_CURVE_WITH_KNOTS('',3,(#1763,#1764,#1765,#1766,#1767,#1768,#1769,#1770,#1771,
#1772,#1773,#1774,#1775,#1776,#1777,#1778,#1779,#1780,#1781,#1782,#1783,#1784,#1785,#1786,#1787,
#1788,#1789,#1790,#1791,#1792,#1793,#1794,#1795,#1796,#1797,#1798,#1799,#1800,#1801,#1802,#1803,
#1804,#1805,#1806,#1807,#1808,#1809,#1810,#1811,#1812,#1813,#1814,#1815,#1816,#1817,#1818,#1819,
#1820,#1821,#1822,#1823,#1824,#1825,#1826,#1827,#1828,#1829,#1830,#1831,#1832,#1833,#1834,#1835,
#1836,#1837,#1838,#1839,#1840,#1841,#1842,#1843,#1844,#1845,#1846,#1847,#1848,#1849,#1850,#1851,
#1852,#1853,#1854,#1855,#1856,#1857,#1858,#1859,#1860,#1861,#1862,#1863,#1864,#1865,#1866,#1867,
#1868,#1869,#1870,#1871,#1872,#1873,#1874,#1875,#1876,#1877,#1878,#1879,#1880,#1881,#1882,#1883,
#1884,#1885,#1886,#1887,#1888,#1889,#1890,#1891,#1892,#1893,#1894,#1895,#1896,#1897,#1898,#1899,
#1900,#1901,#1902,#1903,#1904,#1905,#1906,#1907,#1908,#1909,#1910,#1911,#1912),.UNSPECIFIED.,
.T.,.F.,(4,2,2,2,2,2,2,2,2,2,2,2,2,2,2,2,2,2,2,2,2,2,2,2,2,2,2,2,2,2,2,2,2,2,2,2,2,2,2,2,2,2,2,
2,2,2,2,2,2,2,2,2,2,2,2,2,2,2,2,2,2,2,2,2,2,2,2,2,2,2,2,2,2,2,4),(0.,0.674811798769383,
1.35016956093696,1.68719394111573,2.02414355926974,2.36046768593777,2.69683549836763,
3.00050034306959,3.30395697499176,3.60554697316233,3.90667413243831,4.15973166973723,
4.412908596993,4.66871102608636,4.92411422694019,5.15864048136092,5.39310617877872,
5.597160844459,5.80127079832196,6.09292564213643,6.38525819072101,6.8349728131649,
7.28570942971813,7.68622338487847,8.08705267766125,8.48839127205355,8.88988025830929,
9.28144434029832,9.67308262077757,10.4568080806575,11.2427156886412,12.0283565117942,
12.6691787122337,13.3100687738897,13.95145322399,14.5928058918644,15.2327272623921,
15.8726992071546,16.5121578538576,17.1514992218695,17.4986940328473,17.8458238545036,
18.0379848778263,18.2300265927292,18.4801997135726,18.6014707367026,18.7222960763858,
18.7696082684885,18.817012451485,18.8651205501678,18.9129948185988,18.9446337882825,
18.976257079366,19.007818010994,19.0394126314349,19.0889127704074,19.1385723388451,
19.2698868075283,19.4021924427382,19.5472565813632,19.692457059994,19.9835106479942,
20.2749173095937,20.5658902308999,21.1470931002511,21.7284177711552,22.310500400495,
22.8925311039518,23.4727903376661,24.0530737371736,25.2125080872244,25.8108619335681,
26.4092519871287,27.0092935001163,27.6092782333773),.UNSPECIFIED.);
#1914=CARTESIAN_POINT('',(34.4958729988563,15.3992341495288,-20.8849274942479));
#1915=VERTEX_POINT('',#1914);
#1916=CARTESIAN_POINT('',(33.5041270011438,15.3992341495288,-20.884927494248));
#1917=VERTEX_POINT('',#1916);
#1918=EDGE_CURVE('E305',#1915,#1917,#1913,.T.);
#1919=ORIENTED_EDGE('',*,*,#1918,.F.);
#1920=CARTESIAN_POINT('',(34.4958729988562,15.3992341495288,-20.8849274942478));
#1921=CARTESIAN_POINT('',(34.4824578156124,15.39598395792,-20.9139661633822));
#1922=CARTESIAN_POINT('',(34.4670866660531,15.3923794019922,-20.9421179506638));
#1923=CARTESIAN_POINT('',(34.4324052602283,15.3847693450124,-20.9960265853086));
#1924=CARTESIAN_POINT('',(34.4130744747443,15.3807618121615,-21.0217698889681));
#1925=CARTESIAN_POINT('',(34.3705231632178,15.3726823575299,-21.0699914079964));
#1926=CARTESIAN_POINT('',(34.3472904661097,15.3686102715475,-21.0924589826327));
#1927=CARTESIAN_POINT('',(34.297313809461,15.3608490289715,-21.1330962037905));
#1928=CARTESIAN_POINT('',(34.2705761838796,15.3571592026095,-21.1512734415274));
#1929=CARTESIAN_POINT('',(34.2142606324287,15.3506172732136,-21.1824116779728));
#1930=CARTESIAN_POINT('',(34.1846962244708,15.3477614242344,-21.1953961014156));
#1931=CARTESIAN_POINT('',(34.1235339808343,15.3432625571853,-21.2154940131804));
#1932=CARTESIAN_POINT('',(34.0919369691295,15.3416190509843,-21.2226098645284));
#1933=CARTESIAN_POINT('',(34.0320567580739,15.3399081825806,-21.2299991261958));
#1934=CARTESIAN_POINT('',(34.0038707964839,15.339665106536,-21.2310356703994));
#1935=CARTESIAN_POINT('',(33.9477583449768,15.3403119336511,-21.2282551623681));
#1936=CARTESIAN_POINT('',(33.919831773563,15.341201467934,-21.224439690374));
#1937=CARTESIAN_POINT('',(33.8662741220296,15.3439469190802,-21.2124231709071));
#1938=CARTESIAN_POINT('',(33.8405960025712,15.3457593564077,-21.2044190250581));
#1939=CARTESIAN_POINT('',(33.7908855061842,15.3501377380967,-21.1845125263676));
#1940=CARTESIAN_POINT('',(33.7668527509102,15.3527035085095,-21.1726110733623));
#1941=CARTESIAN_POINT('',(33.7196280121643,15.3585060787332,-21.144619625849));
#1942=CARTESIAN_POINT('',(33.6965558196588,15.3617721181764,-21.1283345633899));
#1943=CARTESIAN_POINT('',(33.6530906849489,15.3685842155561,-21.0925134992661));
#1944=CARTESIAN_POINT('',(33.632702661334,15.372130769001,-21.0729716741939));
#1945=CARTESIAN_POINT('',(33.5912803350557,15.3798792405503,-21.02731586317));
#1946=CARTESIAN_POINT('',(33.5708484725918,15.3840786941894,-21.0006573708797));
#1947=CARTESIAN_POINT('',(33.5342816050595,15.3920594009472,-20.9446201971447));
#1948=CARTESIAN_POINT('',(33.5181305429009,15.3958421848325,-20.915252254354));
#1949=CARTESIAN_POINT('',(33.5041270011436,15.3992341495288,-20.884927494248));
#1950=B_SPLINE_CURVE_WITH_KNOTS('',3,(#1920,#1921,#1922,#1923,#1924,#1925,#1926,#1927,#1928,
#1929,#1930,#1931,#1932,#1933,#1934,#1935,#1936,#1937,#1938,#1939,#1940,#1941,#1942,#1943,#1944,
#1945,#1946,#1947,#1948,#1949),.UNSPECIFIED.,.F.,.F.,(4,2,2,2,2,2,2,2,2,2,2,2,2,2,4),(0.,
0.0964633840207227,0.193440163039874,0.290725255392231,0.387836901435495,0.484505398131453,
0.58113495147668,0.665321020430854,0.749479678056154,0.829996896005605,0.910495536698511,
0.99544119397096,1.08054040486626,1.18167877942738,1.2824322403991),.UNSPECIFIED.);
#1951=EDGE_CURVE('E883',#1915,#1917,#1950,.T.);
#1952=ORIENTED_EDGE('',*,*,#1951,.T.);
#1953=EDGE_LOOP('',(#1919,#1952));
#1954=FACE_BOUND('',#1953,.T.);
#1955=CARTESIAN_POINT('',(34.,17.4398492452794,-5.));
#1956=DIRECTION('',(0.,0.,1.));
#1957=DIRECTION('',(1.,0.,0.));
#1958=AXIS2_PLACEMENT_3D('',#1955,#1956,#1957);
#1959=CIRCLE('',#1958,2.1);
#1960=CARTESIAN_POINT('',(36.1,17.4398492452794,-5.));
#1961=VERTEX_POINT('',#1960);
#1962=EDGE_CURVE('E680',#1961,#1961,#1959,.F.);
#1963=ORIENTED_EDGE('',*,*,#1962,.F.);
#1964=EDGE_LOOP('',(#1963));
#1965=FACE_BOUND('',#1964,.T.);
#1966=ADVANCED_FACE('F375',(#1954,#1965),#1762,.F.);
#1967=CARTESIAN_POINT('',(50.,-15.25,-23.55));
#1968=DIRECTION('',(0.,0.,1.));
#1969=DIRECTION('',(1.,0.,0.));
#1970=AXIS2_PLACEMENT_3D('',#1967,#1968,#1969);
#1971=PLANE('',#1970);
#1972=CARTESIAN_POINT('',(9.,0.,-23.55));
#1973=DIRECTION('',(0.,0.,-1.));
#1974=DIRECTION('',(-1.,0.,0.));
#1975=AXIS2_PLACEMENT_3D('',#1972,#1973,#1974);
#1976=CIRCLE('',#1975,5.);
#1977=CARTESIAN_POINT('',(4.,0.,-23.55));
#1978=VERTEX_POINT('',#1977);
#1979=EDGE_CURVE('E783',#1978,#1978,#1976,.T.);
#1980=ORIENTED_EDGE('',*,*,#1979,.F.);
#1981=EDGE_LOOP('',(#1980));
#1982=FACE_BOUND('',#1981,.T.);
#1983=CARTESIAN_POINT('',(34.,0.,-23.55));
#1984=DIRECTION('',(0.,0.,-1.));
#1985=DIRECTION('',(-1.,0.,0.));
#1986=AXIS2_PLACEMENT_3D('',#1983,#1984,#1985);
#1987=CIRCLE('',#1986,5.);
#1988=CARTESIAN_POINT('',(29.,0.,-23.55));
#1989=VERTEX_POINT('',#1988);
#1990=EDGE_CURVE('E548',#1989,#1989,#1987,.T.);
#1991=ORIENTED_EDGE('',*,*,#1990,.F.);
#1992=EDGE_LOOP('',(#1991));
#1993=FACE_BOUND('',#1992,.T.);
#1994=ORIENTED_EDGE('',*,*,#660,.T.);
#1995=ORIENTED_EDGE('',*,*,#684,.T.);
#1996=ORIENTED_EDGE('',*,*,#396,.T.);
#1997=ORIENTED_EDGE('',*,*,#428,.F.);
#1998=ORIENTED_EDGE('',*,*,#462,.T.);
#1999=ORIENTED_EDGE('',*,*,#494,.F.);
#2000=ORIENTED_EDGE('',*,*,#528,.T.);
#2001=ORIENTED_EDGE('',*,*,#560,.F.);
#2002=ORIENTED_EDGE('',*,*,#594,.T.);
#2003=ORIENTED_EDGE('',*,*,#708,.T.);
#2004=ORIENTED_EDGE('',*,*,#627,.T.);
#2005=ORIENTED_EDGE('',*,*,#111,.T.);
#2006=DIRECTION('',(0.,-1.,0.));
#2007=VECTOR('',#2006,1.);
#2008=CARTESIAN_POINT('',(50.,0.,-23.55));
#2009=LINE('',#2008,#2007);
#2010=CARTESIAN_POINT('',(50.,-21.9573808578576,-23.55));
#2011=VERTEX_POINT('',#2010);
#2012=EDGE_CURVE('E724',#2011,#102,#2009,.T.);
#2013=ORIENTED_EDGE('',*,*,#2012,.F.);
#2014=CARTESIAN_POINT('',(50.,-21.9573808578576,-23.55));
#2015=CARTESIAN_POINT('',(50.0000269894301,-21.7448749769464,-23.55));
#2016=CARTESIAN_POINT('',(49.9911961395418,-21.5324047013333,-23.55));
#2017=CARTESIAN_POINT('',(49.956343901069,-21.1089832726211,-23.55));
#2018=CARTESIAN_POINT('',(49.9303313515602,-20.8980313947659,-23.55));
#2019=CARTESIAN_POINT('',(49.861790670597,-20.4797939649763,-23.55));
#2020=CARTESIAN_POINT('',(49.8193355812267,-20.2724963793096,-23.55));
#2021=CARTESIAN_POINT('',(49.7185831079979,-19.8617702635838,-23.55));
#2022=CARTESIAN_POINT('',(49.6602834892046,-19.6583422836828,-23.55));
#2023=CARTESIAN_POINT('',(49.5244963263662,-19.2437918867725,-23.55));
#2024=CARTESIAN_POINT('',(49.4460332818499,-19.0329891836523,-23.55));
#2025=CARTESIAN_POINT('',(49.2731593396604,-18.6179552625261,-23.55));
#2026=CARTESIAN_POINT('',(49.1787422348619,-18.4137266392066,-23.55));
#2027=CARTESIAN_POINT('',(48.9751082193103,-18.0126520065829,-23.55));
#2028=CARTESIAN_POINT('',(48.8658827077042,-17.8158103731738,-23.55));
#2029=CARTESIAN_POINT('',(48.633935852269,-17.4302264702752,-23.55));
#2030=CARTESIAN_POINT('',(48.511211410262,-17.2414860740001,-23.55));
#2031=CARTESIAN_POINT('',(48.1846617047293,-16.7738182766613,-23.55));
#2032=CARTESIAN_POINT('',(47.9725627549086,-16.500637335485,-23.55));
#2033=CARTESIAN_POINT('',(47.5245079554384,-15.9745915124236,-23.55));
#2034=CARTESIAN_POINT('',(47.2885399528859,-15.7217370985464,-23.55));
#2035=CARTESIAN_POINT('',(46.7971924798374,-15.2349328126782,-23.55));
#2036=CARTESIAN_POINT('',(46.5417805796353,-15.0010159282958,-23.55));
#2037=CARTESIAN_POINT('',(46.0165061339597,-14.55027596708,-23.55));
#2038=CARTESIAN_POINT('',(45.7466459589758,-14.3334501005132,-23.55));
#2039=CARTESIAN_POINT('',(45.2738433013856,-13.9723897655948,-23.55));
#2040=CARTESIAN_POINT('',(45.0733816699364,-13.8248641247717,-23.55));
#2041=CARTESIAN_POINT('',(44.6688184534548,-13.5354862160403,-23.55));
#2042=CARTESIAN_POINT('',(44.4647220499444,-13.3936266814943,-23.55));
#2043=CARTESIAN_POINT('',(43.8476554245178,-12.9730566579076,-23.55));
#2044=CARTESIAN_POINT('',(43.4308399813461,-12.70004145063,-23.55));
#2045=CARTESIAN_POINT('',(43.0093333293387,-12.4240989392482,-23.55));
#2046=CARTESIAN_POINT('',(43.0046666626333,-12.4210438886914,-23.55));
#2047=CARTESIAN_POINT('',(43.,-12.4179888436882,-23.55));
#2048=B_SPLINE_CURVE_WITH_KNOTS('',3,(#2014,#2015,#2016,#2017,#2018,#2019,#2020,#2021,#2022,
#2023,#2024,#2025,#2026,#2027,#2028,#2029,#2030,#2031,#2032,#2033,#2034,#2035,#2036,#2037,#2038,
#2039,#2040,#2041,#2042,#2043,#2044,#2045,#2046,#2047),.UNSPECIFIED.,.F.,.F.,(4,2,2,2,2,2,2,2,2,
2,2,2,2,2,2,2,4),(0.,0.637281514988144,1.2742354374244,1.90839171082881,2.54263748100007,
3.21673650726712,3.89109840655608,4.56585367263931,5.24076412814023,6.27659634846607,
7.31295864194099,8.35108899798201,9.38904954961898,10.1356338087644,10.881227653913,
12.3758858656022,12.3926190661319),.UNSPECIFIED.);
#2049=CARTESIAN_POINT('',(43.,-12.4179888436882,-23.55));
#2050=VERTEX_POINT('',#2049);
#2051=EDGE_CURVE('E908',#2011,#2050,#2048,.T.);
#2052=ORIENTED_EDGE('',*,*,#2051,.T.);
#2053=DIRECTION('',(-1.,0.,0.));
#2054=VECTOR('',#2053,1.);
#2055=CARTESIAN_POINT('',(50.,-12.4179888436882,-23.55));
#2056=LINE('',#2055,#2054);
#2057=EDGE_CURVE('E330',#2050,#268,#2056,.T.);
#2058=ORIENTED_EDGE('',*,*,#2057,.T.);
#2059=ORIENTED_EDGE('',*,*,#269,.T.);
#2060=DIRECTION('',(-1.,0.,0.));
#2061=VECTOR('',#2060,1.);
#2062=CARTESIAN_POINT('',(50.,12.4179888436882,-23.55));
#2063=LINE('',#2062,#2061);
#2064=CARTESIAN_POINT('',(43.,12.4179888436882,-23.55));
#2065=VERTEX_POINT('',#2064);
#2066=EDGE_CURVE('E323',#260,#2065,#2063,.F.);
#2067=ORIENTED_EDGE('',*,*,#2066,.T.);
#2068=CARTESIAN_POINT('',(50.,21.9573808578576,-23.55));
#2069=CARTESIAN_POINT('',(50.0000269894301,21.7448749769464,-23.55));
#2070=CARTESIAN_POINT('',(49.9911961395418,21.5324047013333,-23.55));
#2071=CARTESIAN_POINT('',(49.956343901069,21.1089832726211,-23.55));
#2072=CARTESIAN_POINT('',(49.9303313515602,20.8980313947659,-23.55));
#2073=CARTESIAN_POINT('',(49.861790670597,20.4797939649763,-23.55));
#2074=CARTESIAN_POINT('',(49.8193355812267,20.2724963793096,-23.55));
#2075=CARTESIAN_POINT('',(49.7185831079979,19.8617702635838,-23.55));
#2076=CARTESIAN_POINT('',(49.6602834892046,19.6583422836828,-23.55));
#2077=CARTESIAN_POINT('',(49.5244963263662,19.2437918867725,-23.55));
#2078=CARTESIAN_POINT('',(49.4460332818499,19.0329891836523,-23.55));
#2079=CARTESIAN_POINT('',(49.2731593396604,18.6179552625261,-23.55));
#2080=CARTESIAN_POINT('',(49.1787422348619,18.4137266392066,-23.55));
#2081=CARTESIAN_POINT('',(48.9751082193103,18.0126520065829,-23.55));
#2082=CARTESIAN_POINT('',(48.8658827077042,17.8158103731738,-23.55));
#2083=CARTESIAN_POINT('',(48.633935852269,17.4302264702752,-23.55));
#2084=CARTESIAN_POINT('',(48.511211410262,17.2414860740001,-23.55));
#2085=CARTESIAN_POINT('',(48.1846617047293,16.7738182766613,-23.55));
#2086=CARTESIAN_POINT('',(47.9725627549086,16.500637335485,-23.55));
#2087=CARTESIAN_POINT('',(47.5245079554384,15.9745915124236,-23.55));
#2088=CARTESIAN_POINT('',(47.2885399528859,15.7217370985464,-23.55));
#2089=CARTESIAN_POINT('',(46.7971924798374,15.2349328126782,-23.55));
#2090=CARTESIAN_POINT('',(46.5417805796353,15.0010159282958,-23.55));
#2091=CARTESIAN_POINT('',(46.0165061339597,14.55027596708,-23.55));
#2092=CARTESIAN_POINT('',(45.7466459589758,14.3334501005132,-23.55));
#2093=CARTESIAN_POINT('',(45.2738433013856,13.9723897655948,-23.55));
#2094=CARTESIAN_POINT('',(45.0733816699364,13.8248641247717,-23.55));
#2095=CARTESIAN_POINT('',(44.6688184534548,13.5354862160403,-23.55));
#2096=CARTESIAN_POINT('',(44.4647220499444,13.3936266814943,-23.55));
#2097=CARTESIAN_POINT('',(43.8476554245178,12.9730566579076,-23.55));
#2098=CARTESIAN_POINT('',(43.4308399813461,12.70004145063,-23.55));
#2099=CARTESIAN_POINT('',(43.0093333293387,12.4240989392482,-23.55));
#2100=CARTESIAN_POINT('',(43.0046666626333,12.4210438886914,-23.55));
#2101=CARTESIAN_POINT('',(43.,12.4179888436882,-23.55));
#2102=B_SPLINE_CURVE_WITH_KNOTS('',3,(#2068,#2069,#2070,#2071,#2072,#2073,#2074,#2075,#2076,
#2077,#2078,#2079,#2080,#2081,#2082,#2083,#2084,#2085,#2086,#2087,#2088,#2089,#2090,#2091,#2092,
#2093,#2094,#2095,#2096,#2097,#2098,#2099,#2100,#2101),.UNSPECIFIED.,.F.,.F.,(4,2,2,2,2,2,2,2,2,
2,2,2,2,2,2,2,4),(0.,0.637281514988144,1.2742354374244,1.90839171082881,2.54263748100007,
3.21673650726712,3.89109840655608,4.56585367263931,5.24076412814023,6.27659634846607,
7.31295864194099,8.35108899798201,9.38904954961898,10.1356338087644,10.881227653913,
12.3758858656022,12.3926190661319),.UNSPECIFIED.);
#2103=CARTESIAN_POINT('',(50.,21.9573808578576,-23.55));
#2104=VERTEX_POINT('',#2103);
#2105=EDGE_CURVE('E422',#2065,#2104,#2102,.F.);
#2106=ORIENTED_EDGE('',*,*,#2105,.T.);
#2107=EDGE_CURVE('E861',#150,#2104,#2009,.T.);
#2108=ORIENTED_EDGE('',*,*,#2107,.F.);
#2109=ORIENTED_EDGE('',*,*,#151,.T.);
#2110=EDGE_LOOP('',(#1994,#1995,#1996,#1997,#1998,#1999,#2000,#2001,#2002,#2003,#2004,#2005,
#2013,#2052,#2058,#2059,#2067,#2106,#2108,#2109));
#2111=FACE_BOUND('',#2110,.T.);
#2112=ADVANCED_FACE('F401',(#1982,#1993,#2111),#1971,.F.);
#2113=CARTESIAN_POINT('',(50.,-39.1214875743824,-23.55));
#2114=DIRECTION('',(-1.,0.,0.));
#2115=DIRECTION('',(0.,0.,1.));
#2116=AXIS2_PLACEMENT_3D('',#2113,#2114,#2115);
#2117=CYLINDRICAL_SURFACE('',#2116,23.8714875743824);
#2118=DIRECTION('',(-1.,0.,0.));
#2119=VECTOR('',#2118,1.);
#2120=CARTESIAN_POINT('',(50.,-15.3992341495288,-20.8849274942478));
#2121=LINE('',#2120,#2119);
#2122=CARTESIAN_POINT('',(43.,-15.3992341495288,-20.8849274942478));
#2123=VERTEX_POINT('',#2122);
#2124=EDGE_CURVE('E340',#1495,#2123,#2121,.F.);
#2125=ORIENTED_EDGE('',*,*,#2124,.T.);
#2126=CARTESIAN_POINT('',(43.,-39.1214875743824,-23.55));
#2127=DIRECTION('',(1.,0.,0.));
#2128=DIRECTION('',(0.,0.,-1.));
#2129=AXIS2_PLACEMENT_3D('',#2126,#2127,#2128);
#2130=CIRCLE('',#2129,23.8714875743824);
#2131=EDGE_CURVE('E903',#2123,#47,#2130,.T.);
#2132=ORIENTED_EDGE('',*,*,#2131,.T.);
#2133=ORIENTED_EDGE('',*,*,#48,.T.);
#2134=ORIENTED_EDGE('',*,*,#285,.T.);
#2135=DIRECTION('',(-1.,0.,0.));
#2136=VECTOR('',#2135,1.);
#2137=CARTESIAN_POINT('',(50.,-15.3992341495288,-20.8849274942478));
#2138=LINE('',#2137,#2136);
#2139=EDGE_CURVE('E342',#277,#1706,#2138,.F.);
#2140=ORIENTED_EDGE('',*,*,#2139,.T.);
#2141=ORIENTED_EDGE('',*,*,#1709,.T.);
#2142=DIRECTION('',(-1.,0.,0.));
#2143=VECTOR('',#2142,1.);
#2144=CARTESIAN_POINT('',(50.,-15.3992341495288,-20.8849274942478));
#2145=LINE('',#2144,#2143);
#2146=EDGE_CURVE('E341',#1708,#1493,#2145,.F.);
#2147=ORIENTED_EDGE('',*,*,#2146,.T.);
#2148=ORIENTED_EDGE('',*,*,#1496,.T.);
#2149=EDGE_LOOP('',(#2125,#2132,#2133,#2134,#2140,#2141,#2147,#2148));
#2150=FACE_BOUND('',#2149,.T.);
#2151=ADVANCED_FACE('F397',(#2150),#2117,.F.);
#2152=CARTESIAN_POINT('',(50.,39.1214875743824,-23.55));
#2153=DIRECTION('',(-1.,0.,0.));
#2154=DIRECTION('',(0.,0.,1.));
#2155=AXIS2_PLACEMENT_3D('',#2152,#2153,#2154);
#2156=CYLINDRICAL_SURFACE('',#2155,23.8714875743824);
#2157=ORIENTED_EDGE('',*,*,#220,.F.);
#2158=CARTESIAN_POINT('',(43.,39.1214875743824,-23.55));
#2159=DIRECTION('',(1.,0.,0.));
#2160=DIRECTION('',(0.,0.,-1.));
#2161=AXIS2_PLACEMENT_3D('',#2158,#2159,#2160);
#2162=CIRCLE('',#2161,23.8714875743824);
#2163=CARTESIAN_POINT('',(43.,15.3992341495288,-20.8849274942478));
#2164=VERTEX_POINT('',#2163);
#2165=EDGE_CURVE('E906',#211,#2164,#2162,.T.);
#2166=ORIENTED_EDGE('',*,*,#2165,.T.);
#2167=DIRECTION('',(-1.,0.,0.));
#2168=VECTOR('',#2167,1.);
#2169=CARTESIAN_POINT('',(50.,15.3992341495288,-20.8849274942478));
#2170=LINE('',#2169,#2168);
#2171=EDGE_CURVE('E1379',#2164,#1915,#2170,.T.);
#2172=ORIENTED_EDGE('',*,*,#2171,.T.);
#2173=ORIENTED_EDGE('',*,*,#1918,.T.);
#2174=DIRECTION('',(-1.,0.,0.));
#2175=VECTOR('',#2174,1.);
#2176=CARTESIAN_POINT('',(50.,15.3992341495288,-20.8849274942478));
#2177=LINE('',#2176,#2175);
#2178=EDGE_CURVE('E1382',#1917,#1280,#2177,.T.);
#2179=ORIENTED_EDGE('',*,*,#2178,.T.);
#2180=ORIENTED_EDGE('',*,*,#1283,.T.);
#2181=DIRECTION('',(-1.,0.,0.));
#2182=VECTOR('',#2181,1.);
#2183=CARTESIAN_POINT('',(50.,15.3992341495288,-20.8849274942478));
#2184=LINE('',#2183,#2182);
#2185=EDGE_CURVE('E931',#1282,#251,#2184,.T.);
#2186=ORIENTED_EDGE('',*,*,#2185,.T.);
#2187=ORIENTED_EDGE('',*,*,#252,.T.);
#2188=EDGE_LOOP('',(#2157,#2166,#2172,#2173,#2179,#2180,#2186,#2187));
#2189=FACE_BOUND('',#2188,.T.);
#2190=ADVANCED_FACE('F405',(#2189),#2156,.F.);
#2191=CARTESIAN_POINT('',(50.,0.,-72.0435791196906));
#2192=DIRECTION('',(1.,0.,0.));
#2193=DIRECTION('',(0.,0.,-1.));
#2194=AXIS2_PLACEMENT_3D('',#2191,#2192,#2193);
#2195=PLANE('',#2194);
#2196=CARTESIAN_POINT('',(50.,-39.1214875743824,-23.55));
#2197=DIRECTION('',(1.,0.,0.));
#2198=DIRECTION('',(0.,0.,-1.));
#2199=AXIS2_PLACEMENT_3D('',#2196,#2197,#2198);
#2200=CIRCLE('',#2199,16.8714875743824);
#2201=CARTESIAN_POINT('',(50.,-22.3554731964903,-21.6664249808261));
#2202=VERTEX_POINT('',#2201);
#2203=EDGE_CURVE('E874',#94,#2202,#2200,.F.);
#2204=ORIENTED_EDGE('',*,*,#2203,.T.);
#2205=CARTESIAN_POINT('',(50.,-12.4179888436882,-20.55));
#2206=DIRECTION('',(1.,0.,0.));
#2207=DIRECTION('',(0.,0.,-1.));
#2208=AXIS2_PLACEMENT_3D('',#2205,#2206,#2207);
#2209=CIRCLE('',#2208,10.);
#2210=EDGE_CURVE('E877',#2202,#2011,#2209,.T.);
#2211=ORIENTED_EDGE('',*,*,#2210,.T.);
#2212=ORIENTED_EDGE('',*,*,#2012,.T.);
#2213=ORIENTED_EDGE('',*,*,#103,.T.);
#2214=EDGE_LOOP('',(#2204,#2211,#2212,#2213));
#2215=FACE_BOUND('',#2214,.T.);
#2216=ADVANCED_FACE('F647',(#2215),#2195,.F.);
#2217=ORIENTED_EDGE('',*,*,#2107,.T.);
#2218=CARTESIAN_POINT('',(50.,12.4179888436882,-20.55));
#2219=DIRECTION('',(1.,0.,0.));
#2220=DIRECTION('',(0.,0.,-1.));
#2221=AXIS2_PLACEMENT_3D('',#2218,#2219,#2220);
#2222=CIRCLE('',#2221,10.);
#2223=CARTESIAN_POINT('',(50.,22.3554731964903,-21.6664249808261));
#2224=VERTEX_POINT('',#2223);
#2225=EDGE_CURVE('E897',#2104,#2224,#2222,.T.);
#2226=ORIENTED_EDGE('',*,*,#2225,.T.);
#2227=CARTESIAN_POINT('',(50.,39.1214875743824,-23.55));
#2228=DIRECTION('',(1.,0.,0.));
#2229=DIRECTION('',(0.,0.,-1.));
#2230=AXIS2_PLACEMENT_3D('',#2227,#2228,#2229);
#2231=CIRCLE('',#2230,16.8714875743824);
#2232=EDGE_CURVE('E893',#2224,#158,#2231,.F.);
#2233=ORIENTED_EDGE('',*,*,#2232,.T.);
#2234=ORIENTED_EDGE('',*,*,#159,.F.);
#2235=EDGE_LOOP('',(#2217,#2226,#2233,#2234));
#2236=FACE_BOUND('',#2235,.T.);
#2237=ADVANCED_FACE('F651',(#2236),#2195,.F.);
#2238=CARTESIAN_POINT('',(50.,-12.4179888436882,-20.55));
#2239=DIRECTION('',(-1.,0.,0.));
#2240=DIRECTION('',(0.,0.,1.));
#2241=AXIS2_PLACEMENT_3D('',#2238,#2239,#2240);
#2242=CYLINDRICAL_SURFACE('',#2241,3.);
#2243=ORIENTED_EDGE('',*,*,#2057,.F.);
#2244=CARTESIAN_POINT('',(43.,-12.4179888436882,-20.55));
#2245=DIRECTION('',(1.,0.,0.));
#2246=DIRECTION('',(0.,0.,-1.));
#2247=AXIS2_PLACEMENT_3D('',#2244,#2245,#2246);
#2248=CIRCLE('',#2247,3.);
#2249=EDGE_CURVE('E884',#2050,#2123,#2248,.F.);
#2250=ORIENTED_EDGE('',*,*,#2249,.T.);
#2251=ORIENTED_EDGE('',*,*,#2124,.F.);
#2252=ORIENTED_EDGE('',*,*,#1529,.F.);
#2253=ORIENTED_EDGE('',*,*,#2146,.F.);
#2254=ORIENTED_EDGE('',*,*,#1742,.F.);
#2255=ORIENTED_EDGE('',*,*,#2139,.F.);
#2256=ORIENTED_EDGE('',*,*,#278,.F.);
#2257=EDGE_LOOP('',(#2243,#2250,#2251,#2252,#2253,#2254,#2255,#2256));
#2258=FACE_BOUND('',#2257,.T.);
#2259=ADVANCED_FACE('F364',(#2258),#2242,.T.);
#2260=CARTESIAN_POINT('',(50.,12.4179888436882,-20.55));
#2261=DIRECTION('',(-1.,0.,0.));
#2262=DIRECTION('',(0.,0.,1.));
#2263=AXIS2_PLACEMENT_3D('',#2260,#2261,#2262);
#2264=CYLINDRICAL_SURFACE('',#2263,3.);
#2265=ORIENTED_EDGE('',*,*,#2171,.F.);
#2266=CARTESIAN_POINT('',(43.,12.4179888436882,-20.55));
#2267=DIRECTION('',(1.,0.,0.));
#2268=DIRECTION('',(0.,0.,-1.));
#2269=AXIS2_PLACEMENT_3D('',#2266,#2267,#2268);
#2270=CIRCLE('',#2269,3.);
#2271=EDGE_CURVE('E904',#2164,#2065,#2270,.F.);
#2272=ORIENTED_EDGE('',*,*,#2271,.T.);
#2273=ORIENTED_EDGE('',*,*,#2066,.F.);
#2274=ORIENTED_EDGE('',*,*,#261,.F.);
#2275=ORIENTED_EDGE('',*,*,#2185,.F.);
#2276=ORIENTED_EDGE('',*,*,#1316,.F.);
#2277=ORIENTED_EDGE('',*,*,#2178,.F.);
#2278=ORIENTED_EDGE('',*,*,#1951,.F.);
#2279=EDGE_LOOP('',(#2265,#2272,#2273,#2274,#2275,#2276,#2277,#2278));
#2280=FACE_BOUND('',#2279,.T.);
#2281=ADVANCED_FACE('F444',(#2280),#2264,.T.);
#2282=CARTESIAN_POINT('',(43.,-39.1214875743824,-23.55));
#2283=DIRECTION('',(1.,0.,0.));
#2284=DIRECTION('',(0.,0.,-1.));
#2285=AXIS2_PLACEMENT_3D('',#2282,#2283,#2284);
#2286=TOROIDAL_SURFACE('',#2285,16.8714875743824,7.);
#2287=ORIENTED_EDGE('',*,*,#95,.F.);
#2288=ORIENTED_EDGE('',*,*,#2131,.F.);
#2289=CARTESIAN_POINT('',(43.,-22.3554731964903,-21.6664249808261));
#2290=DIRECTION('',(0.,-0.111642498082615,0.993748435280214));
#2291=DIRECTION('',(0.,-0.993748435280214,-0.111642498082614));
#2292=AXIS2_PLACEMENT_3D('',#2289,#2290,#2291);
#2293=CIRCLE('',#2292,7.);
#2294=EDGE_CURVE('E708',#2202,#2123,#2293,.T.);
#2295=ORIENTED_EDGE('',*,*,#2294,.F.);
#2296=ORIENTED_EDGE('',*,*,#2203,.F.);
#2297=EDGE_LOOP('',(#2287,#2288,#2295,#2296));
#2298=FACE_BOUND('',#2297,.T.);
#2299=ADVANCED_FACE('F439',(#2298),#2286,.F.);
#2300=CARTESIAN_POINT('',(43.,-12.4179888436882,-20.55));
#2301=DIRECTION('',(1.,0.,0.));
#2302=DIRECTION('',(0.,0.,-1.));
#2303=AXIS2_PLACEMENT_3D('',#2300,#2301,#2302);
#2304=TOROIDAL_SURFACE('',#2303,10.,7.);
#2305=ORIENTED_EDGE('',*,*,#2294,.T.);
#2306=ORIENTED_EDGE('',*,*,#2249,.F.);
#2307=ORIENTED_EDGE('',*,*,#2051,.F.);
#2308=ORIENTED_EDGE('',*,*,#2210,.F.);
#2309=EDGE_LOOP('',(#2305,#2306,#2307,#2308));
#2310=FACE_BOUND('',#2309,.T.);
#2311=ADVANCED_FACE('F445',(#2310),#2304,.F.);
#2312=CARTESIAN_POINT('',(43.,39.1214875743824,-23.55));
#2313=DIRECTION('',(1.,0.,0.));
#2314=DIRECTION('',(0.,0.,-1.));
#2315=AXIS2_PLACEMENT_3D('',#2312,#2313,#2314);
#2316=TOROIDAL_SURFACE('',#2315,16.8714875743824,7.);
#2317=ORIENTED_EDGE('',*,*,#212,.F.);
#2318=ORIENTED_EDGE('',*,*,#2232,.F.);
#2319=CARTESIAN_POINT('',(43.,22.3554731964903,-21.6664249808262));
#2320=DIRECTION('',(0.,0.111642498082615,0.993748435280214));
#2321=DIRECTION('',(0.,-0.993748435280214,0.111642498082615));
#2322=AXIS2_PLACEMENT_3D('',#2319,#2320,#2321);
#2323=CIRCLE('',#2322,7.);
#2324=EDGE_CURVE('E701',#2164,#2224,#2323,.T.);
#2325=ORIENTED_EDGE('',*,*,#2324,.F.);
#2326=ORIENTED_EDGE('',*,*,#2165,.F.);
#2327=EDGE_LOOP('',(#2317,#2318,#2325,#2326));
#2328=FACE_BOUND('',#2327,.T.);
#2329=ADVANCED_FACE('F449',(#2328),#2316,.F.);
#2330=CARTESIAN_POINT('',(43.,12.4179888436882,-20.55));
#2331=DIRECTION('',(1.,0.,0.));
#2332=DIRECTION('',(0.,0.,-1.));
#2333=AXIS2_PLACEMENT_3D('',#2330,#2331,#2332);
#2334=TOROIDAL_SURFACE('',#2333,10.,7.);
#2335=ORIENTED_EDGE('',*,*,#2105,.F.);
#2336=ORIENTED_EDGE('',*,*,#2271,.F.);
#2337=ORIENTED_EDGE('',*,*,#2324,.T.);
#2338=ORIENTED_EDGE('',*,*,#2225,.F.);
#2339=EDGE_LOOP('',(#2335,#2336,#2337,#2338));
#2340=FACE_BOUND('',#2339,.T.);
#2341=ADVANCED_FACE('F446',(#2340),#2334,.F.);
#2342=CARTESIAN_POINT('',(34.,17.4398492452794,-5.));
#2343=DIRECTION('',(0.,0.,1.));
#2344=DIRECTION('',(1.,0.,0.));
#2345=AXIS2_PLACEMENT_3D('',#2342,#2343,#2344);
#2346=PLANE('',#2345);
#2347=ORIENTED_EDGE('',*,*,#725,.T.);
#2348=EDGE_LOOP('',(#2347));
#2349=FACE_BOUND('',#2348,.T.);
#2350=ORIENTED_EDGE('',*,*,#1962,.T.);
#2351=EDGE_LOOP('',(#2350));
#2352=FACE_BOUND('',#2351,.T.);
#2353=ADVANCED_FACE('F448',(#2349,#2352),#2346,.T.);
#2354=CARTESIAN_POINT('',(9.,-17.4398492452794,-5.));
#2355=DIRECTION('',(0.,0.,1.));
#2356=DIRECTION('',(1.,0.,0.));
#2357=AXIS2_PLACEMENT_3D('',#2354,#2355,#2356);
#2358=PLANE('',#2357);
#2359=ORIENTED_EDGE('',*,*,#753,.T.);
#2360=EDGE_LOOP('',(#2359));
#2361=FACE_BOUND('',#2360,.T.);
#2362=ORIENTED_EDGE('',*,*,#1753,.T.);
#2363=EDGE_LOOP('',(#2362));
#2364=FACE_BOUND('',#2363,.T.);
#2365=ADVANCED_FACE('F594',(#2361,#2364),#2358,.T.);
#2366=CARTESIAN_POINT('',(34.,-17.4398492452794,-5.));
#2367=DIRECTION('',(0.,0.,1.));
#2368=DIRECTION('',(1.,0.,0.));
#2369=AXIS2_PLACEMENT_3D('',#2366,#2367,#2368);
#2370=PLANE('',#2369);
#2371=ORIENTED_EDGE('',*,*,#781,.T.);
#2372=EDGE_LOOP('',(#2371));
#2373=FACE_BOUND('',#2372,.T.);
#2374=ORIENTED_EDGE('',*,*,#1540,.T.);
#2375=EDGE_LOOP('',(#2374));
#2376=FACE_BOUND('',#2375,.T.);
#2377=ADVANCED_FACE('F588',(#2373,#2376),#2370,.T.);
#2378=CARTESIAN_POINT('',(9.,17.4398492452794,-5.));
#2379=DIRECTION('',(0.,0.,1.));
#2380=DIRECTION('',(1.,0.,0.));
#2381=AXIS2_PLACEMENT_3D('',#2378,#2379,#2380);
#2382=PLANE('',#2381);
#2383=ORIENTED_EDGE('',*,*,#809,.T.);
#2384=EDGE_LOOP('',(#2383));
#2385=FACE_BOUND('',#2384,.T.);
#2386=ORIENTED_EDGE('',*,*,#1327,.T.);
#2387=EDGE_LOOP('',(#2386));
#2388=FACE_BOUND('',#2387,.T.);
#2389=ADVANCED_FACE('F578',(#2385,#2388),#2382,.T.);
#2390=CARTESIAN_POINT('',(34.,0.,-19.55));
#2391=DIRECTION('',(0.,0.,-1.));
#2392=DIRECTION('',(-1.,0.,0.));
#2393=AXIS2_PLACEMENT_3D('',#2390,#2391,#2392);
#2394=CYLINDRICAL_SURFACE('',#2393,5.);
#2395=CARTESIAN_POINT('',(34.,0.,-20.55));
#2396=DIRECTION('',(0.,0.,-1.));
#2397=DIRECTION('',(-1.,0.,0.));
#2398=AXIS2_PLACEMENT_3D('',#2395,#2396,#2397);
#2399=CIRCLE('',#2398,5.);
#2400=CARTESIAN_POINT('',(29.,0.,-20.55));
#2401=VERTEX_POINT('',#2400);
#2402=EDGE_CURVE('E535',#2401,#2401,#2399,.F.);
#2403=ORIENTED_EDGE('',*,*,#2402,.T.);
#2404=EDGE_LOOP('',(#2403));
#2405=FACE_BOUND('',#2404,.T.);
#2406=ORIENTED_EDGE('',*,*,#1990,.T.);
#2407=EDGE_LOOP('',(#2406));
#2408=FACE_BOUND('',#2407,.T.);
#2409=ADVANCED_FACE('F576',(#2405,#2408),#2394,.F.);
#2410=CARTESIAN_POINT('',(34.,0.,-19.55));
#2411=DIRECTION('',(0.,0.,-1.));
#2412=DIRECTION('',(-1.,0.,0.));
#2413=AXIS2_PLACEMENT_3D('',#2410,#2411,#2412);
#2414=PLANE('',#2413);
#2415=CARTESIAN_POINT('',(34.,0.,-19.55));
#2416=DIRECTION('',(0.,0.,-1.));
#2417=DIRECTION('',(-1.,0.,0.));
#2418=AXIS2_PLACEMENT_3D('',#2415,#2416,#2417);
#2419=CIRCLE('',#2418,4.);
#2420=CARTESIAN_POINT('',(30.,0.,-19.55));
#2421=VERTEX_POINT('',#2420);
#2422=EDGE_CURVE('E537',#2421,#2421,#2419,.T.);
#2423=ORIENTED_EDGE('',*,*,#2422,.T.);
#2424=EDGE_LOOP('',(#2423));
#2425=FACE_BOUND('',#2424,.T.);
#2426=CARTESIAN_POINT('',(34.,0.,-19.55));
#2427=DIRECTION('',(0.,0.,-1.));
#2428=DIRECTION('',(-1.,0.,0.));
#2429=AXIS2_PLACEMENT_3D('',#2426,#2427,#2428);
#2430=CIRCLE('',#2429,2.1);
#2431=CARTESIAN_POINT('',(31.9,0.,-19.55));
#2432=VERTEX_POINT('',#2431);
#2433=EDGE_CURVE('E771',#2432,#2432,#2430,.T.);
#2434=ORIENTED_EDGE('',*,*,#2433,.F.);
#2435=EDGE_LOOP('',(#2434));
#2436=FACE_BOUND('',#2435,.T.);
#2437=ADVANCED_FACE('F572',(#2425,#2436),#2414,.T.);
#2438=CARTESIAN_POINT('',(9.,0.,-19.55));
#2439=DIRECTION('',(0.,0.,-1.));
#2440=DIRECTION('',(-1.,0.,0.));
#2441=AXIS2_PLACEMENT_3D('',#2438,#2439,#2440);
#2442=CYLINDRICAL_SURFACE('',#2441,5.);
#2443=CARTESIAN_POINT('',(9.,0.,-20.55));
#2444=DIRECTION('',(0.,0.,-1.));
#2445=DIRECTION('',(-1.,0.,0.));
#2446=AXIS2_PLACEMENT_3D('',#2443,#2444,#2445);
#2447=CIRCLE('',#2446,5.);
#2448=CARTESIAN_POINT('',(4.,0.,-20.55));
#2449=VERTEX_POINT('',#2448);
#2450=EDGE_CURVE('E523',#2449,#2449,#2447,.F.);
#2451=ORIENTED_EDGE('',*,*,#2450,.T.);
#2452=EDGE_LOOP('',(#2451));
#2453=FACE_BOUND('',#2452,.T.);
#2454=ORIENTED_EDGE('',*,*,#1979,.T.);
#2455=EDGE_LOOP('',(#2454));
#2456=FACE_BOUND('',#2455,.T.);
#2457=ADVANCED_FACE('F569',(#2453,#2456),#2442,.F.);
#2458=CARTESIAN_POINT('',(9.,0.,-19.55));
#2459=DIRECTION('',(0.,0.,-1.));
#2460=DIRECTION('',(-1.,0.,0.));
#2461=AXIS2_PLACEMENT_3D('',#2458,#2459,#2460);
#2462=PLANE('',#2461);
#2463=CARTESIAN_POINT('',(9.,0.,-19.55));
#2464=DIRECTION('',(0.,0.,-1.));
#2465=DIRECTION('',(-1.,0.,0.));
#2466=AXIS2_PLACEMENT_3D('',#2463,#2464,#2465);
#2467=CIRCLE('',#2466,4.);
#2468=CARTESIAN_POINT('',(5.,0.,-19.55));
#2469=VERTEX_POINT('',#2468);
#2470=EDGE_CURVE('E530',#2469,#2469,#2467,.T.);
#2471=ORIENTED_EDGE('',*,*,#2470,.T.);
#2472=EDGE_LOOP('',(#2471));
#2473=FACE_BOUND('',#2472,.T.);
#2474=CARTESIAN_POINT('',(9.,0.,-19.55));
#2475=DIRECTION('',(0.,0.,-1.));
#2476=DIRECTION('',(-1.,0.,0.));
#2477=AXIS2_PLACEMENT_3D('',#2474,#2475,#2476);
#2478=CIRCLE('',#2477,2.1);
#2479=CARTESIAN_POINT('',(6.9,0.,-19.55));
#2480=VERTEX_POINT('',#2479);
#2481=EDGE_CURVE('E767',#2480,#2480,#2478,.T.);
#2482=ORIENTED_EDGE('',*,*,#2481,.F.);
#2483=EDGE_LOOP('',(#2482));
#2484=FACE_BOUND('',#2483,.T.);
#2485=ADVANCED_FACE('F566',(#2473,#2484),#2462,.T.);
#2486=CARTESIAN_POINT('',(9.,0.,0.));
#2487=DIRECTION('',(0.,0.,-1.));
#2488=DIRECTION('',(-1.,0.,0.));
#2489=AXIS2_PLACEMENT_3D('',#2486,#2487,#2488);
#2490=CYLINDRICAL_SURFACE('',#2489,2.1);
#2491=ORIENTED_EDGE('',*,*,#2481,.T.);
#2492=EDGE_LOOP('',(#2491));
#2493=FACE_BOUND('',#2492,.T.);
#2494=ORIENTED_EDGE('',*,*,#1021,.F.);
#2495=EDGE_LOOP('',(#2494));
#2496=FACE_BOUND('',#2495,.T.);
#2497=ADVANCED_FACE('F560',(#2493,#2496),#2490,.F.);
#2498=CARTESIAN_POINT('',(34.,0.,0.));
#2499=DIRECTION('',(0.,0.,-1.));
#2500=DIRECTION('',(-1.,0.,0.));
#2501=AXIS2_PLACEMENT_3D('',#2498,#2499,#2500);
#2502=CYLINDRICAL_SURFACE('',#2501,2.1);
#2503=ORIENTED_EDGE('',*,*,#2433,.T.);
#2504=EDGE_LOOP('',(#2503));
#2505=FACE_BOUND('',#2504,.T.);
#2506=ORIENTED_EDGE('',*,*,#1106,.F.);
#2507=EDGE_LOOP('',(#2506));
#2508=FACE_BOUND('',#2507,.T.);
#2509=ADVANCED_FACE('F468',(#2505,#2508),#2502,.F.);
#2510=CARTESIAN_POINT('',(34.,0.,-20.55));
#2511=DIRECTION('',(0.,0.,-1.));
#2512=DIRECTION('',(-1.,0.,0.));
#2513=AXIS2_PLACEMENT_3D('',#2510,#2511,#2512);
#2514=TOROIDAL_SURFACE('',#2513,4.,1.);
#2515=ORIENTED_EDGE('',*,*,#2402,.F.);
#2516=EDGE_LOOP('',(#2515));
#2517=FACE_BOUND('',#2516,.T.);
#2518=ORIENTED_EDGE('',*,*,#2422,.F.);
#2519=EDGE_LOOP('',(#2518));
#2520=FACE_BOUND('',#2519,.T.);
#2521=ADVANCED_FACE('F467',(#2517,#2520),#2514,.F.);
#2522=CARTESIAN_POINT('',(9.,0.,-20.55));
#2523=DIRECTION('',(0.,0.,-1.));
#2524=DIRECTION('',(-1.,0.,0.));
#2525=AXIS2_PLACEMENT_3D('',#2522,#2523,#2524);
#2526=TOROIDAL_SURFACE('',#2525,4.,1.);
#2527=ORIENTED_EDGE('',*,*,#2450,.F.);
#2528=EDGE_LOOP('',(#2527));
#2529=FACE_BOUND('',#2528,.T.);
#2530=ORIENTED_EDGE('',*,*,#2470,.F.);
#2531=EDGE_LOOP('',(#2530));
#2532=FACE_BOUND('',#2531,.T.);
#2533=ADVANCED_FACE('F466',(#2529,#2532),#2526,.F.);
#2534=CARTESIAN_POINT('',(43.,0.,-4.75));
#2535=DIRECTION('',(1.,0.,0.));
#2536=DIRECTION('',(0.,0.,-1.));
#2537=AXIS2_PLACEMENT_3D('',#2534,#2535,#2536);
#2538=TOROIDAL_SURFACE('',#2537,11.85,1.);
#2539=ORIENTED_EDGE('',*,*,#905,.T.);
#2540=ORIENTED_EDGE('',*,*,#1116,.F.);
#2541=ORIENTED_EDGE('',*,*,#929,.F.);
#2542=ORIENTED_EDGE('',*,*,#348,.F.);
#2543=EDGE_LOOP('',(#2539,#2540,#2541,#2542));
#2544=FACE_BOUND('',#2543,.T.);
#2545=ADVANCED_FACE('F473',(#2544),#2538,.F.);
#2546=CARTESIAN_POINT('',(0.,0.,-0.4));
#2547=DIRECTION('',(0.,0.,1.));
#2548=DIRECTION('',(1.,0.,0.));
#2549=AXIS2_PLACEMENT_3D('',#2546,#2547,#2548);
#2550=PLANE('',#2549);
#2551=ORIENTED_EDGE('',*,*,#135,.T.);
#2552=ORIENTED_EDGE('',*,*,#242,.T.);
#2553=ORIENTED_EDGE('',*,*,#867,.T.);
#2554=ORIENTED_EDGE('',*,*,#897,.T.);
#2555=ORIENTED_EDGE('',*,*,#331,.T.);
#2556=ORIENTED_EDGE('',*,*,#921,.T.);
#2557=ORIENTED_EDGE('',*,*,#836,.T.);
#2558=ORIENTED_EDGE('',*,*,#290,.T.);
#2559=ORIENTED_EDGE('',*,*,#32,.T.);
#2560=ORIENTED_EDGE('',*,*,#619,.F.);
#2561=ORIENTED_EDGE('',*,*,#700,.F.);
#2562=ORIENTED_EDGE('',*,*,#579,.F.);
#2563=ORIENTED_EDGE('',*,*,#545,.T.);
#2564=ORIENTED_EDGE('',*,*,#513,.F.);
#2565=ORIENTED_EDGE('',*,*,#479,.T.);
#2566=ORIENTED_EDGE('',*,*,#447,.F.);
#2567=ORIENTED_EDGE('',*,*,#413,.T.);
#2568=ORIENTED_EDGE('',*,*,#381,.F.);
#2569=ORIENTED_EDGE('',*,*,#676,.F.);
#2570=ORIENTED_EDGE('',*,*,#645,.F.);
#2571=EDGE_LOOP('',(#2551,#2552,#2553,#2554,#2555,#2556,#2557,#2558,#2559,#2560,#2561,#2562,
#2563,#2564,#2565,#2566,#2567,#2568,#2569,#2570));
#2572=FACE_BOUND('',#2571,.T.);
#2573=ORIENTED_EDGE('',*,*,#820,.T.);
#2574=EDGE_LOOP('',(#2573));
#2575=FACE_BOUND('',#2574,.T.);
#2576=ORIENTED_EDGE('',*,*,#792,.T.);
#2577=EDGE_LOOP('',(#2576));
#2578=FACE_BOUND('',#2577,.T.);
#2579=ORIENTED_EDGE('',*,*,#764,.T.);
#2580=EDGE_LOOP('',(#2579));
#2581=FACE_BOUND('',#2580,.T.);
#2582=ORIENTED_EDGE('',*,*,#736,.T.);
#2583=EDGE_LOOP('',(#2582));
#2584=FACE_BOUND('',#2583,.T.);
#2585=ADVANCED_FACE('F266',(#2572,#2575,#2578,#2581,#2584),#2550,.T.);
#2586=CLOSED_SHELL('',(#121,#230,#317,#358,#400,#433,#466,#499,#532,#565,#598,#631,#664,#688,
#712,#740,#768,#796,#824,#855,#886,#910,#934,#1122,#1331,#1544,#1757,#1966,#2112,#2151,#2190,
#2216,#2237,#2259,#2281,#2299,#2311,#2329,#2341,#2353,#2365,#2377,#2389,#2409,#2437,#2457,#2485,
#2497,#2509,#2521,#2533,#2545,#2585));
#2587=MANIFOLD_SOLID_BREP('B2',#2586);
#2588=ADVANCED_BREP_SHAPE_REPRESENTATION('',(#18,#2587),#14);
#2589=SHAPE_DEFINITION_REPRESENTATION(#9,#2588);
ENDSEC;
END-ISO-10303-21;
